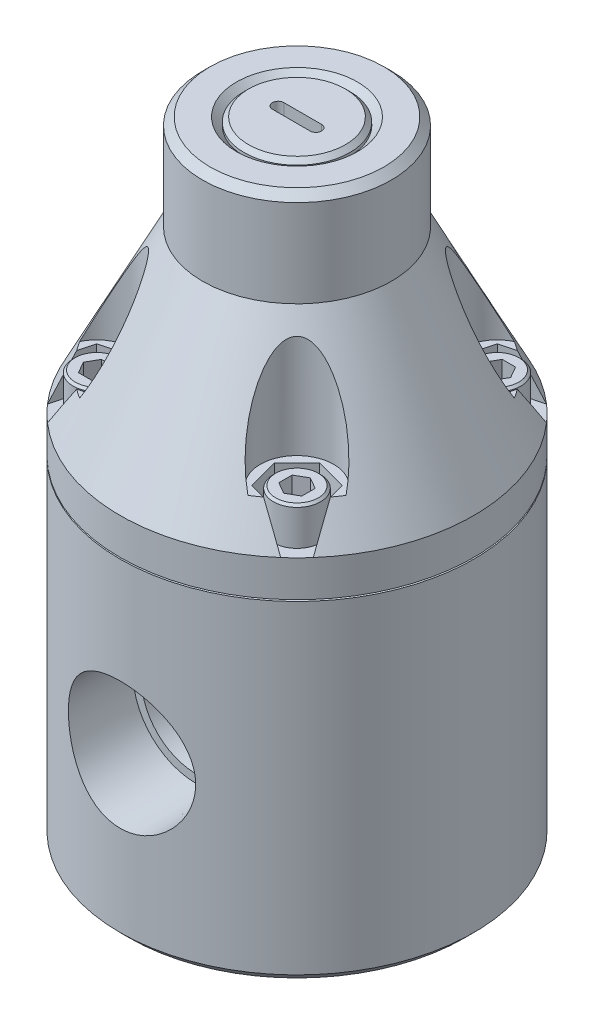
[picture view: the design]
ISO-10303-21;
HEADER;
FILE_DESCRIPTION(('STEP AP214'),'2;1');
FILE_NAME('part.step','',(''),(''),'','','');
FILE_SCHEMA(('AUTOMOTIVE_DESIGN { 1 0 10303 214 1 1 1 1 }'));
ENDSEC;
DATA;
#1=APPLICATION_CONTEXT('core data for automotive mechanical design processes');
#2=APPLICATION_PROTOCOL_DEFINITION('international standard','automotive_design',2000,#1);
#3=PRODUCT_CONTEXT('',#1,'mechanical');
#4=PRODUCT('Part','Part','',(#3));
#5=PRODUCT_RELATED_PRODUCT_CATEGORY('part','',(#4));
#6=PRODUCT_DEFINITION_FORMATION('','',#4);
#7=PRODUCT_DEFINITION_CONTEXT('part definition',#1,'design');
#8=PRODUCT_DEFINITION('design','',#6,#7);
#9=PRODUCT_DEFINITION_SHAPE('','',#8);
#10=(LENGTH_UNIT() NAMED_UNIT(*) SI_UNIT(.MILLI.,.METRE.));
#11=(NAMED_UNIT(*) PLANE_ANGLE_UNIT() SI_UNIT($,.RADIAN.));
#12=(NAMED_UNIT(*) SI_UNIT($,.STERADIAN.) SOLID_ANGLE_UNIT());
#13=UNCERTAINTY_MEASURE_WITH_UNIT(LENGTH_MEASURE(1.E-05),#10,'distance_accuracy_value','');
#14=(GEOMETRIC_REPRESENTATION_CONTEXT(3) GLOBAL_UNCERTAINTY_ASSIGNED_CONTEXT((#13)) GLOBAL_UNIT_ASSIGNED_CONTEXT((#10,
#11,#12)) REPRESENTATION_CONTEXT('',''));
#15=CARTESIAN_POINT('',(0.,0.,0.));
#16=DIRECTION('',(0.,0.,1.));
#17=DIRECTION('',(1.,0.,0.));
#18=AXIS2_PLACEMENT_3D('',#15,#16,#17);
#19=CARTESIAN_POINT('',(0.,62.23,0.));
#20=DIRECTION('',(0.,-1.,0.));
#21=DIRECTION('',(0.,0.,-1.));
#22=AXIS2_PLACEMENT_3D('',#19,#20,#21);
#23=CONICAL_SURFACE('',#22,29.718,0.471096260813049);
#24=CARTESIAN_POINT('',(-22.3373805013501,62.2298,-19.6011992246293));
#25=CARTESIAN_POINT('',(-22.2547645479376,62.7634166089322,-19.2832519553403));
#26=CARTESIAN_POINT('',(-22.1717744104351,63.29612059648,-18.9638646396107));
#27=CARTESIAN_POINT('',(-22.0049530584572,64.3594037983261,-18.3218531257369));
#28=CARTESIAN_POINT('',(-21.9211218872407,64.8899831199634,-17.9992290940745));
#29=CARTESIAN_POINT('',(-21.7525165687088,65.9487768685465,-17.3503519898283));
#30=CARTESIAN_POINT('',(-21.6677424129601,66.4769912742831,-17.0240988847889));
#31=CARTESIAN_POINT('',(-21.4971243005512,67.5307185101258,-16.367475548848));
#32=CARTESIAN_POINT('',(-21.4112802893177,68.0562312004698,-16.0371051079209));
#33=CARTESIAN_POINT('',(-21.3248419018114,68.5802,-15.7044472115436));
#34=B_SPLINE_CURVE_WITH_KNOTS('',3,(#24,#25,#26,#27,#28,#29,#30,#31,#32,#33),.UNSPECIFIED.,.F.,
.F.,(4,2,2,2,4),(0.,1.87988537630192,3.75967455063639,5.63948054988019,7.51938283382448),.UNSPECIFIED.);
#35=CARTESIAN_POINT('',(-22.3373495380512,62.23,-19.6010800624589));
#36=VERTEX_POINT('',#35);
#37=CARTESIAN_POINT('',(-21.324874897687,68.58,-15.7045741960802));
#38=VERTEX_POINT('',#37);
#39=EDGE_CURVE('E625',#36,#38,#34,.T.);
#40=ORIENTED_EDGE('',*,*,#39,.F.);
#41=CARTESIAN_POINT('',(0.,62.23,0.));
#42=DIRECTION('',(0.,-1.,0.));
#43=DIRECTION('',(0.,0.,-1.));
#44=AXIS2_PLACEMENT_3D('',#41,#42,#43);
#45=CIRCLE('',#44,29.718);
#46=CARTESIAN_POINT('',(-22.3373495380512,62.23,19.6010800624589));
#47=VERTEX_POINT('',#46);
#48=EDGE_CURVE('E950',#47,#36,#45,.T.);
#49=ORIENTED_EDGE('',*,*,#48,.F.);
#50=CARTESIAN_POINT('',(-21.3248419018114,68.5802,15.7044472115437));
#51=CARTESIAN_POINT('',(-21.4112802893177,68.0562312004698,16.0371051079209));
#52=CARTESIAN_POINT('',(-21.4971243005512,67.5307185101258,16.367475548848));
#53=CARTESIAN_POINT('',(-21.66774241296,66.4769912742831,17.024098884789));
#54=CARTESIAN_POINT('',(-21.7525165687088,65.9487768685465,17.3503519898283));
#55=CARTESIAN_POINT('',(-21.9211218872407,64.8899831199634,17.9992290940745));
#56=CARTESIAN_POINT('',(-22.0049530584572,64.3594037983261,18.3218531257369));
#57=CARTESIAN_POINT('',(-22.1717744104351,63.29612059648,18.9638646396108));
#58=CARTESIAN_POINT('',(-22.2547645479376,62.7634166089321,19.2832519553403));
#59=CARTESIAN_POINT('',(-22.3373805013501,62.2298,19.6011992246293));
#60=B_SPLINE_CURVE_WITH_KNOTS('',3,(#50,#51,#52,#53,#54,#55,#56,#57,#58,#59),.UNSPECIFIED.,.F.,
.F.,(4,2,2,2,4),(0.,1.87990228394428,3.75970828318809,5.63949745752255,7.51938283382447),.UNSPECIFIED.);
#61=CARTESIAN_POINT('',(-21.324874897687,68.58,15.7045741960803));
#62=VERTEX_POINT('',#61);
#63=EDGE_CURVE('E679',#62,#47,#60,.T.);
#64=ORIENTED_EDGE('',*,*,#63,.F.);
#65=CARTESIAN_POINT('',(0.,68.58,0.));
#66=DIRECTION('',(0.,1.,0.));
#67=DIRECTION('',(0.,0.,1.));
#68=AXIS2_PLACEMENT_3D('',#65,#66,#67);
#69=CIRCLE('',#68,26.4836542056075);
#70=CARTESIAN_POINT('',(-22.3908779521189,68.58,14.1432854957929));
#71=VERTEX_POINT('',#70);
#72=EDGE_CURVE('E1254',#62,#71,#69,.F.);
#73=ORIENTED_EDGE('',*,*,#72,.T.);
#74=CARTESIAN_POINT('',(-22.3909303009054,68.5798,14.143393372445));
#75=CARTESIAN_POINT('',(-22.350304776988,68.7350022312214,14.0596815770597));
#76=CARTESIAN_POINT('',(-22.3081630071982,68.89069928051,13.9776470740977));
#77=CARTESIAN_POINT('',(-22.2210302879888,69.2029732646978,13.8168553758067));
#78=CARTESIAN_POINT('',(-22.1760395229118,69.3595501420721,13.7380979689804));
#79=CARTESIAN_POINT('',(-22.0370947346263,69.8303500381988,13.5066666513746));
#80=CARTESIAN_POINT('',(-21.9391379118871,70.1457572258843,13.3587718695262));
#81=CARTESIAN_POINT('',(-21.7338262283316,70.7787217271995,13.0753567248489));
#82=CARTESIAN_POINT('',(-21.6264783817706,71.0962772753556,12.9398272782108));
#83=CARTESIAN_POINT('',(-21.4032338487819,71.7332404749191,12.6806046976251));
#84=CARTESIAN_POINT('',(-21.2873363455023,72.0526483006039,12.556912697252));
#85=CARTESIAN_POINT('',(-21.0470421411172,72.6946343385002,12.3204109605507));
#86=CARTESIAN_POINT('',(-20.9226003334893,73.0172202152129,12.2076680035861));
#87=CARTESIAN_POINT('',(-20.6663853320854,73.6632945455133,11.9936819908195));
#88=CARTESIAN_POINT('',(-20.5346119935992,73.9867830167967,11.8924391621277));
#89=CARTESIAN_POINT('',(-20.2641447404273,74.6342665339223,11.7013595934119));
#90=CARTESIAN_POINT('',(-20.1254503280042,74.9582616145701,11.6115236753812));
#91=CARTESIAN_POINT('',(-19.8414364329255,75.6062899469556,11.4433041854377));
#92=CARTESIAN_POINT('',(-19.6961171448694,75.9303231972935,11.3649202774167));
#93=CARTESIAN_POINT('',(-19.3211632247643,76.7476954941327,11.1817059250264));
#94=CARTESIAN_POINT('',(-19.0872302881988,77.2408247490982,11.0845248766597));
#95=CARTESIAN_POINT('',(-18.7249280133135,77.9784605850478,10.9599064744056));
#96=CARTESIAN_POINT('',(-18.6022415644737,78.2240315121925,10.9218885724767));
#97=CARTESIAN_POINT('',(-18.3529388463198,78.7141977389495,10.8531925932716));
#98=CARTESIAN_POINT('',(-18.2263228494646,78.9587931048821,10.8225140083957));
#99=CARTESIAN_POINT('',(-17.9690231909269,79.4465771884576,10.7688733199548));
#100=CARTESIAN_POINT('',(-17.8383410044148,79.6897663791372,10.7459084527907));
#101=CARTESIAN_POINT('',(-17.5726008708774,80.1743656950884,10.7081842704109));
#102=CARTESIAN_POINT('',(-17.4375433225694,80.4157759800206,10.693424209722));
#103=CARTESIAN_POINT('',(-17.1627429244,80.8961071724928,10.6727907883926));
#104=CARTESIAN_POINT('',(-17.0230031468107,81.1350295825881,10.6669117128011));
#105=CARTESIAN_POINT('',(-16.7382475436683,81.6097183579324,10.6649433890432));
#106=CARTESIAN_POINT('',(-16.5932325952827,81.8454852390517,10.6688525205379));
#107=CARTESIAN_POINT('',(-16.2968182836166,82.3133650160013,10.6877509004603));
#108=CARTESIAN_POINT('',(-16.1454043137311,82.5454676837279,10.7027669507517));
#109=CARTESIAN_POINT('',(-15.8354539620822,83.0038758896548,10.7457309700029));
#110=CARTESIAN_POINT('',(-15.6769137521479,83.2301782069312,10.7736859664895));
#111=CARTESIAN_POINT('',(-15.3515270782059,83.6741617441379,10.8451251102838));
#112=CARTESIAN_POINT('',(-15.1846866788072,83.8918490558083,10.8885980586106));
#113=CARTESIAN_POINT('',(-14.9269806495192,84.2084557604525,10.9683843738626));
#114=CARTESIAN_POINT('',(-14.839881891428,84.3122892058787,10.997391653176));
#115=CARTESIAN_POINT('',(-14.6629301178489,84.515808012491,11.0609509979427));
#116=CARTESIAN_POINT('',(-14.5730777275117,84.6154943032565,11.0955018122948));
#117=CARTESIAN_POINT('',(-14.3891167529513,84.8109037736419,11.1714874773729));
#118=CARTESIAN_POINT('',(-14.2949676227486,84.9065572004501,11.2130072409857));
#119=CARTESIAN_POINT('',(-14.1034347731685,85.0907355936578,11.3035808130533));
#120=CARTESIAN_POINT('',(-14.0060494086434,85.1792568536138,11.3526385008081));
#121=CARTESIAN_POINT('',(-13.7101223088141,85.429646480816,11.5123405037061));
#122=CARTESIAN_POINT('',(-13.5060546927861,85.5782916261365,11.6361944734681));
#123=CARTESIAN_POINT('',(-13.1996116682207,85.7493306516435,11.8507095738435));
#124=CARTESIAN_POINT('',(-13.0998509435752,85.7971000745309,11.9248690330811));
#125=CARTESIAN_POINT('',(-12.900706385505,85.873763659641,12.0829789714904));
#126=CARTESIAN_POINT('',(-12.8013223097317,85.9026733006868,12.1669213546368));
#127=CARTESIAN_POINT('',(-12.6053038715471,85.9385908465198,12.3437610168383));
#128=CARTESIAN_POINT('',(-12.5086917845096,85.9454540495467,12.4367133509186));
#129=CARTESIAN_POINT('',(-12.3223166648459,85.9359739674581,12.6281475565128));
#130=CARTESIAN_POINT('',(-12.2325552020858,85.9196253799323,12.7266306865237));
#131=CARTESIAN_POINT('',(-12.0684910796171,85.8677160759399,12.9184346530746));
#132=CARTESIAN_POINT('',(-11.9935403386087,85.8336265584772,13.0116153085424));
#133=CARTESIAN_POINT('',(-11.8522698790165,85.7502029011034,13.1975950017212));
#134=CARTESIAN_POINT('',(-11.7859543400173,85.7008614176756,13.290393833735));
#135=CARTESIAN_POINT('',(-11.6163662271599,85.5496530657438,13.5413620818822));
#136=CARTESIAN_POINT('',(-11.5214197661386,85.4357254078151,13.6978402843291));
#137=CARTESIAN_POINT('',(-11.3524385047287,85.1845941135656,14.0032728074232));
#138=CARTESIAN_POINT('',(-11.2784789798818,85.0473094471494,14.1521985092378));
#139=CARTESIAN_POINT('',(-11.1484302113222,84.7600134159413,14.44015441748));
#140=CARTESIAN_POINT('',(-11.0920802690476,84.6102339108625,14.5793027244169));
#141=CARTESIAN_POINT('',(-10.9925096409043,84.3006741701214,14.851149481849));
#142=CARTESIAN_POINT('',(-10.9493023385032,84.1408839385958,14.9838412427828));
#143=CARTESIAN_POINT('',(-10.8736636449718,83.8139640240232,15.2438249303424));
#144=CARTESIAN_POINT('',(-10.8412572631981,83.6468183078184,15.3711037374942));
#145=CARTESIAN_POINT('',(-10.7856662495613,83.307480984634,15.6206584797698));
#146=CARTESIAN_POINT('',(-10.7624784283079,83.1352911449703,15.7429361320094));
#147=CARTESIAN_POINT('',(-10.7205377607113,82.7552655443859,16.0051192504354));
#148=CARTESIAN_POINT('',(-10.7033691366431,82.5466647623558,16.1441638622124));
#149=CARTESIAN_POINT('',(-10.6786273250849,82.125493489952,16.4170496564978));
#150=CARTESIAN_POINT('',(-10.6710565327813,81.9129220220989,16.5508895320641));
#151=CARTESIAN_POINT('',(-10.664422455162,81.4846459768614,16.8140587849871));
#152=CARTESIAN_POINT('',(-10.6653663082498,81.2689389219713,16.9433842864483));
#153=CARTESIAN_POINT('',(-10.674967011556,80.8352423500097,17.1978874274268));
#154=CARTESIAN_POINT('',(-10.6836247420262,80.6172525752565,17.323064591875));
#155=CARTESIAN_POINT('',(-10.7080782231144,80.178919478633,17.5699535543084));
#156=CARTESIAN_POINT('',(-10.7238938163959,79.9585712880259,17.691654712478));
#157=CARTESIAN_POINT('',(-10.7622068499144,79.516512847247,17.9314908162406));
#158=CARTESIAN_POINT('',(-10.7847047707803,79.2948025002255,18.0496255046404));
#159=CARTESIAN_POINT('',(-10.8616544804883,78.628245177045,18.3989144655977));
#160=CARTESIAN_POINT('',(-10.9255713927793,78.1818168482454,18.6250403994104));
#161=CARTESIAN_POINT('',(-11.0664102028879,77.3479438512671,19.0346218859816));
#162=CARTESIAN_POINT('',(-11.1403619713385,76.9607742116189,19.2196861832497));
#163=CARTESIAN_POINT('',(-11.3050181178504,76.1856258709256,19.5805572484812));
#164=CARTESIAN_POINT('',(-11.3957241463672,75.7976470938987,19.7563631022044));
#165=CARTESIAN_POINT('',(-11.5935742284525,75.0216151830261,20.0985507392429));
#166=CARTESIAN_POINT('',(-11.7007221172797,74.6335620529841,20.264930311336));
#167=CARTESIAN_POINT('',(-11.9313879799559,73.8581881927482,20.5877481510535));
#168=CARTESIAN_POINT('',(-12.0549056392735,73.470867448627,20.7441866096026));
#169=CARTESIAN_POINT('',(-12.3163714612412,72.7038997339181,21.0439307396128));
#170=CARTESIAN_POINT('',(-12.4540552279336,72.3242296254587,21.1874073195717));
#171=CARTESIAN_POINT('',(-12.7458005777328,71.5671030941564,21.4629534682));
#172=CARTESIAN_POINT('',(-12.8998598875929,71.1896463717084,21.5950246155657));
#173=CARTESIAN_POINT('',(-13.2250025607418,70.4376533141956,21.8464430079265));
#174=CARTESIAN_POINT('',(-13.396090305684,70.0631177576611,21.9657869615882));
#175=CARTESIAN_POINT('',(-13.6660711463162,69.5043911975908,22.1338540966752));
#176=CARTESIAN_POINT('',(-13.7583155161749,69.3186135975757,22.1880644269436));
#177=CARTESIAN_POINT('',(-13.9473861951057,68.9482602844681,22.2925349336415));
#178=CARTESIAN_POINT('',(-14.044212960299,68.7636846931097,22.3427947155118));
#179=CARTESIAN_POINT('',(-14.1433933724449,68.5798000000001,22.3909303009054));
#180=B_SPLINE_CURVE_WITH_KNOTS('',3,(#74,#75,#76,#77,#78,#79,#80,#81,#82,#83,#84,#85,#86,#87,
#88,#89,#90,#91,#92,#93,#94,#95,#96,#97,#98,#99,#100,#101,#102,#103,#104,#105,#106,#107,#108,
#109,#110,#111,#112,#113,#114,#115,#116,#117,#118,#119,#120,#121,#122,#123,#124,#125,#126,#127,
#128,#129,#130,#131,#132,#133,#134,#135,#136,#137,#138,#139,#140,#141,#142,#143,#144,#145,#146,
#147,#148,#149,#150,#151,#152,#153,#154,#155,#156,#157,#158,#159,#160,#161,#162,#163,#164,#165,
#166,#167,#168,#169,#170,#171,#172,#173,#174,#175,#176,#177,#178,#179),.UNSPECIFIED.,.F.,.F.,(4,
2,2,2,2,2,2,2,2,2,2,2,2,2,2,2,2,2,2,2,2,2,2,2,2,2,2,2,2,2,2,2,2,2,2,2,2,2,2,2,2,2,2,2,2,2,2,2,2,
2,2,2,4),(0.,0.542840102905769,1.08564511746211,2.17085376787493,3.25525867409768,
4.33976732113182,5.43052218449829,6.5212985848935,7.61215354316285,8.70297647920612,
10.3650975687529,11.196398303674,12.027641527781,12.8585866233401,13.6894562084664,
14.5197908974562,15.3499881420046,16.1821952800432,17.014854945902,17.8469149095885,
18.2625409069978,18.6780732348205,19.0990950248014,19.5203342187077,20.354755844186,
20.7529146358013,21.1507462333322,21.5511837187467,21.9517126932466,22.32334462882,
22.6951557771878,23.3381727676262,23.9834677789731,24.6186994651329,25.2545758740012,
25.8919145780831,26.5290325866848,27.2825500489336,28.0362555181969,28.7905929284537,
29.5450164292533,30.3015442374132,31.0581264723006,32.5707579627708,33.8767149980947,
35.1828007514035,36.4891916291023,37.7955574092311,39.0808873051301,40.3660390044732,
41.6515222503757,42.2946005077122,42.9377429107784),.UNSPECIFIED.);
#181=CARTESIAN_POINT('',(-14.1432854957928,68.58,22.390877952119));
#182=VERTEX_POINT('',#181);
#183=EDGE_CURVE('E1226',#71,#182,#180,.T.);
#184=ORIENTED_EDGE('',*,*,#183,.T.);
#185=CARTESIAN_POINT('',(-15.7045741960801,68.58,21.3248748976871));
#186=VERTEX_POINT('',#185);
#187=EDGE_CURVE('E1228',#182,#186,#69,.F.);
#188=ORIENTED_EDGE('',*,*,#187,.T.);
#189=CARTESIAN_POINT('',(-19.6011992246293,62.2298,22.3373805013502));
#190=CARTESIAN_POINT('',(-19.2832519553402,62.7634166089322,22.2547645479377));
#191=CARTESIAN_POINT('',(-18.9638646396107,63.29612059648,22.1717744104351));
#192=CARTESIAN_POINT('',(-18.3218531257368,64.3594037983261,22.0049530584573));
#193=CARTESIAN_POINT('',(-17.9992290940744,64.8899831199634,21.9211218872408));
#194=CARTESIAN_POINT('',(-17.3503519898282,65.9487768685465,21.7525165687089));
#195=CARTESIAN_POINT('',(-17.0240988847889,66.4769912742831,21.6677424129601));
#196=CARTESIAN_POINT('',(-16.3674755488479,67.5307185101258,21.4971243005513));
#197=CARTESIAN_POINT('',(-16.0371051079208,68.0562312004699,21.4112802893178));
#198=CARTESIAN_POINT('',(-15.7044472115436,68.5802,21.3248419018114));
#199=B_SPLINE_CURVE_WITH_KNOTS('',3,(#189,#190,#191,#192,#193,#194,#195,#196,#197,#198),
.UNSPECIFIED.,.F.,.F.,(4,2,2,2,4),(0.,1.87988537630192,3.75967455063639,5.63948054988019,
7.51938283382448),.UNSPECIFIED.);
#200=CARTESIAN_POINT('',(-19.6010800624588,62.23,22.3373495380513));
#201=VERTEX_POINT('',#200);
#202=EDGE_CURVE('E672',#201,#186,#199,.T.);
#203=ORIENTED_EDGE('',*,*,#202,.F.);
#204=CARTESIAN_POINT('',(19.601080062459,62.23,22.3373495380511));
#205=VERTEX_POINT('',#204);
#206=EDGE_CURVE('E963',#205,#201,#45,.T.);
#207=ORIENTED_EDGE('',*,*,#206,.F.);
#208=CARTESIAN_POINT('',(15.7044472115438,68.5802,21.3248419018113));
#209=CARTESIAN_POINT('',(16.037105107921,68.0562312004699,21.4112802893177));
#210=CARTESIAN_POINT('',(16.3674755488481,67.5307185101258,21.4971243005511));
#211=CARTESIAN_POINT('',(17.024098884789,66.4769912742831,21.66774241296));
#212=CARTESIAN_POINT('',(17.3503519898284,65.9487768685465,21.7525165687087));
#213=CARTESIAN_POINT('',(17.9992290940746,64.8899831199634,21.9211218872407));
#214=CARTESIAN_POINT('',(18.321853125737,64.3594037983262,22.0049530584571));
#215=CARTESIAN_POINT('',(18.9638646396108,63.29612059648,22.171774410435));
#216=CARTESIAN_POINT('',(19.2832519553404,62.7634166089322,22.2547645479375));
#217=CARTESIAN_POINT('',(19.6011992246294,62.2298,22.33738050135));
#218=B_SPLINE_CURVE_WITH_KNOTS('',3,(#208,#209,#210,#211,#212,#213,#214,#215,#216,#217),
.UNSPECIFIED.,.F.,.F.,(4,2,2,2,4),(0.,1.87990228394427,3.75970828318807,5.63949745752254,
7.51938283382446),.UNSPECIFIED.);
#219=CARTESIAN_POINT('',(15.7045741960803,68.58,21.3248748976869));
#220=VERTEX_POINT('',#219);
#221=EDGE_CURVE('E710',#220,#205,#218,.T.);
#222=ORIENTED_EDGE('',*,*,#221,.F.);
#223=CARTESIAN_POINT('',(0.,68.58,0.));
#224=DIRECTION('',(0.,1.,0.));
#225=DIRECTION('',(0.,0.,1.));
#226=AXIS2_PLACEMENT_3D('',#223,#224,#225);
#227=CIRCLE('',#226,26.4836542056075);
#228=CARTESIAN_POINT('',(14.143285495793,68.58,22.3908779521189));
#229=VERTEX_POINT('',#228);
#230=EDGE_CURVE('E875',#220,#229,#227,.F.);
#231=ORIENTED_EDGE('',*,*,#230,.T.);
#232=CARTESIAN_POINT('',(14.1433933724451,68.5798,22.3909303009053));
#233=CARTESIAN_POINT('',(14.0596815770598,68.7350022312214,22.3503047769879));
#234=CARTESIAN_POINT('',(13.9776470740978,68.89069928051,22.3081630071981));
#235=CARTESIAN_POINT('',(13.8168553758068,69.2029732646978,22.2210302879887));
#236=CARTESIAN_POINT('',(13.7380979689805,69.3595501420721,22.1760395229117));
#237=CARTESIAN_POINT('',(13.5066666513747,69.8303500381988,22.0370947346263));
#238=CARTESIAN_POINT('',(13.3587718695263,70.1457572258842,21.939137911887));
#239=CARTESIAN_POINT('',(13.075356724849,70.7787217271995,21.7338262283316));
#240=CARTESIAN_POINT('',(12.9398272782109,71.0962772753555,21.6264783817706));
#241=CARTESIAN_POINT('',(12.6806046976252,71.7332404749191,21.4032338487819));
#242=CARTESIAN_POINT('',(12.5569126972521,72.0526483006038,21.2873363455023));
#243=CARTESIAN_POINT('',(12.3204109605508,72.6946343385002,21.0470421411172));
#244=CARTESIAN_POINT('',(12.2076680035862,73.0172202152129,20.9226003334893));
#245=CARTESIAN_POINT('',(11.9936819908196,73.6632945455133,20.6663853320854));
#246=CARTESIAN_POINT('',(11.8924391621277,73.9867830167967,20.5346119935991));
#247=CARTESIAN_POINT('',(11.7013595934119,74.6342665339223,20.2641447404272));
#248=CARTESIAN_POINT('',(11.6115236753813,74.9582616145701,20.1254503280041));
#249=CARTESIAN_POINT('',(11.4433041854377,75.6062899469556,19.8414364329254));
#250=CARTESIAN_POINT('',(11.3649202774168,75.9303231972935,19.6961171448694));
#251=CARTESIAN_POINT('',(11.1817059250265,76.7476954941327,19.3211632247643));
#252=CARTESIAN_POINT('',(11.0845248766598,77.2408247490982,19.0872302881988));
#253=CARTESIAN_POINT('',(10.9599064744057,77.9784605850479,18.7249280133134));
#254=CARTESIAN_POINT('',(10.9218885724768,78.2240315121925,18.6022415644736));
#255=CARTESIAN_POINT('',(10.8531925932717,78.7141977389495,18.3529388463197));
#256=CARTESIAN_POINT('',(10.8225140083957,78.9587931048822,18.2263228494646));
#257=CARTESIAN_POINT('',(10.7688733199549,79.4465771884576,17.9690231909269));
#258=CARTESIAN_POINT('',(10.7459084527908,79.6897663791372,17.8383410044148));
#259=CARTESIAN_POINT('',(10.7081842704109,80.1743656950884,17.5726008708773));
#260=CARTESIAN_POINT('',(10.6934242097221,80.4157759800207,17.4375433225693));
#261=CARTESIAN_POINT('',(10.6727907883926,80.8961071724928,17.1627429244));
#262=CARTESIAN_POINT('',(10.6669117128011,81.1350295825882,17.0230031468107));
#263=CARTESIAN_POINT('',(10.6649433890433,81.6097183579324,16.7382475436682));
#264=CARTESIAN_POINT('',(10.668852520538,81.8454852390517,16.5932325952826));
#265=CARTESIAN_POINT('',(10.6877509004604,82.3133650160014,16.2968182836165));
#266=CARTESIAN_POINT('',(10.7027669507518,82.545467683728,16.1454043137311));
#267=CARTESIAN_POINT('',(10.745730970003,83.0038758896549,15.8354539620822));
#268=CARTESIAN_POINT('',(10.7736859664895,83.2301782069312,15.6769137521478));
#269=CARTESIAN_POINT('',(10.8451251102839,83.6741617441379,15.3515270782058));
#270=CARTESIAN_POINT('',(10.8885980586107,83.8918490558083,15.1846866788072));
#271=CARTESIAN_POINT('',(10.9683843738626,84.2084557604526,14.9269806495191));
#272=CARTESIAN_POINT('',(10.997391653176,84.3122892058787,14.8398818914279));
#273=CARTESIAN_POINT('',(11.0609509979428,84.515808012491,14.6629301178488));
#274=CARTESIAN_POINT('',(11.0955018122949,84.6154943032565,14.5730777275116));
#275=CARTESIAN_POINT('',(11.171487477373,84.8109037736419,14.3891167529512));
#276=CARTESIAN_POINT('',(11.2130072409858,84.9065572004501,14.2949676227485));
#277=CARTESIAN_POINT('',(11.3035808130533,85.0907355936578,14.1034347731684));
#278=CARTESIAN_POINT('',(11.3526385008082,85.1792568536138,14.0060494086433));
#279=CARTESIAN_POINT('',(11.5123405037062,85.4296464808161,13.710122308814));
#280=CARTESIAN_POINT('',(11.6361944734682,85.5782916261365,13.506054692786));
#281=CARTESIAN_POINT('',(11.8507095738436,85.7493306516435,13.1996116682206));
#282=CARTESIAN_POINT('',(11.9248690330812,85.797100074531,13.0998509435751));
#283=CARTESIAN_POINT('',(12.0829789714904,85.873763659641,12.9007063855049));
#284=CARTESIAN_POINT('',(12.1669213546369,85.9026733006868,12.8013223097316));
#285=CARTESIAN_POINT('',(12.3437610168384,85.9385908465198,12.605303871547));
#286=CARTESIAN_POINT('',(12.4367133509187,85.9454540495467,12.5086917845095));
#287=CARTESIAN_POINT('',(12.6281475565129,85.9359739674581,12.3223166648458));
#288=CARTESIAN_POINT('',(12.7266306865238,85.9196253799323,12.2325552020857));
#289=CARTESIAN_POINT('',(12.9184346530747,85.8677160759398,12.068491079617));
#290=CARTESIAN_POINT('',(13.0116153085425,85.8336265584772,11.9935403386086));
#291=CARTESIAN_POINT('',(13.1975950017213,85.7502029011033,11.8522698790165));
#292=CARTESIAN_POINT('',(13.2903938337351,85.7008614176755,11.7859543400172));
#293=CARTESIAN_POINT('',(13.5413620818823,85.5496530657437,11.6163662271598));
#294=CARTESIAN_POINT('',(13.6978402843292,85.435725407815,11.5214197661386));
#295=CARTESIAN_POINT('',(14.0032728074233,85.1845941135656,11.3524385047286));
#296=CARTESIAN_POINT('',(14.1521985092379,85.0473094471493,11.2784789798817));
#297=CARTESIAN_POINT('',(14.4401544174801,84.7600134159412,11.1484302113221));
#298=CARTESIAN_POINT('',(14.579302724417,84.6102339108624,11.0920802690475));
#299=CARTESIAN_POINT('',(14.8511494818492,84.3006741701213,10.9925096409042));
#300=CARTESIAN_POINT('',(14.983841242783,84.1408839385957,10.9493023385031));
#301=CARTESIAN_POINT('',(15.2438249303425,83.813964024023,10.8736636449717));
#302=CARTESIAN_POINT('',(15.3711037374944,83.6468183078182,10.841257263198));
#303=CARTESIAN_POINT('',(15.62065847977,83.3074809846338,10.7856662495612));
#304=CARTESIAN_POINT('',(15.7429361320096,83.1352911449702,10.7624784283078));
#305=CARTESIAN_POINT('',(16.0051192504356,82.7552655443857,10.7205377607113));
#306=CARTESIAN_POINT('',(16.1441638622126,82.5466647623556,10.703369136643));
#307=CARTESIAN_POINT('',(16.417049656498,82.1254934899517,10.6786273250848));
#308=CARTESIAN_POINT('',(16.5508895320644,81.9129220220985,10.6710565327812));
#309=CARTESIAN_POINT('',(16.8140587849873,81.4846459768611,10.6644224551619));
#310=CARTESIAN_POINT('',(16.9433842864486,81.2689389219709,10.6653663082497));
#311=CARTESIAN_POINT('',(17.1978874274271,80.8352423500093,10.674967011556));
#312=CARTESIAN_POINT('',(17.3230645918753,80.6172525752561,10.6836247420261));
#313=CARTESIAN_POINT('',(17.5699535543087,80.1789194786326,10.7080782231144));
#314=CARTESIAN_POINT('',(17.6916547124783,79.9585712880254,10.7238938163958));
#315=CARTESIAN_POINT('',(17.9314908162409,79.5165128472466,10.7622068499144));
#316=CARTESIAN_POINT('',(18.0496255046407,79.294802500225,10.7847047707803));
#317=CARTESIAN_POINT('',(18.398914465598,78.6282451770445,10.8616544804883));
#318=CARTESIAN_POINT('',(18.6250403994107,78.1818168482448,10.9255713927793));
#319=CARTESIAN_POINT('',(19.0346218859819,77.3479438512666,11.0664102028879));
#320=CARTESIAN_POINT('',(19.21968618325,76.9607742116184,11.1403619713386));
#321=CARTESIAN_POINT('',(19.5805572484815,76.1856258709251,11.3050181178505));
#322=CARTESIAN_POINT('',(19.7563631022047,75.7976470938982,11.3957241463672));
#323=CARTESIAN_POINT('',(20.0985507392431,75.0216151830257,11.5935742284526));
#324=CARTESIAN_POINT('',(20.2649303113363,74.6335620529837,11.7007221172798));
#325=CARTESIAN_POINT('',(20.5877481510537,73.8581881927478,11.9313879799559));
#326=CARTESIAN_POINT('',(20.7441866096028,73.4708674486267,12.0549056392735));
#327=CARTESIAN_POINT('',(21.0439307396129,72.7038997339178,12.3163714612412));
#328=CARTESIAN_POINT('',(21.1874073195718,72.3242296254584,12.4540552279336));
#329=CARTESIAN_POINT('',(21.4629534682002,71.5671030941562,12.7458005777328));
#330=CARTESIAN_POINT('',(21.5950246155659,71.1896463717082,12.8998598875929));
#331=CARTESIAN_POINT('',(21.8464430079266,70.4376533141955,13.2250025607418));
#332=CARTESIAN_POINT('',(21.9657869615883,70.0631177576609,13.396090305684));
#333=CARTESIAN_POINT('',(22.1338540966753,69.5043911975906,13.6660711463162));
#334=CARTESIAN_POINT('',(22.1880644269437,69.3186135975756,13.7583155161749));
#335=CARTESIAN_POINT('',(22.2925349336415,68.948260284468,13.9473861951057));
#336=CARTESIAN_POINT('',(22.3427947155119,68.7636846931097,14.0442129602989));
#337=CARTESIAN_POINT('',(22.3909303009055,68.5798,14.1433933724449));
#338=B_SPLINE_CURVE_WITH_KNOTS('',3,(#232,#233,#234,#235,#236,#237,#238,#239,#240,#241,#242,
#243,#244,#245,#246,#247,#248,#249,#250,#251,#252,#253,#254,#255,#256,#257,#258,#259,#260,#261,
#262,#263,#264,#265,#266,#267,#268,#269,#270,#271,#272,#273,#274,#275,#276,#277,#278,#279,#280,
#281,#282,#283,#284,#285,#286,#287,#288,#289,#290,#291,#292,#293,#294,#295,#296,#297,#298,#299,
#300,#301,#302,#303,#304,#305,#306,#307,#308,#309,#310,#311,#312,#313,#314,#315,#316,#317,#318,
#319,#320,#321,#322,#323,#324,#325,#326,#327,#328,#329,#330,#331,#332,#333,#334,#335,#336,#337),
.UNSPECIFIED.,.F.,.F.,(4,2,2,2,2,2,2,2,2,2,2,2,2,2,2,2,2,2,2,2,2,2,2,2,2,2,2,2,2,2,2,2,2,2,2,2,
2,2,2,2,2,2,2,2,2,2,2,2,2,2,2,2,4),(0.,0.542840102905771,1.08564511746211,2.17085376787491,
3.25525867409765,4.3397673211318,5.43052218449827,6.52129858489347,7.61215354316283,
8.7029764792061,10.3650975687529,11.196398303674,12.0276415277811,12.8585866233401,
13.6894562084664,14.5197908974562,15.3499881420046,16.1821952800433,17.0148549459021,
17.8469149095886,18.2625409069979,18.6780732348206,19.0990950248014,19.5203342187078,
20.3547558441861,20.7529146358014,21.1507462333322,21.5511837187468,21.9517126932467,
22.3233446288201,22.6951557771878,23.3381727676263,23.9834677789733,24.618699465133,
25.2545758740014,25.8919145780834,26.529032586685,27.2825500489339,28.0362555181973,
28.7905929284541,29.5450164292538,30.3015442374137,31.0581264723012,32.5707579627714,
33.8767149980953,35.182800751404,36.4891916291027,37.7955574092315,39.0808873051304,
40.3660390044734,41.6515222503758,42.2946005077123,42.9377429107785),.UNSPECIFIED.);
#339=CARTESIAN_POINT('',(22.390877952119,68.58,14.1432854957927));
#340=VERTEX_POINT('',#339);
#341=EDGE_CURVE('E1249',#229,#340,#338,.T.);
#342=ORIENTED_EDGE('',*,*,#341,.T.);
#343=CARTESIAN_POINT('',(21.3248748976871,68.58,15.7045741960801));
#344=VERTEX_POINT('',#343);
#345=EDGE_CURVE('E876',#340,#344,#227,.F.);
#346=ORIENTED_EDGE('',*,*,#345,.T.);
#347=CARTESIAN_POINT('',(22.3373805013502,62.2298,19.6011992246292));
#348=CARTESIAN_POINT('',(22.2547645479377,62.7634166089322,19.2832519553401));
#349=CARTESIAN_POINT('',(22.1717744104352,63.29612059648,18.9638646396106));
#350=CARTESIAN_POINT('',(22.0049530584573,64.3594037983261,18.3218531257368));
#351=CARTESIAN_POINT('',(21.9211218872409,64.8899831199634,17.9992290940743));
#352=CARTESIAN_POINT('',(21.752516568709,65.9487768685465,17.3503519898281));
#353=CARTESIAN_POINT('',(21.6677424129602,66.4769912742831,17.0240988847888));
#354=CARTESIAN_POINT('',(21.4971243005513,67.5307185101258,16.3674755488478));
#355=CARTESIAN_POINT('',(21.4112802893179,68.0562312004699,16.0371051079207));
#356=CARTESIAN_POINT('',(21.3248419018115,68.5802,15.7044472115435));
#357=B_SPLINE_CURVE_WITH_KNOTS('',3,(#347,#348,#349,#350,#351,#352,#353,#354,#355,#356),
.UNSPECIFIED.,.F.,.F.,(4,2,2,2,4),(0.,1.87988537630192,3.75967455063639,5.63948054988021,
7.51938283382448),.UNSPECIFIED.);
#358=CARTESIAN_POINT('',(22.3373495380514,62.23,19.6010800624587));
#359=VERTEX_POINT('',#358);
#360=EDGE_CURVE('E723',#359,#344,#357,.T.);
#361=ORIENTED_EDGE('',*,*,#360,.F.);
#362=CARTESIAN_POINT('',(22.3373495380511,62.23,-19.6010800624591));
#363=VERTEX_POINT('',#362);
#364=EDGE_CURVE('E834',#363,#359,#45,.T.);
#365=ORIENTED_EDGE('',*,*,#364,.F.);
#366=CARTESIAN_POINT('',(21.3248419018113,68.5802,-15.7044472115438));
#367=CARTESIAN_POINT('',(21.4112802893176,68.0562312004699,-16.037105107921));
#368=CARTESIAN_POINT('',(21.4971243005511,67.5307185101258,-16.3674755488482));
#369=CARTESIAN_POINT('',(21.6677424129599,66.4769912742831,-17.0240988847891));
#370=CARTESIAN_POINT('',(21.7525165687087,65.9487768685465,-17.3503519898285));
#371=CARTESIAN_POINT('',(21.9211218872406,64.8899831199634,-17.9992290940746));
#372=CARTESIAN_POINT('',(22.004953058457,64.3594037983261,-18.3218531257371));
#373=CARTESIAN_POINT('',(22.1717744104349,63.29612059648,-18.9638646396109));
#374=CARTESIAN_POINT('',(22.2547645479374,62.7634166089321,-19.2832519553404));
#375=CARTESIAN_POINT('',(22.3373805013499,62.2298,-19.6011992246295));
#376=B_SPLINE_CURVE_WITH_KNOTS('',3,(#366,#367,#368,#369,#370,#371,#372,#373,#374,#375),
.UNSPECIFIED.,.F.,.F.,(4,2,2,2,4),(0.,1.87990228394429,3.75970828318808,5.63949745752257,
7.51938283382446),.UNSPECIFIED.);
#377=CARTESIAN_POINT('',(21.3248748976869,68.58,-15.7045741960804));
#378=VERTEX_POINT('',#377);
#379=EDGE_CURVE('E772',#378,#363,#376,.T.);
#380=ORIENTED_EDGE('',*,*,#379,.F.);
#381=CARTESIAN_POINT('',(0.,68.58,0.));
#382=DIRECTION('',(0.,1.,0.));
#383=DIRECTION('',(0.,0.,1.));
#384=AXIS2_PLACEMENT_3D('',#381,#382,#383);
#385=CIRCLE('',#384,26.4836542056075);
#386=CARTESIAN_POINT('',(22.3908779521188,68.58,-14.1432854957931));
#387=VERTEX_POINT('',#386);
#388=EDGE_CURVE('E864',#378,#387,#385,.F.);
#389=ORIENTED_EDGE('',*,*,#388,.T.);
#390=CARTESIAN_POINT('',(22.3909303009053,68.5798000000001,-14.1433933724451));
#391=CARTESIAN_POINT('',(22.3503047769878,68.7350022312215,-14.0596815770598));
#392=CARTESIAN_POINT('',(22.3081630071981,68.8906992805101,-13.9776470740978));
#393=CARTESIAN_POINT('',(22.2210302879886,69.2029732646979,-13.8168553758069));
#394=CARTESIAN_POINT('',(22.1760395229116,69.3595501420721,-13.7380979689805));
#395=CARTESIAN_POINT('',(22.0370947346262,69.8303500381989,-13.5066666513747));
#396=CARTESIAN_POINT('',(21.939137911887,70.1457572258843,-13.3587718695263));
#397=CARTESIAN_POINT('',(21.7338262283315,70.7787217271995,-13.075356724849));
#398=CARTESIAN_POINT('',(21.6264783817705,71.0962772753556,-12.9398272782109));
#399=CARTESIAN_POINT('',(21.4032338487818,71.7332404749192,-12.6806046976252));
#400=CARTESIAN_POINT('',(21.2873363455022,72.0526483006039,-12.5569126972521));
#401=CARTESIAN_POINT('',(21.0470421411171,72.6946343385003,-12.3204109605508));
#402=CARTESIAN_POINT('',(20.9226003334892,73.017220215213,-12.2076680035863));
#403=CARTESIAN_POINT('',(20.6663853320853,73.6632945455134,-11.9936819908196));
#404=CARTESIAN_POINT('',(20.5346119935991,73.9867830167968,-11.8924391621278));
#405=CARTESIAN_POINT('',(20.2641447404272,74.6342665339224,-11.701359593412));
#406=CARTESIAN_POINT('',(20.1254503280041,74.9582616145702,-11.6115236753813));
#407=CARTESIAN_POINT('',(19.8414364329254,75.6062899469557,-11.4433041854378));
#408=CARTESIAN_POINT('',(19.6961171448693,75.9303231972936,-11.3649202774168));
#409=CARTESIAN_POINT('',(19.3211632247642,76.7476954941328,-11.1817059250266));
#410=CARTESIAN_POINT('',(19.0872302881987,77.2408247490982,-11.0845248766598));
#411=CARTESIAN_POINT('',(18.7249280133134,77.9784605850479,-10.9599064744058));
#412=CARTESIAN_POINT('',(18.6022415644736,78.2240315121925,-10.9218885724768));
#413=CARTESIAN_POINT('',(18.3529388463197,78.7141977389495,-10.8531925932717));
#414=CARTESIAN_POINT('',(18.2263228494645,78.9587931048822,-10.8225140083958));
#415=CARTESIAN_POINT('',(17.9690231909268,79.4465771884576,-10.7688733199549));
#416=CARTESIAN_POINT('',(17.8383410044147,79.6897663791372,-10.7459084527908));
#417=CARTESIAN_POINT('',(17.5726008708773,80.1743656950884,-10.708184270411));
#418=CARTESIAN_POINT('',(17.4375433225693,80.4157759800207,-10.6934242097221));
#419=CARTESIAN_POINT('',(17.1627429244,80.8961071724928,-10.6727907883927));
#420=CARTESIAN_POINT('',(17.0230031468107,81.1350295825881,-10.6669117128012));
#421=CARTESIAN_POINT('',(16.7382475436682,81.6097183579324,-10.6649433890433));
#422=CARTESIAN_POINT('',(16.5932325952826,81.8454852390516,-10.668852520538));
#423=CARTESIAN_POINT('',(16.2968182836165,82.3133650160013,-10.6877509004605));
#424=CARTESIAN_POINT('',(16.1454043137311,82.5454676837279,-10.7027669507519));
#425=CARTESIAN_POINT('',(15.8354539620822,83.0038758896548,-10.745730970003));
#426=CARTESIAN_POINT('',(15.6769137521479,83.2301782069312,-10.7736859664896));
#427=CARTESIAN_POINT('',(15.3515270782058,83.6741617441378,-10.8451251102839));
#428=CARTESIAN_POINT('',(15.1846866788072,83.8918490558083,-10.8885980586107));
#429=CARTESIAN_POINT('',(14.9269806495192,84.2084557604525,-10.9683843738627));
#430=CARTESIAN_POINT('',(14.8398818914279,84.3122892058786,-10.9973916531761));
#431=CARTESIAN_POINT('',(14.6629301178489,84.5158080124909,-11.0609509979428));
#432=CARTESIAN_POINT('',(14.5730777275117,84.6154943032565,-11.0955018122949));
#433=CARTESIAN_POINT('',(14.3891167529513,84.8109037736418,-11.171487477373));
#434=CARTESIAN_POINT('',(14.2949676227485,84.90655720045,-11.2130072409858));
#435=CARTESIAN_POINT('',(14.1034347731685,85.0907355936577,-11.3035808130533));
#436=CARTESIAN_POINT('',(14.0060494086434,85.1792568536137,-11.3526385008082));
#437=CARTESIAN_POINT('',(13.7101223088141,85.429646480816,-11.5123405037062));
#438=CARTESIAN_POINT('',(13.5060546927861,85.5782916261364,-11.6361944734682));
#439=CARTESIAN_POINT('',(13.1996116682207,85.7493306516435,-11.8507095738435));
#440=CARTESIAN_POINT('',(13.0998509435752,85.7971000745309,-11.9248690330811));
#441=CARTESIAN_POINT('',(12.9007063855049,85.873763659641,-12.0829789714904));
#442=CARTESIAN_POINT('',(12.8013223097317,85.9026733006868,-12.1669213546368));
#443=CARTESIAN_POINT('',(12.6053038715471,85.9385908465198,-12.3437610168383));
#444=CARTESIAN_POINT('',(12.5086917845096,85.9454540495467,-12.4367133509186));
#445=CARTESIAN_POINT('',(12.3223166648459,85.9359739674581,-12.6281475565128));
#446=CARTESIAN_POINT('',(12.2325552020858,85.9196253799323,-12.7266306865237));
#447=CARTESIAN_POINT('',(12.0684910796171,85.8677160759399,-12.9184346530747));
#448=CARTESIAN_POINT('',(11.9935403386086,85.8336265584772,-13.0116153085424));
#449=CARTESIAN_POINT('',(11.8522698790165,85.7502029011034,-13.1975950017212));
#450=CARTESIAN_POINT('',(11.7859543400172,85.7008614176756,-13.290393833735));
#451=CARTESIAN_POINT('',(11.6163662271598,85.5496530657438,-13.5413620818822));
#452=CARTESIAN_POINT('',(11.5214197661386,85.4357254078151,-13.6978402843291));
#453=CARTESIAN_POINT('',(11.3524385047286,85.1845941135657,-14.0032728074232));
#454=CARTESIAN_POINT('',(11.2784789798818,85.0473094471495,-14.1521985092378));
#455=CARTESIAN_POINT('',(11.1484302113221,84.7600134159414,-14.4401544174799));
#456=CARTESIAN_POINT('',(11.0920802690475,84.6102339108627,-14.5793027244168));
#457=CARTESIAN_POINT('',(10.9925096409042,84.3006741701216,-14.851149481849));
#458=CARTESIAN_POINT('',(10.9493023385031,84.140883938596,-14.9838412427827));
#459=CARTESIAN_POINT('',(10.8736636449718,83.8139640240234,-15.2438249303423));
#460=CARTESIAN_POINT('',(10.841257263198,83.6468183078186,-15.3711037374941));
#461=CARTESIAN_POINT('',(10.7856662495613,83.3074809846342,-15.6206584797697));
#462=CARTESIAN_POINT('',(10.7624784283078,83.1352911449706,-15.7429361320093));
#463=CARTESIAN_POINT('',(10.7205377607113,82.7552655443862,-16.0051192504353));
#464=CARTESIAN_POINT('',(10.703369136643,82.5466647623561,-16.1441638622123));
#465=CARTESIAN_POINT('',(10.6786273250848,82.1254934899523,-16.4170496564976));
#466=CARTESIAN_POINT('',(10.6710565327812,81.9129220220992,-16.550889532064));
#467=CARTESIAN_POINT('',(10.6644224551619,81.4846459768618,-16.814058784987));
#468=CARTESIAN_POINT('',(10.6653663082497,81.2689389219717,-16.9433842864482));
#469=CARTESIAN_POINT('',(10.6749670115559,80.8352423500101,-17.1978874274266));
#470=CARTESIAN_POINT('',(10.683624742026,80.6172525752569,-17.3230645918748));
#471=CARTESIAN_POINT('',(10.7080782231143,80.1789194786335,-17.5699535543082));
#472=CARTESIAN_POINT('',(10.7238938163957,79.9585712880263,-17.6916547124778));
#473=CARTESIAN_POINT('',(10.7622068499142,79.5165128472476,-17.9314908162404));
#474=CARTESIAN_POINT('',(10.7847047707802,79.2948025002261,-18.0496255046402));
#475=CARTESIAN_POINT('',(10.8616544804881,78.6282451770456,-18.3989144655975));
#476=CARTESIAN_POINT('',(10.9255713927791,78.181816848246,-18.6250403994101));
#477=CARTESIAN_POINT('',(11.0664102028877,77.3479438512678,-19.0346218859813));
#478=CARTESIAN_POINT('',(11.1403619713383,76.9607742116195,-19.2196861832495));
#479=CARTESIAN_POINT('',(11.3050181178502,76.1856258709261,-19.580557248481));
#480=CARTESIAN_POINT('',(11.3957241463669,75.7976470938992,-19.7563631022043));
#481=CARTESIAN_POINT('',(11.5935742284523,75.0216151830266,-20.0985507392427));
#482=CARTESIAN_POINT('',(11.7007221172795,74.6335620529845,-20.264930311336));
#483=CARTESIAN_POINT('',(11.9313879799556,73.8581881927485,-20.5877481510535));
#484=CARTESIAN_POINT('',(12.0549056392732,73.4708674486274,-20.7441866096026));
#485=CARTESIAN_POINT('',(12.3163714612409,72.7038997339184,-21.0439307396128));
#486=CARTESIAN_POINT('',(12.4540552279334,72.3242296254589,-21.1874073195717));
#487=CARTESIAN_POINT('',(12.7458005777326,71.5671030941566,-21.4629534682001));
#488=CARTESIAN_POINT('',(12.8998598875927,71.1896463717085,-21.5950246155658));
#489=CARTESIAN_POINT('',(13.2250025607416,70.4376533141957,-21.8464430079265));
#490=CARTESIAN_POINT('',(13.3960903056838,70.0631177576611,-21.9657869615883));
#491=CARTESIAN_POINT('',(13.666071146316,69.5043911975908,-22.1338540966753));
#492=CARTESIAN_POINT('',(13.7583155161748,69.3186135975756,-22.1880644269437));
#493=CARTESIAN_POINT('',(13.9473861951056,68.948260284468,-22.2925349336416));
#494=CARTESIAN_POINT('',(14.0442129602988,68.7636846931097,-22.3427947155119));
#495=CARTESIAN_POINT('',(14.1433933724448,68.5798,-22.3909303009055));
#496=B_SPLINE_CURVE_WITH_KNOTS('',3,(#390,#391,#392,#393,#394,#395,#396,#397,#398,#399,#400,
#401,#402,#403,#404,#405,#406,#407,#408,#409,#410,#411,#412,#413,#414,#415,#416,#417,#418,#419,
#420,#421,#422,#423,#424,#425,#426,#427,#428,#429,#430,#431,#432,#433,#434,#435,#436,#437,#438,
#439,#440,#441,#442,#443,#444,#445,#446,#447,#448,#449,#450,#451,#452,#453,#454,#455,#456,#457,
#458,#459,#460,#461,#462,#463,#464,#465,#466,#467,#468,#469,#470,#471,#472,#473,#474,#475,#476,
#477,#478,#479,#480,#481,#482,#483,#484,#485,#486,#487,#488,#489,#490,#491,#492,#493,#494,#495),
.UNSPECIFIED.,.F.,.F.,(4,2,2,2,2,2,2,2,2,2,2,2,2,2,2,2,2,2,2,2,2,2,2,2,2,2,2,2,2,2,2,2,2,2,2,2,
2,2,2,2,2,2,2,2,2,2,2,2,2,2,2,2,4),(0.,0.542840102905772,1.08564511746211,2.17085376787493,
3.25525867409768,4.33976732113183,5.4305221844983,6.5212985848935,7.61215354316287,
8.70297647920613,10.3650975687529,11.196398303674,12.027641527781,12.85858662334,
13.6894562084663,14.5197908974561,15.3499881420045,16.1821952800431,17.0148549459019,
17.8469149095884,18.2625409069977,18.6780732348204,19.0990950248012,19.5203342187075,
20.3547558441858,20.7529146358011,21.150746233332,21.5511837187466,21.9517126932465,
22.3233446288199,22.6951557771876,23.338172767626,23.9834677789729,24.6186994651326,
25.2545758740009,25.8919145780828,26.5290325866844,27.2825500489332,28.0362555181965,
28.7905929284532,29.5450164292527,30.3015442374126,31.0581264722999,32.5707579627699,
33.876714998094,35.1828007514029,36.4891916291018,37.7955574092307,39.0808873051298,
40.366039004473,41.6515222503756,42.2946005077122,42.9377429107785),.UNSPECIFIED.);
#497=CARTESIAN_POINT('',(14.1432854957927,68.58,-22.3908779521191));
#498=VERTEX_POINT('',#497);
#499=EDGE_CURVE('E868',#387,#498,#496,.T.);
#500=ORIENTED_EDGE('',*,*,#499,.T.);
#501=CARTESIAN_POINT('',(15.70457419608,68.58,-21.3248748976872));
#502=VERTEX_POINT('',#501);
#503=EDGE_CURVE('E865',#498,#502,#385,.F.);
#504=ORIENTED_EDGE('',*,*,#503,.T.);
#505=CARTESIAN_POINT('',(19.6011992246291,62.2298,-22.3373805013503));
#506=CARTESIAN_POINT('',(19.28325195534,62.7634166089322,-22.2547645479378));
#507=CARTESIAN_POINT('',(18.9638646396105,63.29612059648,-22.1717744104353));
#508=CARTESIAN_POINT('',(18.3218531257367,64.3594037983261,-22.0049530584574));
#509=CARTESIAN_POINT('',(17.9992290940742,64.8899831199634,-21.9211218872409));
#510=CARTESIAN_POINT('',(17.350351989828,65.9487768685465,-21.752516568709));
#511=CARTESIAN_POINT('',(17.0240988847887,66.4769912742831,-21.6677424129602));
#512=CARTESIAN_POINT('',(16.3674755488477,67.5307185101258,-21.4971243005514));
#513=CARTESIAN_POINT('',(16.0371051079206,68.0562312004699,-21.4112802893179));
#514=CARTESIAN_POINT('',(15.7044472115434,68.5802,-21.3248419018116));
#515=B_SPLINE_CURVE_WITH_KNOTS('',3,(#505,#506,#507,#508,#509,#510,#511,#512,#513,#514),
.UNSPECIFIED.,.F.,.F.,(4,2,2,2,4),(0.,1.87988537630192,3.75967455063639,5.63948054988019,
7.51938283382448),.UNSPECIFIED.);
#516=CARTESIAN_POINT('',(19.6010800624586,62.23,-22.3373495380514));
#517=VERTEX_POINT('',#516);
#518=EDGE_CURVE('E765',#517,#502,#515,.T.);
#519=ORIENTED_EDGE('',*,*,#518,.F.);
#520=CARTESIAN_POINT('',(-19.6010800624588,62.23,-22.3373495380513));
#521=VERTEX_POINT('',#520);
#522=EDGE_CURVE('E829',#521,#517,#45,.T.);
#523=ORIENTED_EDGE('',*,*,#522,.F.);
#524=CARTESIAN_POINT('',(-15.7044472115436,68.5802,-21.3248419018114));
#525=CARTESIAN_POINT('',(-16.0371051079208,68.0562312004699,-21.4112802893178));
#526=CARTESIAN_POINT('',(-16.3674755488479,67.5307185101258,-21.4971243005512));
#527=CARTESIAN_POINT('',(-17.0240988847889,66.4769912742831,-21.6677424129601));
#528=CARTESIAN_POINT('',(-17.3503519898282,65.9487768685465,-21.7525165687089));
#529=CARTESIAN_POINT('',(-17.9992290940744,64.8899831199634,-21.9211218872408));
#530=CARTESIAN_POINT('',(-18.3218531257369,64.3594037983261,-22.0049530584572));
#531=CARTESIAN_POINT('',(-18.9638646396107,63.29612059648,-22.1717744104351));
#532=CARTESIAN_POINT('',(-19.2832519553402,62.7634166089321,-22.2547645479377));
#533=CARTESIAN_POINT('',(-19.6011992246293,62.2298,-22.3373805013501));
#534=B_SPLINE_CURVE_WITH_KNOTS('',3,(#524,#525,#526,#527,#528,#529,#530,#531,#532,#533),
.UNSPECIFIED.,.F.,.F.,(4,2,2,2,4),(0.,1.87990228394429,3.75970828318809,5.63949745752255,
7.51938283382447),.UNSPECIFIED.);
#535=CARTESIAN_POINT('',(-15.7045741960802,68.58,-21.3248748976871));
#536=VERTEX_POINT('',#535);
#537=EDGE_CURVE('E611',#536,#521,#534,.T.);
#538=ORIENTED_EDGE('',*,*,#537,.F.);
#539=CARTESIAN_POINT('',(0.,68.58,0.));
#540=DIRECTION('',(0.,1.,0.));
#541=DIRECTION('',(0.,0.,1.));
#542=AXIS2_PLACEMENT_3D('',#539,#540,#541);
#543=CIRCLE('',#542,26.4836542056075);
#544=CARTESIAN_POINT('',(-14.1432854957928,68.58,-22.390877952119));
#545=VERTEX_POINT('',#544);
#546=EDGE_CURVE('E1223',#536,#545,#543,.F.);
#547=ORIENTED_EDGE('',*,*,#546,.T.);
#548=CARTESIAN_POINT('',(-14.1433933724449,68.5798000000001,-22.3909303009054));
#549=CARTESIAN_POINT('',(-14.0596815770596,68.7350022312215,-22.350304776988));
#550=CARTESIAN_POINT('',(-13.9776470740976,68.8906992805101,-22.3081630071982));
#551=CARTESIAN_POINT('',(-13.8168553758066,69.2029732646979,-22.2210302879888));
#552=CARTESIAN_POINT('',(-13.7380979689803,69.3595501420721,-22.1760395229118));
#553=CARTESIAN_POINT('',(-13.5066666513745,69.8303500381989,-22.0370947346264));
#554=CARTESIAN_POINT('',(-13.3587718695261,70.1457572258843,-21.9391379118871));
#555=CARTESIAN_POINT('',(-13.0753567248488,70.7787217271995,-21.7338262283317));
#556=CARTESIAN_POINT('',(-12.9398272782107,71.0962772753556,-21.6264783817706));
#557=CARTESIAN_POINT('',(-12.680604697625,71.7332404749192,-21.4032338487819));
#558=CARTESIAN_POINT('',(-12.5569126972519,72.0526483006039,-21.2873363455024));
#559=CARTESIAN_POINT('',(-12.3204109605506,72.6946343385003,-21.0470421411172));
#560=CARTESIAN_POINT('',(-12.207668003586,73.017220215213,-20.9226003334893));
#561=CARTESIAN_POINT('',(-11.9936819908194,73.6632945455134,-20.6663853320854));
#562=CARTESIAN_POINT('',(-11.8924391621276,73.9867830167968,-20.5346119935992));
#563=CARTESIAN_POINT('',(-11.7013595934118,74.6342665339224,-20.2641447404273));
#564=CARTESIAN_POINT('',(-11.6115236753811,74.9582616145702,-20.1254503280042));
#565=CARTESIAN_POINT('',(-11.4433041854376,75.6062899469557,-19.8414364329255));
#566=CARTESIAN_POINT('',(-11.3649202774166,75.9303231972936,-19.6961171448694));
#567=CARTESIAN_POINT('',(-11.1817059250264,76.7476954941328,-19.3211632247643));
#568=CARTESIAN_POINT('',(-11.0845248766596,77.2408247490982,-19.0872302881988));
#569=CARTESIAN_POINT('',(-10.9599064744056,77.9784605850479,-18.7249280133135));
#570=CARTESIAN_POINT('',(-10.9218885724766,78.2240315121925,-18.6022415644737));
#571=CARTESIAN_POINT('',(-10.8531925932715,78.7141977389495,-18.3529388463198));
#572=CARTESIAN_POINT('',(-10.8225140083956,78.9587931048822,-18.2263228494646));
#573=CARTESIAN_POINT('',(-10.7688733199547,79.4465771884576,-17.9690231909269));
#574=CARTESIAN_POINT('',(-10.7459084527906,79.6897663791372,-17.8383410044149));
#575=CARTESIAN_POINT('',(-10.7081842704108,80.1743656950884,-17.5726008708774));
#576=CARTESIAN_POINT('',(-10.693424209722,80.4157759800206,-17.4375433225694));
#577=CARTESIAN_POINT('',(-10.6727907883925,80.8961071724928,-17.1627429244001));
#578=CARTESIAN_POINT('',(-10.666911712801,81.1350295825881,-17.0230031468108));
#579=CARTESIAN_POINT('',(-10.6649433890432,81.6097183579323,-16.7382475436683));
#580=CARTESIAN_POINT('',(-10.6688525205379,81.8454852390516,-16.5932325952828));
#581=CARTESIAN_POINT('',(-10.6877509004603,82.3133650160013,-16.2968182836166));
#582=CARTESIAN_POINT('',(-10.7027669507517,82.5454676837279,-16.1454043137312));
#583=CARTESIAN_POINT('',(-10.7457309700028,83.0038758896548,-15.8354539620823));
#584=CARTESIAN_POINT('',(-10.7736859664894,83.2301782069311,-15.676913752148));
#585=CARTESIAN_POINT('',(-10.8451251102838,83.6741617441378,-15.351527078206));
#586=CARTESIAN_POINT('',(-10.8885980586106,83.8918490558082,-15.1846866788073));
#587=CARTESIAN_POINT('',(-10.9683843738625,84.2084557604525,-14.9269806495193));
#588=CARTESIAN_POINT('',(-10.9973916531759,84.3122892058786,-14.8398818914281));
#589=CARTESIAN_POINT('',(-11.0609509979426,84.5158080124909,-14.662930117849));
#590=CARTESIAN_POINT('',(-11.0955018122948,84.6154943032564,-14.5730777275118));
#591=CARTESIAN_POINT('',(-11.1714874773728,84.8109037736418,-14.3891167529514));
#592=CARTESIAN_POINT('',(-11.2130072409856,84.90655720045,-14.2949676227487));
#593=CARTESIAN_POINT('',(-11.3035808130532,85.0907355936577,-14.1034347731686));
#594=CARTESIAN_POINT('',(-11.352638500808,85.1792568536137,-14.0060494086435));
#595=CARTESIAN_POINT('',(-11.512340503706,85.429646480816,-13.7101223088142));
#596=CARTESIAN_POINT('',(-11.636194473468,85.5782916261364,-13.5060546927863));
#597=CARTESIAN_POINT('',(-11.8507095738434,85.7493306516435,-13.1996116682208));
#598=CARTESIAN_POINT('',(-11.924869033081,85.7971000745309,-13.0998509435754));
#599=CARTESIAN_POINT('',(-12.0829789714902,85.873763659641,-12.9007063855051));
#600=CARTESIAN_POINT('',(-12.1669213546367,85.9026733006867,-12.8013223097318));
#601=CARTESIAN_POINT('',(-12.3437610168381,85.9385908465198,-12.6053038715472));
#602=CARTESIAN_POINT('',(-12.4367133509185,85.9454540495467,-12.5086917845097));
#603=CARTESIAN_POINT('',(-12.6281475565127,85.9359739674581,-12.322316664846));
#604=CARTESIAN_POINT('',(-12.7266306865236,85.9196253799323,-12.2325552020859));
#605=CARTESIAN_POINT('',(-12.9184346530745,85.8677160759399,-12.0684910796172));
#606=CARTESIAN_POINT('',(-13.0116153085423,85.8336265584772,-11.9935403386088));
#607=CARTESIAN_POINT('',(-13.1975950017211,85.7502029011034,-11.8522698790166));
#608=CARTESIAN_POINT('',(-13.2903938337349,85.7008614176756,-11.7859543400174));
#609=CARTESIAN_POINT('',(-13.5413620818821,85.5496530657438,-11.61636622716));
#610=CARTESIAN_POINT('',(-13.697840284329,85.4357254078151,-11.5214197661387));
#611=CARTESIAN_POINT('',(-14.0032728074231,85.1845941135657,-11.3524385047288));
#612=CARTESIAN_POINT('',(-14.1521985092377,85.0473094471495,-11.2784789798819));
#613=CARTESIAN_POINT('',(-14.4401544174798,84.7600134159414,-11.1484302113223));
#614=CARTESIAN_POINT('',(-14.5793027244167,84.6102339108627,-11.0920802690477));
#615=CARTESIAN_POINT('',(-14.8511494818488,84.3006741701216,-10.9925096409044));
#616=CARTESIAN_POINT('',(-14.9838412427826,84.140883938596,-10.9493023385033));
#617=CARTESIAN_POINT('',(-15.2438249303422,83.8139640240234,-10.8736636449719));
#618=CARTESIAN_POINT('',(-15.371103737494,83.6468183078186,-10.8412572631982));
#619=CARTESIAN_POINT('',(-15.6206584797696,83.3074809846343,-10.7856662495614));
#620=CARTESIAN_POINT('',(-15.7429361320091,83.1352911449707,-10.762478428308));
#621=CARTESIAN_POINT('',(-16.0051192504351,82.7552655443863,-10.7205377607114));
#622=CARTESIAN_POINT('',(-16.1441638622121,82.5466647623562,-10.7033691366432));
#623=CARTESIAN_POINT('',(-16.4170496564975,82.1254934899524,-10.678627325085));
#624=CARTESIAN_POINT('',(-16.5508895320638,81.9129220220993,-10.6710565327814));
#625=CARTESIAN_POINT('',(-16.8140587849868,81.4846459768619,-10.664422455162));
#626=CARTESIAN_POINT('',(-16.943384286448,81.2689389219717,-10.6653663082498));
#627=CARTESIAN_POINT('',(-17.1978874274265,80.8352423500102,-10.674967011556));
#628=CARTESIAN_POINT('',(-17.3230645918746,80.6172525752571,-10.6836247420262));
#629=CARTESIAN_POINT('',(-17.5699535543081,80.1789194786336,-10.7080782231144));
#630=CARTESIAN_POINT('',(-17.6916547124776,79.9585712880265,-10.7238938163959));
#631=CARTESIAN_POINT('',(-17.9314908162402,79.5165128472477,-10.7622068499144));
#632=CARTESIAN_POINT('',(-18.04962550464,79.2948025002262,-10.7847047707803));
#633=CARTESIAN_POINT('',(-18.3989144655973,78.6282451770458,-10.8616544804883));
#634=CARTESIAN_POINT('',(-18.62504039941,78.1818168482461,-10.9255713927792));
#635=CARTESIAN_POINT('',(-19.0346218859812,77.3479438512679,-11.0664102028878));
#636=CARTESIAN_POINT('',(-19.2196861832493,76.9607742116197,-11.1403619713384));
#637=CARTESIAN_POINT('',(-19.5805572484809,76.1856258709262,-11.3050181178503));
#638=CARTESIAN_POINT('',(-19.7563631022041,75.7976470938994,-11.3957241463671));
#639=CARTESIAN_POINT('',(-20.0985507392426,75.0216151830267,-11.5935742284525));
#640=CARTESIAN_POINT('',(-20.2649303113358,74.6335620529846,-11.7007221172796));
#641=CARTESIAN_POINT('',(-20.5877481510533,73.8581881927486,-11.9313879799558));
#642=CARTESIAN_POINT('',(-20.7441866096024,73.4708674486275,-12.0549056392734));
#643=CARTESIAN_POINT('',(-21.0439307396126,72.7038997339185,-12.3163714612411));
#644=CARTESIAN_POINT('',(-21.1874073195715,72.324229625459,-12.4540552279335));
#645=CARTESIAN_POINT('',(-21.4629534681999,71.5671030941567,-12.7458005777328));
#646=CARTESIAN_POINT('',(-21.5950246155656,71.1896463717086,-12.8998598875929));
#647=CARTESIAN_POINT('',(-21.8464430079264,70.4376533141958,-13.2250025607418));
#648=CARTESIAN_POINT('',(-21.9657869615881,70.0631177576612,-13.396090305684));
#649=CARTESIAN_POINT('',(-22.1338540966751,69.5043911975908,-13.6660711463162));
#650=CARTESIAN_POINT('',(-22.1880644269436,69.3186135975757,-13.7583155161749));
#651=CARTESIAN_POINT('',(-22.2925349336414,68.9482602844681,-13.9473861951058));
#652=CARTESIAN_POINT('',(-22.3427947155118,68.7636846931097,-14.044212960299));
#653=CARTESIAN_POINT('',(-22.3909303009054,68.5798000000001,-14.143393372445));
#654=B_SPLINE_CURVE_WITH_KNOTS('',3,(#548,#549,#550,#551,#552,#553,#554,#555,#556,#557,#558,
#559,#560,#561,#562,#563,#564,#565,#566,#567,#568,#569,#570,#571,#572,#573,#574,#575,#576,#577,
#578,#579,#580,#581,#582,#583,#584,#585,#586,#587,#588,#589,#590,#591,#592,#593,#594,#595,#596,
#597,#598,#599,#600,#601,#602,#603,#604,#605,#606,#607,#608,#609,#610,#611,#612,#613,#614,#615,
#616,#617,#618,#619,#620,#621,#622,#623,#624,#625,#626,#627,#628,#629,#630,#631,#632,#633,#634,
#635,#636,#637,#638,#639,#640,#641,#642,#643,#644,#645,#646,#647,#648,#649,#650,#651,#652,#653),
.UNSPECIFIED.,.F.,.F.,(4,2,2,2,2,2,2,2,2,2,2,2,2,2,2,2,2,2,2,2,2,2,2,2,2,2,2,2,2,2,2,2,2,2,2,2,
2,2,2,2,2,2,2,2,2,2,2,2,2,2,2,2,4),(0.,0.542840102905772,1.08564511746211,2.17085376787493,
3.25525867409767,4.33976732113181,5.43052218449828,6.52129858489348,7.61215354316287,
8.70297647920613,10.3650975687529,11.196398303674,12.027641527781,12.85858662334,
13.6894562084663,14.5197908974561,15.3499881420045,16.1821952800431,17.0148549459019,
17.8469149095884,18.2625409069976,18.6780732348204,19.0990950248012,19.5203342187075,
20.3547558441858,20.7529146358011,21.150746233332,21.5511837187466,21.9517126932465,
22.3233446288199,22.6951557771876,23.338172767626,23.9834677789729,24.6186994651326,
25.2545758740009,25.8919145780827,26.5290325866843,27.2825500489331,28.0362555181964,
28.7905929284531,29.5450164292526,30.3015442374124,31.0581264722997,32.5707579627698,
33.8767149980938,35.1828007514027,36.4891916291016,37.7955574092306,39.0808873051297,
40.3660390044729,41.6515222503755,42.294600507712,42.9377429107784),.UNSPECIFIED.);
#655=CARTESIAN_POINT('',(-22.3908779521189,68.58,-14.1432854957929));
#656=VERTEX_POINT('',#655);
#657=EDGE_CURVE('E995',#545,#656,#654,.T.);
#658=ORIENTED_EDGE('',*,*,#657,.T.);
#659=EDGE_CURVE('E953',#656,#38,#543,.F.);
#660=ORIENTED_EDGE('',*,*,#659,.T.);
#661=EDGE_LOOP('',(#40,#49,#64,#73,#184,#188,#203,#207,#222,#231,#342,#346,#361,#365,#380,#389,
#500,#504,#519,#523,#538,#547,#658,#660));
#662=FACE_BOUND('',#661,.T.);
#663=CARTESIAN_POINT('',(0.,89.408,0.));
#664=DIRECTION('',(0.,-1.,0.));
#665=DIRECTION('',(0.,0.,-1.));
#666=AXIS2_PLACEMENT_3D('',#663,#664,#665);
#667=CIRCLE('',#666,15.875);
#668=CARTESIAN_POINT('',(0.,89.408,-15.875));
#669=VERTEX_POINT('',#668);
#670=EDGE_CURVE('E826',#669,#669,#667,.T.);
#671=ORIENTED_EDGE('',*,*,#670,.T.);
#672=EDGE_LOOP('',(#671));
#673=FACE_BOUND('',#672,.T.);
#674=ADVANCED_FACE('F31',(#662,#673),#23,.T.);
#675=CARTESIAN_POINT('',(0.,105.41,0.));
#676=DIRECTION('',(0.,-1.,0.));
#677=DIRECTION('',(0.,0.,-1.));
#678=AXIS2_PLACEMENT_3D('',#675,#676,#677);
#679=CYLINDRICAL_SURFACE('',#678,29.718);
#680=CARTESIAN_POINT('',(-7.88572135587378,20.1806746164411,-28.6526599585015));
#681=CARTESIAN_POINT('',(-7.68382389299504,19.9596806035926,-28.7082256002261));
#682=CARTESIAN_POINT('',(-7.47269853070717,19.7471847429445,-28.7640339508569));
#683=CARTESIAN_POINT('',(-7.03324933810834,19.3404998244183,-28.8746299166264));
#684=CARTESIAN_POINT('',(-6.80492583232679,19.1463104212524,-28.9294175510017));
#685=CARTESIAN_POINT('',(-6.33242905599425,18.777517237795,-29.0365034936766));
#686=CARTESIAN_POINT('',(-6.08825616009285,18.6029129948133,-29.0888018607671));
#687=CARTESIAN_POINT('',(-5.58561094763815,18.2745876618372,-29.1894867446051));
#688=CARTESIAN_POINT('',(-5.32714395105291,18.1208588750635,-29.2378747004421));
#689=CARTESIAN_POINT('',(-4.79677760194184,17.8350471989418,-29.3295591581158));
#690=CARTESIAN_POINT('',(-4.52484631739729,17.7030193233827,-29.3728426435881));
#691=CARTESIAN_POINT('',(-3.96995216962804,17.4622070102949,-29.4529722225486));
#692=CARTESIAN_POINT('',(-3.68698927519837,17.3534226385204,-29.4898182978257));
#693=CARTESIAN_POINT('',(-3.11210523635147,17.160137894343,-29.5560148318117));
#694=CARTESIAN_POINT('',(-2.82018635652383,17.0756314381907,-29.5853671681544));
#695=CARTESIAN_POINT('',(-2.22952055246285,16.9317191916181,-29.6357317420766));
#696=CARTESIAN_POINT('',(-1.9307739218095,16.8723123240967,-29.656744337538));
#697=CARTESIAN_POINT('',(-1.3412017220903,16.7811437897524,-29.6891268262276));
#698=CARTESIAN_POINT('',(-1.05055601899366,16.7483451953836,-29.7008579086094));
#699=CARTESIAN_POINT('',(-0.467335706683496,16.7067349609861,-29.7157567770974));
#700=CARTESIAN_POINT('',(-0.174761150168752,16.6979226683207,-29.7189247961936));
#701=CARTESIAN_POINT('',(0.41004235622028,16.704375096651,-29.7166095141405));
#702=CARTESIAN_POINT('',(0.702271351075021,16.7196362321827,-29.7111275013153));
#703=CARTESIAN_POINT('',(1.28420371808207,16.7740711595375,-29.6916671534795));
#704=CARTESIAN_POINT('',(1.57390712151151,16.8132446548,-29.6776889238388));
#705=CARTESIAN_POINT('',(2.13919140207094,16.9134334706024,-29.6422156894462));
#706=CARTESIAN_POINT('',(2.41492376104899,16.9736899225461,-29.6209823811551));
#707=CARTESIAN_POINT('',(2.96015073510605,17.1156505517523,-29.5714721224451));
#708=CARTESIAN_POINT('',(3.22964552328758,17.1973541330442,-29.5431953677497));
#709=CARTESIAN_POINT('',(3.76065640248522,17.3815029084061,-29.480306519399));
#710=CARTESIAN_POINT('',(4.02217317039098,17.4839463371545,-29.4456949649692));
#711=CARTESIAN_POINT('',(4.53576856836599,17.7088039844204,-29.3709670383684));
#712=CARTESIAN_POINT('',(4.78784357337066,17.8312257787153,-29.3308485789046));
#713=CARTESIAN_POINT('',(5.28869907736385,18.0992250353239,-29.2447559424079));
#714=CARTESIAN_POINT('',(5.53713260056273,18.2454048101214,-29.1986383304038));
#715=CARTESIAN_POINT('',(6.02097921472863,18.557015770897,-29.1027179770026));
#716=CARTESIAN_POINT('',(6.2563877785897,18.7224535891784,-29.0529139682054));
#717=CARTESIAN_POINT('',(6.71282674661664,19.0714751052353,-28.9508580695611));
#718=CARTESIAN_POINT('',(6.93385521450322,19.2550612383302,-28.8986058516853));
#719=CARTESIAN_POINT('',(7.36030670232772,19.6392438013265,-28.7929449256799));
#720=CARTESIAN_POINT('',(7.5657291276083,19.8398408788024,-28.7395361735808));
#721=CARTESIAN_POINT('',(7.97067536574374,20.268358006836,-28.6299536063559));
#722=CARTESIAN_POINT('',(8.16925514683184,20.497173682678,-28.5737890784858));
#723=CARTESIAN_POINT('',(8.54647314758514,20.9709666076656,-28.4632385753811));
#724=CARTESIAN_POINT('',(8.72511781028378,21.215938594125,-28.4088520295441));
#725=CARTESIAN_POINT('',(9.06141502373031,21.7207387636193,-28.3033807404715));
#726=CARTESIAN_POINT('',(9.21905802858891,21.9805736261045,-28.2522975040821));
#727=CARTESIAN_POINT('',(9.51203054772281,22.5132692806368,-28.1550106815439));
#728=CARTESIAN_POINT('',(9.64736940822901,22.7861245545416,-28.1088050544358));
#729=CARTESIAN_POINT('',(9.89492922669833,23.3436771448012,-28.0226180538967));
#730=CARTESIAN_POINT('',(10.0071089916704,23.628394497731,-27.9826478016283));
#731=CARTESIAN_POINT('',(10.2070340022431,24.2072397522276,-27.9103438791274));
#732=CARTESIAN_POINT('',(10.2947790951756,24.5013677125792,-27.8780102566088));
#733=CARTESIAN_POINT('',(10.4449278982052,25.0967074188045,-27.8221032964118));
#734=CARTESIAN_POINT('',(10.5073428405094,25.3979159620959,-27.7985260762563));
#735=CARTESIAN_POINT('',(10.6062143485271,26.0051497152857,-27.7609537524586));
#736=CARTESIAN_POINT('',(10.6426724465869,26.3111746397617,-27.7469580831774));
#737=CARTESIAN_POINT('',(10.6878833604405,26.9077987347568,-27.7295728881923));
#738=CARTESIAN_POINT('',(10.6981116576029,27.1982705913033,-27.7256186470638));
#739=CARTESIAN_POINT('',(10.6950544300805,27.779065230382,-27.7267982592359));
#740=CARTESIAN_POINT('',(10.6817698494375,28.0693880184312,-27.7319317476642));
#741=CARTESIAN_POINT('',(10.6318258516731,28.6476949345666,-27.7511173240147));
#742=CARTESIAN_POINT('',(10.595167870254,28.9356792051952,-27.7651688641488));
#743=CARTESIAN_POINT('',(10.4988445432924,29.5072240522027,-27.8017343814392));
#744=CARTESIAN_POINT('',(10.4391791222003,29.7907846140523,-27.8242483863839));
#745=CARTESIAN_POINT('',(10.2990146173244,30.3451405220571,-27.8764286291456));
#746=CARTESIAN_POINT('',(10.2190176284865,30.6160795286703,-27.9059214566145));
#747=CARTESIAN_POINT('',(10.0382325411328,31.1502140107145,-27.9714613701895));
#748=CARTESIAN_POINT('',(9.93743710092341,31.4134067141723,-28.007510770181));
#749=CARTESIAN_POINT('',(9.71585659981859,31.9303771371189,-28.0851459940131));
#750=CARTESIAN_POINT('',(9.59507188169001,32.1841550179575,-28.1267317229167));
#751=CARTESIAN_POINT('',(9.33435871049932,32.6808938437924,-28.2143257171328));
#752=CARTESIAN_POINT('',(9.19442885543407,32.923853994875,-28.2603343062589));
#753=CARTESIAN_POINT('',(8.8889503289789,33.4093711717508,-28.3579450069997));
#754=CARTESIAN_POINT('',(8.7224766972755,33.6513135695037,-28.4097112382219));
#755=CARTESIAN_POINT('',(8.37051989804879,34.1204516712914,-28.5153936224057));
#756=CARTESIAN_POINT('',(8.18503622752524,34.3476469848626,-28.5693098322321));
#757=CARTESIAN_POINT('',(7.79612188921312,34.7860548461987,-28.6778794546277));
#758=CARTESIAN_POINT('',(7.59268593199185,34.9972626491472,-28.7325330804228));
#759=CARTESIAN_POINT('',(7.16909169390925,35.4023722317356,-28.8411416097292));
#760=CARTESIAN_POINT('',(6.94893363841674,35.5962742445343,-28.8950965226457));
#761=CARTESIAN_POINT('',(6.48318117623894,35.9736350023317,-29.003232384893));
#762=CARTESIAN_POINT('',(6.23689612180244,36.156269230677,-29.057320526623));
#763=CARTESIAN_POINT('',(5.72908976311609,36.4999802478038,-29.1616907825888));
#764=CARTESIAN_POINT('',(5.46757429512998,36.6610652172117,-29.2119743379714));
#765=CARTESIAN_POINT('',(4.93089207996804,36.9604844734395,-29.307338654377));
#766=CARTESIAN_POINT('',(4.65572459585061,37.0988175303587,-29.3524191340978));
#767=CARTESIAN_POINT('',(4.09363790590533,37.3515039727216,-29.4360725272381));
#768=CARTESIAN_POINT('',(3.80671919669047,37.4658583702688,-29.4746457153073));
#769=CARTESIAN_POINT('',(3.2313188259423,37.6666687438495,-29.5431836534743));
#770=CARTESIAN_POINT('',(2.94310173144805,37.7538111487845,-29.5733576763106));
#771=CARTESIAN_POINT('',(2.3596343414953,37.9035479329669,-29.6256210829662));
#772=CARTESIAN_POINT('',(2.06438414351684,37.9661426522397,-29.647710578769));
#773=CARTESIAN_POINT('',(1.46922431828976,38.0661168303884,-29.6831558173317));
#774=CARTESIAN_POINT('',(1.16931627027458,38.103504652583,-29.6965144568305));
#775=CARTESIAN_POINT('',(0.567147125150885,38.1526914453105,-29.7141141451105));
#776=CARTESIAN_POINT('',(0.264886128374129,38.1644915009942,-29.718355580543));
#777=CARTESIAN_POINT('',(-0.323072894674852,38.1624354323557,-29.7176181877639));
#778=CARTESIAN_POINT('',(-0.608777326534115,38.1499402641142,-29.7131284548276));
#779=CARTESIAN_POINT('',(-1.17800870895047,38.1020852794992,-29.696007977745));
#780=CARTESIAN_POINT('',(-1.46153574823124,38.0667263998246,-29.6833775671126));
#781=CARTESIAN_POINT('',(-2.02438626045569,37.9734880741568,-29.6503096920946));
#782=CARTESIAN_POINT('',(-2.3037098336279,37.9156091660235,-29.6298724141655));
#783=CARTESIAN_POINT('',(-2.85623975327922,37.7778690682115,-29.5817228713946));
#784=CARTESIAN_POINT('',(-3.12944600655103,37.6980075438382,-29.5540104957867));
#785=CARTESIAN_POINT('',(-3.6671425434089,37.5172743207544,-29.4921111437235));
#786=CARTESIAN_POINT('',(-3.93165623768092,37.4164655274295,-29.4579435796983));
#787=CARTESIAN_POINT('',(-4.45127239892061,37.1944787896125,-29.383917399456));
#788=CARTESIAN_POINT('',(-4.70637146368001,37.073293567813,-29.3440567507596));
#789=CARTESIAN_POINT('',(-5.20557115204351,36.811493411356,-29.2596247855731));
#790=CARTESIAN_POINT('',(-5.44967186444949,36.6708786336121,-29.2150535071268));
#791=CARTESIAN_POINT('',(-5.92554436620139,36.3711843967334,-29.1222634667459));
#792=CARTESIAN_POINT('',(-6.1573152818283,36.2121036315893,-29.0740444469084));
#793=CARTESIAN_POINT('',(-6.61889286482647,35.8678372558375,-28.9725466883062));
#794=CARTESIAN_POINT('',(-6.84798245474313,35.6817287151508,-28.9191352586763));
#795=CARTESIAN_POINT('',(-7.28984652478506,35.2914248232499,-28.8109252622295));
#796=CARTESIAN_POINT('',(-7.50262053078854,35.0872289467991,-28.7561266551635));
#797=CARTESIAN_POINT('',(-7.91069397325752,34.6619263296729,-28.6465547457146));
#798=CARTESIAN_POINT('',(-8.10598778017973,34.4408141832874,-28.5917814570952));
#799=CARTESIAN_POINT('',(-8.47785510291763,33.9830370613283,-28.4837321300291));
#800=CARTESIAN_POINT('',(-8.65442897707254,33.7463723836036,-28.4304560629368));
#801=CARTESIAN_POINT('',(-8.99410941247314,33.2495365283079,-28.3248717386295));
#802=CARTESIAN_POINT('',(-9.15644488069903,32.9888129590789,-28.2726780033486));
#803=CARTESIAN_POINT('',(-9.45846967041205,32.4538225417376,-28.173075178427));
#804=CARTESIAN_POINT('',(-9.59816783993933,32.1795610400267,-28.1256642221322));
#805=CARTESIAN_POINT('',(-9.85384323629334,31.6192220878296,-28.0371113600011));
#806=CARTESIAN_POINT('',(-9.96982139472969,31.3331451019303,-27.995969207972));
#807=CARTESIAN_POINT('',(-10.1770009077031,30.75118794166,-27.921323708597));
#808=CARTESIAN_POINT('',(-10.2682034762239,30.4553082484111,-27.8878199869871));
#809=CARTESIAN_POINT('',(-10.4222816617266,29.8660736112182,-27.8305964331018));
#810=CARTESIAN_POINT('',(-10.4860081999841,29.5729695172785,-27.8065849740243));
#811=CARTESIAN_POINT('',(-10.5888347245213,28.98187543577,-27.7675915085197));
#812=CARTESIAN_POINT('',(-10.6279352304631,28.6838855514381,-27.7526093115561));
#813=CARTESIAN_POINT('',(-10.6810824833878,28.0854636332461,-27.7321981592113));
#814=CARTESIAN_POINT('',(-10.6951384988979,27.7850325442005,-27.7267656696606));
#815=CARTESIAN_POINT('',(-10.6980695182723,27.1840337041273,-27.7256350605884));
#816=CARTESIAN_POINT('',(-10.6869453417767,26.8834659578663,-27.7299366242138));
#817=CARTESIAN_POINT('',(-10.6409144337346,26.3007006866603,-27.7476308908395));
#818=CARTESIAN_POINT('',(-10.6073167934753,26.0183833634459,-27.7605230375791));
#819=CARTESIAN_POINT('',(-10.5180141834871,25.4577837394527,-27.7944811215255));
#820=CARTESIAN_POINT('',(-10.4623103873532,25.1795012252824,-27.8155466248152));
#821=CARTESIAN_POINT('',(-10.3292852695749,24.6287586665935,-27.8652188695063));
#822=CARTESIAN_POINT('',(-10.251957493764,24.3563003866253,-27.8938278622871));
#823=CARTESIAN_POINT('',(-10.0763500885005,23.8190175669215,-27.9577433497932));
#824=CARTESIAN_POINT('',(-9.9780684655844,23.5541937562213,-27.9930504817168));
#825=CARTESIAN_POINT('',(-9.75026994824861,23.0072472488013,-28.0732575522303));
#826=CARTESIAN_POINT('',(-9.61859025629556,22.726113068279,-28.118768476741));
#827=CARTESIAN_POINT('',(-9.33186191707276,22.1769933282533,-28.215221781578));
#828=CARTESIAN_POINT('',(-9.17681115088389,21.9090089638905,-28.2661646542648));
#829=CARTESIAN_POINT('',(-8.84453564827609,21.3879093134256,-28.3718892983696));
#830=CARTESIAN_POINT('',(-8.6673074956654,21.1347963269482,-28.4266716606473));
#831=CARTESIAN_POINT('',(-8.29189555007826,20.645004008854,-28.5384363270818));
#832=CARTESIAN_POINT('',(-8.09370475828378,20.4083302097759,-28.5954193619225));
#833=CARTESIAN_POINT('',(-7.88572135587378,20.1806746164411,-28.6526599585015));
#834=B_SPLINE_CURVE_WITH_KNOTS('',3,(#680,#681,#682,#683,#684,#685,#686,#687,#688,#689,#690,
#691,#692,#693,#694,#695,#696,#697,#698,#699,#700,#701,#702,#703,#704,#705,#706,#707,#708,#709,
#710,#711,#712,#713,#714,#715,#716,#717,#718,#719,#720,#721,#722,#723,#724,#725,#726,#727,#728,
#729,#730,#731,#732,#733,#734,#735,#736,#737,#738,#739,#740,#741,#742,#743,#744,#745,#746,#747,
#748,#749,#750,#751,#752,#753,#754,#755,#756,#757,#758,#759,#760,#761,#762,#763,#764,#765,#766,
#767,#768,#769,#770,#771,#772,#773,#774,#775,#776,#777,#778,#779,#780,#781,#782,#783,#784,#785,
#786,#787,#788,#789,#790,#791,#792,#793,#794,#795,#796,#797,#798,#799,#800,#801,#802,#803,#804,
#805,#806,#807,#808,#809,#810,#811,#812,#813,#814,#815,#816,#817,#818,#819,#820,#821,#822,#823,
#824,#825,#826,#827,#828,#829,#830,#831,#832,#833),.UNSPECIFIED.,.T.,.F.,(4,2,2,2,2,2,2,2,2,2,2,
2,2,2,2,2,2,2,2,2,2,2,2,2,2,2,2,2,2,2,2,2,2,2,2,2,2,2,2,2,2,2,2,2,2,2,2,2,2,2,2,2,2,2,2,2,2,2,2,
2,2,2,2,2,2,2,2,2,2,2,2,2,2,2,2,2,4),(0.,0.913076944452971,1.82613666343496,2.73917480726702,
3.65187539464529,4.56685521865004,5.48183763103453,6.39659055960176,7.31130422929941,
8.18838054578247,9.06543299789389,9.94235483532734,10.8192657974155,11.6674028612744,
12.5155163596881,13.3635576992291,14.2119213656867,15.0867007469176,15.9617822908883,
16.8369814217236,17.7122138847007,18.6355289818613,19.5585447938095,20.4819787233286,
21.4050247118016,22.3296986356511,23.25437833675,24.1786475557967,25.102862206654,
25.9738178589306,26.8447385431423,27.7156057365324,28.5864757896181,29.4376353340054,
30.2890958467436,31.1405417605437,31.9920500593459,32.8856857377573,33.7793450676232,
34.6732685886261,35.5671800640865,36.5000853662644,37.4326355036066,38.3652360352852,
39.2977971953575,40.2044664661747,41.1111231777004,42.0174789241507,42.9237962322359,
43.780803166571,44.6377749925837,45.4947263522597,46.3516907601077,47.2061179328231,
48.0608509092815,48.9155769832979,49.7703635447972,50.6692114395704,51.5680854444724,
52.4672479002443,53.3663931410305,54.2998516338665,55.2329443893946,56.1660004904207,
57.0990108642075,58.0005838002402,58.9021377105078,59.8033579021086,60.7045487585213,
61.5573496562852,62.410105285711,63.2631157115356,64.1162073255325,65.0562625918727,
65.9964031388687,66.936688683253,67.8772891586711),.UNSPECIFIED.);
#835=CARTESIAN_POINT('',(-7.88572135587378,20.1806746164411,-28.6526599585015));
#836=VERTEX_POINT('',#835);
#837=EDGE_CURVE('E11',#836,#836,#834,.T.);
#838=ORIENTED_EDGE('',*,*,#837,.T.);
#839=EDGE_LOOP('',(#838));
#840=FACE_BOUND('',#839,.T.);
#841=CARTESIAN_POINT('',(-7.88572135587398,20.1806746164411,28.6526599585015));
#842=CARTESIAN_POINT('',(-8.08648572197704,20.4004276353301,28.5974062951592));
#843=CARTESIAN_POINT('',(-8.27811717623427,20.6285746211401,28.5423948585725));
#844=CARTESIAN_POINT('',(-8.64194023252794,21.1003117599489,28.434352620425));
#845=CARTESIAN_POINT('',(-8.81413256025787,21.3439013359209,28.3813217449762));
#846=CARTESIAN_POINT('',(-9.13792475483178,21.8450652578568,28.2787323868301));
#847=CARTESIAN_POINT('',(-9.28952680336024,22.1026381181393,28.2291735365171));
#848=CARTESIAN_POINT('',(-9.57101117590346,22.6301382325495,28.1349835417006));
#849=CARTESIAN_POINT('',(-9.70090148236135,22.9000608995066,28.0903505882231));
#850=CARTESIAN_POINT('',(-9.93832306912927,23.4514054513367,28.0072336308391));
#851=CARTESIAN_POINT('',(-10.0457908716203,23.7328573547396,27.968767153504));
#852=CARTESIAN_POINT('',(-10.2369543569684,24.304637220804,27.8993663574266));
#853=CARTESIAN_POINT('',(-10.3206500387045,24.594965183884,27.8684320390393));
#854=CARTESIAN_POINT('',(-10.4634341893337,25.1822975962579,27.8151376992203));
#855=CARTESIAN_POINT('',(-10.5225300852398,25.479300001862,27.7927750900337));
#856=CARTESIAN_POINT('',(-10.6155309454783,26.0777709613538,27.7573866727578));
#857=CARTESIAN_POINT('',(-10.6494370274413,26.3792393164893,27.7443604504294));
#858=CARTESIAN_POINT('',(-10.6907590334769,26.9708746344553,27.7284628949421));
#859=CARTESIAN_POINT('',(-10.6992771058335,27.260953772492,27.7251691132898));
#860=CARTESIAN_POINT('',(-10.6928747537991,27.8408093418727,27.7276390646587));
#861=CARTESIAN_POINT('',(-10.6779550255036,28.1305857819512,27.7334025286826));
#862=CARTESIAN_POINT('',(-10.6248315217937,28.7076643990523,27.7537976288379));
#863=CARTESIAN_POINT('',(-10.586628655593,28.9949666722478,27.768428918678));
#864=CARTESIAN_POINT('',(-10.487319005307,29.5650209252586,27.8060870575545));
#865=CARTESIAN_POINT('',(-10.4262121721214,29.8477728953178,27.829113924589));
#866=CARTESIAN_POINT('',(-10.2831751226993,30.4009416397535,27.8822796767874));
#867=CARTESIAN_POINT('',(-10.2017040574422,30.6714926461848,27.9122608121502));
#868=CARTESIAN_POINT('',(-10.0180063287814,31.2047330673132,27.9787170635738));
#869=CARTESIAN_POINT('',(-9.91577232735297,31.4674196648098,28.015194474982));
#870=CARTESIAN_POINT('',(-9.6913575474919,31.9832686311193,28.0936154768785));
#871=CARTESIAN_POINT('',(-9.56917710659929,32.2364311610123,28.1355589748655));
#872=CARTESIAN_POINT('',(-9.30572013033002,32.7318375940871,28.2237911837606));
#873=CARTESIAN_POINT('',(-9.16444219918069,32.9740806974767,28.2700802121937));
#874=CARTESIAN_POINT('',(-8.85614161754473,33.4582060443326,28.3682170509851));
#875=CARTESIAN_POINT('',(-8.6881824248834,33.6994593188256,28.4202272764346));
#876=CARTESIAN_POINT('',(-8.33328844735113,34.16709767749,28.5263057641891));
#877=CARTESIAN_POINT('',(-8.14635315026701,34.3934823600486,28.5803740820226));
#878=CARTESIAN_POINT('',(-7.75457587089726,34.8301474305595,28.6891514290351));
#879=CARTESIAN_POINT('',(-7.54972863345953,35.0404230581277,28.7438606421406));
#880=CARTESIAN_POINT('',(-7.12336059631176,35.4435462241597,28.8524808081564));
#881=CARTESIAN_POINT('',(-6.90184004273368,35.6363940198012,28.9063917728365));
#882=CARTESIAN_POINT('',(-6.43357621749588,36.0113035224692,29.014285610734));
#883=CARTESIAN_POINT('',(-6.18615988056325,36.1925532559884,29.0681732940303));
#884=CARTESIAN_POINT('',(-5.67619584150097,36.5333992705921,29.1720414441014));
#885=CARTESIAN_POINT('',(-5.4136539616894,36.6930038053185,29.2220233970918));
#886=CARTESIAN_POINT('',(-4.87503820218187,36.9893678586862,29.3166895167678));
#887=CARTESIAN_POINT('',(-4.59896371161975,37.1261263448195,29.3613734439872));
#888=CARTESIAN_POINT('',(-4.03519508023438,37.3755769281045,29.4441483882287));
#889=CARTESIAN_POINT('',(-3.74750144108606,37.4882700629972,29.4822396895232));
#890=CARTESIAN_POINT('',(-3.17104886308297,37.6856147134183,29.5497163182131));
#891=CARTESIAN_POINT('',(-2.8825608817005,37.7709823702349,29.5793213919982));
#892=CARTESIAN_POINT('',(-2.29871842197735,37.9171668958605,29.6304112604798));
#893=CARTESIAN_POINT('',(-2.0033640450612,37.977984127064,29.6518961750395));
#894=CARTESIAN_POINT('',(-1.40816449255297,38.074418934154,29.6861149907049));
#895=CARTESIAN_POINT('',(-1.10832082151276,38.1100447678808,29.6988517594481));
#896=CARTESIAN_POINT('',(-0.506449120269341,38.1557413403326,29.7152089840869));
#897=CARTESIAN_POINT('',(-0.204421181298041,38.1658131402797,29.718829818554));
#898=CARTESIAN_POINT('',(0.383028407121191,38.1604452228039,29.7169040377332));
#899=CARTESIAN_POINT('',(0.668465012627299,38.1463553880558,29.7118424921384));
#900=CARTESIAN_POINT('',(1.2370205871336,38.0953573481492,29.6936052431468));
#901=CARTESIAN_POINT('',(1.52013965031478,38.0584500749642,29.6804298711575));
#902=CARTESIAN_POINT('',(2.08204465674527,37.9621748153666,29.6463125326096));
#903=CARTESIAN_POINT('',(2.36083068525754,37.9028072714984,29.6253707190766));
#904=CARTESIAN_POINT('',(2.91216660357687,37.7621610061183,29.5762643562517));
#905=CARTESIAN_POINT('',(3.18471639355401,37.6808819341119,29.5480996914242));
#906=CARTESIAN_POINT('',(3.72131336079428,37.4972887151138,29.4853217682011));
#907=CARTESIAN_POINT('',(3.98537481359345,37.3950122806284,29.4507200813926));
#908=CARTESIAN_POINT('',(4.50396957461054,37.1701274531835,29.37588213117));
#909=CARTESIAN_POINT('',(4.75849943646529,37.0475117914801,29.3356438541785));
#910=CARTESIAN_POINT('',(5.25645268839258,36.7828943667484,29.2505220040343));
#911=CARTESIAN_POINT('',(5.49987611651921,36.6408926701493,29.2056384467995));
#912=CARTESIAN_POINT('',(5.97429141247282,36.3384734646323,29.1122968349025));
#913=CARTESIAN_POINT('',(6.20528240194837,36.1780546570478,29.0638385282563));
#914=CARTESIAN_POINT('',(6.6652625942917,35.8310201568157,28.9619084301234));
#915=CARTESIAN_POINT('',(6.89352305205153,35.643475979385,28.9083069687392));
#916=CARTESIAN_POINT('',(7.33361154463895,35.2503480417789,28.7998097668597));
#917=CARTESIAN_POINT('',(7.54543909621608,35.0447637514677,28.7449139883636));
#918=CARTESIAN_POINT('',(7.95150265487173,34.6167381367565,28.635247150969));
#919=CARTESIAN_POINT('',(8.14573304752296,34.3942914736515,28.5804761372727));
#920=CARTESIAN_POINT('',(8.5153573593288,33.9339073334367,28.4725357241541));
#921=CARTESIAN_POINT('',(8.69075166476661,33.6959701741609,28.4193662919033));
#922=CARTESIAN_POINT('',(9.0277545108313,33.1968432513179,28.3141571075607));
#923=CARTESIAN_POINT('',(9.18860674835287,32.9351176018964,28.2622331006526));
#924=CARTESIAN_POINT('',(9.48758153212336,32.3982392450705,28.1632760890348));
#925=CARTESIAN_POINT('',(9.62571299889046,32.1230918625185,28.1162411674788));
#926=CARTESIAN_POINT('',(9.87817376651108,31.5611144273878,28.0285403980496));
#927=CARTESIAN_POINT('',(9.99250440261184,31.2742850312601,27.9878741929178));
#928=CARTESIAN_POINT('',(10.196318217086,30.6909669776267,27.9142683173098));
#929=CARTESIAN_POINT('',(10.2858026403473,30.3944788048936,27.8813282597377));
#930=CARTESIAN_POINT('',(10.4363561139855,29.8045509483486,27.8253162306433));
#931=CARTESIAN_POINT('',(10.4983067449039,29.5113651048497,27.8019403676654));
#932=CARTESIAN_POINT('',(10.5976005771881,28.9202762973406,27.7642435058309));
#933=CARTESIAN_POINT('',(10.6349443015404,28.6223734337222,27.7499223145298));
#934=CARTESIAN_POINT('',(10.6846176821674,28.0242771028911,27.7308344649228));
#935=CARTESIAN_POINT('',(10.6969551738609,27.7240843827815,27.726064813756));
#936=CARTESIAN_POINT('',(10.6965030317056,27.1237260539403,27.7262393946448));
#937=CARTESIAN_POINT('',(10.683714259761,26.8235604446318,27.7311832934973));
#938=CARTESIAN_POINT('',(10.6344958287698,26.2415165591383,27.7500929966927));
#939=CARTESIAN_POINT('',(10.59935490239,25.9595121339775,27.7635668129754));
#940=CARTESIAN_POINT('',(10.5070098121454,25.3996664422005,27.7986457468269));
#941=CARTESIAN_POINT('',(10.44980653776,25.1218250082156,27.8202505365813));
#942=CARTESIAN_POINT('',(10.3138520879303,24.5721435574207,27.8709388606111));
#943=CARTESIAN_POINT('',(10.2350988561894,24.3003041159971,27.9000231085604));
#944=CARTESIAN_POINT('',(10.0567158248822,23.7643777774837,27.9648169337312));
#945=CARTESIAN_POINT('',(9.9570854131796,23.5002911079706,28.000526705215));
#946=CARTESIAN_POINT('',(9.7359057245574,22.9771479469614,28.0782054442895));
#947=CARTESIAN_POINT('',(9.61401995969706,22.7182477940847,28.1202684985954));
#948=CARTESIAN_POINT('',(9.35032929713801,22.2115184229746,28.2090449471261));
#949=CARTESIAN_POINT('',(9.20851707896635,21.9636933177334,28.2557600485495));
#950=CARTESIAN_POINT('',(8.90594390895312,21.4805688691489,28.3525820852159));
#951=CARTESIAN_POINT('',(8.74518141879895,21.245270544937,28.402689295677));
#952=CARTESIAN_POINT('',(8.40570040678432,20.7884851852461,28.5050021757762));
#953=CARTESIAN_POINT('',(8.22698118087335,20.5669986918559,28.5572079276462));
#954=CARTESIAN_POINT('',(7.84147374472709,20.1263073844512,28.6655409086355));
#955=CARTESIAN_POINT('',(7.63364861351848,19.9080204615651,28.7217168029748));
#956=CARTESIAN_POINT('',(7.20034963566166,19.4897377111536,28.8333923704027));
#957=CARTESIAN_POINT('',(6.97488312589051,19.2897343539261,28.8888923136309));
#958=CARTESIAN_POINT('',(6.50743622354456,18.9091139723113,28.9977655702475));
#959=CARTESIAN_POINT('',(6.26544671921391,18.7285077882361,29.0511376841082));
#960=CARTESIAN_POINT('',(5.76662828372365,18.3881562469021,29.1542509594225));
#961=CARTESIAN_POINT('',(5.50980547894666,18.2284023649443,29.2039936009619));
#962=CARTESIAN_POINT('',(4.98001650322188,17.9293096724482,29.2990126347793));
#963=CARTESIAN_POINT('',(4.70690727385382,17.7902069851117,29.3442356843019));
#964=CARTESIAN_POINT('',(4.1489099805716,17.5356790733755,29.428314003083));
#965=CARTESIAN_POINT('',(3.86402174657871,17.4202541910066,29.4671691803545));
#966=CARTESIAN_POINT('',(3.28461329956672,17.2142090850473,29.537365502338));
#967=CARTESIAN_POINT('',(2.99009637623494,17.1235804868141,29.5687091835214));
#968=CARTESIAN_POINT('',(2.39359781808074,16.9680062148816,29.6229619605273));
#969=CARTESIAN_POINT('',(2.09161660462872,16.9030590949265,29.6458715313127));
#970=CARTESIAN_POINT('',(1.49840874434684,16.8022302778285,29.6816099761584));
#971=CARTESIAN_POINT('',(1.2074356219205,16.765016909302,29.6948996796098));
#972=CARTESIAN_POINT('',(0.623151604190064,16.7146852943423,29.7129032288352));
#973=CARTESIAN_POINT('',(0.329840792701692,16.7015661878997,29.7176173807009));
#974=CARTESIAN_POINT('',(-0.256802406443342,16.6995588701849,29.7183377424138));
#975=CARTESIAN_POINT('',(-0.550134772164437,16.7106648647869,29.7143460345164));
#976=CARTESIAN_POINT('',(-1.13464284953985,16.7569803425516,29.6977707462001));
#977=CARTESIAN_POINT('',(-1.42581858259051,16.7921895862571,29.6851872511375));
#978=CARTESIAN_POINT('',(-1.99346646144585,16.8846629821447,29.6523783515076));
#979=CARTESIAN_POINT('',(-2.27009189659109,16.9410927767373,29.6324425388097));
#980=CARTESIAN_POINT('',(-2.81741717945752,17.0755047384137,29.5854208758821));
#981=CARTESIAN_POINT('',(-3.08811728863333,17.1534859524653,29.5583353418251));
#982=CARTESIAN_POINT('',(-3.62194488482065,17.3303578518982,29.4976818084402));
#983=CARTESIAN_POINT('',(-3.88506982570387,17.4292554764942,29.4641116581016));
#984=CARTESIAN_POINT('',(-4.40206426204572,17.6471506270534,29.3913171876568));
#985=CARTESIAN_POINT('',(-4.65593281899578,17.7661501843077,29.3520922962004));
#986=CARTESIAN_POINT('',(-5.18499974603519,18.0399576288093,29.2635642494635));
#987=CARTESIAN_POINT('',(-5.4587278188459,18.1974041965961,29.2136137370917));
#988=CARTESIAN_POINT('',(-5.99061449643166,18.5354286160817,29.1092004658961));
#989=CARTESIAN_POINT('',(-6.24877128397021,18.7160091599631,29.0547371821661));
#990=CARTESIAN_POINT('',(-6.747822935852,19.0988908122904,28.9429061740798));
#991=CARTESIAN_POINT('',(-6.98871518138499,19.3011952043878,28.8855380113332));
#992=CARTESIAN_POINT('',(-7.45170815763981,19.726102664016,28.7695768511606));
#993=CARTESIAN_POINT('',(-7.67380272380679,19.9487123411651,28.7109834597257));
#994=CARTESIAN_POINT('',(-7.88572135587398,20.1806746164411,28.6526599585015));
#995=B_SPLINE_CURVE_WITH_KNOTS('',3,(#841,#842,#843,#844,#845,#846,#847,#848,#849,#850,#851,
#852,#853,#854,#855,#856,#857,#858,#859,#860,#861,#862,#863,#864,#865,#866,#867,#868,#869,#870,
#871,#872,#873,#874,#875,#876,#877,#878,#879,#880,#881,#882,#883,#884,#885,#886,#887,#888,#889,
#890,#891,#892,#893,#894,#895,#896,#897,#898,#899,#900,#901,#902,#903,#904,#905,#906,#907,#908,
#909,#910,#911,#912,#913,#914,#915,#916,#917,#918,#919,#920,#921,#922,#923,#924,#925,#926,#927,
#928,#929,#930,#931,#932,#933,#934,#935,#936,#937,#938,#939,#940,#941,#942,#943,#944,#945,#946,
#947,#948,#949,#950,#951,#952,#953,#954,#955,#956,#957,#958,#959,#960,#961,#962,#963,#964,#965,
#966,#967,#968,#969,#970,#971,#972,#973,#974,#975,#976,#977,#978,#979,#980,#981,#982,#983,#984,
#985,#986,#987,#988,#989,#990,#991,#992,#993,#994),.UNSPECIFIED.,.T.,.F.,(4,2,2,2,2,2,2,2,2,2,2,
2,2,2,2,2,2,2,2,2,2,2,2,2,2,2,2,2,2,2,2,2,2,2,2,2,2,2,2,2,2,2,2,2,2,2,2,2,2,2,2,2,2,2,2,2,2,2,2,
2,2,2,2,2,2,2,2,2,2,2,2,2,2,2,2,2,4),(0.,0.907947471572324,1.81586103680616,2.72367832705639,
3.6311611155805,4.54117912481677,5.45119717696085,6.36094028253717,7.27064302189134,
8.14023277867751,9.00979670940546,9.87932668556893,10.7488585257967,11.6003194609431,
12.4520818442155,13.3038298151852,14.1556400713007,15.0502247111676,15.9448335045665,
16.8397056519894,17.7345645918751,18.6676271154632,19.6003328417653,20.5330807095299,
21.465788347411,22.3715467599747,23.2772918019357,24.1827397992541,25.0881501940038,
25.9446079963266,26.8010308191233,27.6574367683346,28.5138564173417,29.3687511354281,
30.2239520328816,31.0791499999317,31.9344083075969,32.834141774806,33.7339016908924,
34.6339476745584,35.5339751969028,36.4675090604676,37.4006755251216,38.3337896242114,
39.2668569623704,40.1674075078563,41.0679389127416,41.9681881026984,42.8684064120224,
43.7209188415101,44.5733969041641,45.4259563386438,46.2785407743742,47.1452821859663,
48.0123428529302,48.8794739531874,49.7466390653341,50.6653403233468,51.5836615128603,
52.5024932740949,53.4209482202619,54.3492071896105,55.2774795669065,56.2054380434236,
57.1333442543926,58.0131703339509,58.8929650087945,59.7725492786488,60.6521248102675,
61.5002234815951,62.3482846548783,63.1966276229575,64.0450563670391,65.0028789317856,
65.9608130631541,66.9188921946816,67.8772843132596),.UNSPECIFIED.);
#996=CARTESIAN_POINT('',(-7.88572135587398,20.1806746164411,28.6526599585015));
#997=VERTEX_POINT('',#996);
#998=EDGE_CURVE('E40',#997,#997,#995,.T.);
#999=ORIENTED_EDGE('',*,*,#998,.T.);
#1000=EDGE_LOOP('',(#999));
#1001=FACE_BOUND('',#1000,.T.);
#1002=CARTESIAN_POINT('',(0.,1.52399999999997,0.));
#1003=DIRECTION('',(0.,1.,0.));
#1004=DIRECTION('',(0.,0.,1.));
#1005=AXIS2_PLACEMENT_3D('',#1002,#1003,#1004);
#1006=CIRCLE('',#1005,29.718);
#1007=CARTESIAN_POINT('',(0.,1.52399999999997,29.718));
#1008=VERTEX_POINT('',#1007);
#1009=EDGE_CURVE('E852',#1008,#1008,#1006,.T.);
#1010=ORIENTED_EDGE('',*,*,#1009,.T.);
#1011=EDGE_LOOP('',(#1010));
#1012=FACE_BOUND('',#1011,.T.);
#1013=CARTESIAN_POINT('',(0.,55.88,0.));
#1014=DIRECTION('',(0.,-1.,0.));
#1015=DIRECTION('',(0.,0.,-1.));
#1016=AXIS2_PLACEMENT_3D('',#1013,#1014,#1015);
#1017=CIRCLE('',#1016,29.718);
#1018=CARTESIAN_POINT('',(0.,55.88,-29.718));
#1019=VERTEX_POINT('',#1018);
#1020=EDGE_CURVE('E843',#1019,#1019,#1017,.T.);
#1021=ORIENTED_EDGE('',*,*,#1020,.T.);
#1022=EDGE_LOOP('',(#1021));
#1023=FACE_BOUND('',#1022,.T.);
#1024=ADVANCED_FACE('F934',(#840,#1001,#1012,#1023),#679,.T.);
#1025=CARTESIAN_POINT('',(0.,0.,0.));
#1026=DIRECTION('',(0.,1.,0.));
#1027=DIRECTION('',(0.,0.,1.));
#1028=AXIS2_PLACEMENT_3D('',#1025,#1026,#1027);
#1029=PLANE('',#1028);
#1030=CARTESIAN_POINT('',(0.,0.,0.));
#1031=DIRECTION('',(0.,1.,0.));
#1032=DIRECTION('',(0.,0.,1.));
#1033=AXIS2_PLACEMENT_3D('',#1030,#1031,#1032);
#1034=CIRCLE('',#1033,28.194);
#1035=CARTESIAN_POINT('',(0.,0.,28.194));
#1036=VERTEX_POINT('',#1035);
#1037=EDGE_CURVE('E855',#1036,#1036,#1034,.F.);
#1038=ORIENTED_EDGE('',*,*,#1037,.T.);
#1039=EDGE_LOOP('',(#1038));
#1040=FACE_BOUND('',#1039,.T.);
#1041=ADVANCED_FACE('F941',(#1040),#1029,.F.);
#1042=CARTESIAN_POINT('',(-29.718,55.88,0.));
#1043=DIRECTION('',(0.,1.,0.));
#1044=DIRECTION('',(0.,0.,1.));
#1045=AXIS2_PLACEMENT_3D('',#1042,#1043,#1044);
#1046=PLANE('',#1045);
#1047=CARTESIAN_POINT('',(0.,55.88,0.));
#1048=DIRECTION('',(0.,-1.,0.));
#1049=DIRECTION('',(0.,0.,-1.));
#1050=AXIS2_PLACEMENT_3D('',#1047,#1048,#1049);
#1051=CIRCLE('',#1050,20.6254667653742);
#1052=CARTESIAN_POINT('',(0.,55.88,-20.6254667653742));
#1053=VERTEX_POINT('',#1052);
#1054=EDGE_CURVE('E840',#1053,#1053,#1051,.T.);
#1055=ORIENTED_EDGE('',*,*,#1054,.T.);
#1056=EDGE_LOOP('',(#1055));
#1057=FACE_BOUND('',#1056,.T.);
#1058=ORIENTED_EDGE('',*,*,#1020,.F.);
#1059=EDGE_LOOP('',(#1058));
#1060=FACE_BOUND('',#1059,.T.);
#1061=ADVANCED_FACE('F1646',(#1057,#1060),#1046,.T.);
#1062=CARTESIAN_POINT('',(0.,0.,0.));
#1063=DIRECTION('',(0.,-1.,0.));
#1064=DIRECTION('',(0.,0.,-1.));
#1065=AXIS2_PLACEMENT_3D('',#1062,#1063,#1064);
#1066=CYLINDRICAL_SURFACE('',#1065,20.6254667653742);
#1067=CARTESIAN_POINT('',(0.,56.134,0.));
#1068=DIRECTION('',(0.,-1.,0.));
#1069=DIRECTION('',(0.,0.,-1.));
#1070=AXIS2_PLACEMENT_3D('',#1067,#1068,#1069);
#1071=CIRCLE('',#1070,20.6254667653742);
#1072=CARTESIAN_POINT('',(0.,56.134,-20.6254667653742));
#1073=VERTEX_POINT('',#1072);
#1074=EDGE_CURVE('E837',#1073,#1073,#1071,.T.);
#1075=ORIENTED_EDGE('',*,*,#1074,.T.);
#1076=EDGE_LOOP('',(#1075));
#1077=FACE_BOUND('',#1076,.T.);
#1078=ORIENTED_EDGE('',*,*,#1054,.F.);
#1079=EDGE_LOOP('',(#1078));
#1080=FACE_BOUND('',#1079,.T.);
#1081=ADVANCED_FACE('F1676',(#1077,#1080),#1066,.T.);
#1082=CARTESIAN_POINT('',(-20.6254667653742,56.134,0.));
#1083=DIRECTION('',(0.,-1.,0.));
#1084=DIRECTION('',(0.,0.,-1.));
#1085=AXIS2_PLACEMENT_3D('',#1082,#1083,#1084);
#1086=PLANE('',#1085);
#1087=CARTESIAN_POINT('',(0.,56.134,0.));
#1088=DIRECTION('',(0.,-1.,0.));
#1089=DIRECTION('',(0.,0.,-1.));
#1090=AXIS2_PLACEMENT_3D('',#1087,#1088,#1089);
#1091=CIRCLE('',#1090,29.718);
#1092=CARTESIAN_POINT('',(0.,56.134,-29.718));
#1093=VERTEX_POINT('',#1092);
#1094=EDGE_CURVE('E833',#1093,#1093,#1091,.T.);
#1095=ORIENTED_EDGE('',*,*,#1094,.T.);
#1096=EDGE_LOOP('',(#1095));
#1097=FACE_BOUND('',#1096,.T.);
#1098=ORIENTED_EDGE('',*,*,#1074,.F.);
#1099=EDGE_LOOP('',(#1098));
#1100=FACE_BOUND('',#1099,.T.);
#1101=ADVANCED_FACE('F931',(#1097,#1100),#1086,.T.);
#1102=EDGE_CURVE('E830',#517,#363,#45,.T.);
#1103=ORIENTED_EDGE('',*,*,#1102,.T.);
#1104=ORIENTED_EDGE('',*,*,#364,.T.);
#1105=EDGE_CURVE('E1279',#359,#205,#45,.T.);
#1106=ORIENTED_EDGE('',*,*,#1105,.T.);
#1107=ORIENTED_EDGE('',*,*,#206,.T.);
#1108=EDGE_CURVE('E962',#201,#47,#45,.T.);
#1109=ORIENTED_EDGE('',*,*,#1108,.T.);
#1110=ORIENTED_EDGE('',*,*,#48,.T.);
#1111=EDGE_CURVE('E960',#36,#521,#45,.T.);
#1112=ORIENTED_EDGE('',*,*,#1111,.T.);
#1113=ORIENTED_EDGE('',*,*,#522,.T.);
#1114=EDGE_LOOP('',(#1103,#1104,#1106,#1107,#1109,#1110,#1112,#1113));
#1115=FACE_BOUND('',#1114,.T.);
#1116=ORIENTED_EDGE('',*,*,#1094,.F.);
#1117=EDGE_LOOP('',(#1116));
#1118=FACE_BOUND('',#1117,.T.);
#1119=ADVANCED_FACE('F923',(#1115,#1118),#679,.T.);
#1120=CARTESIAN_POINT('',(0.,0.,0.));
#1121=DIRECTION('',(0.,-1.,0.));
#1122=DIRECTION('',(0.,0.,-1.));
#1123=AXIS2_PLACEMENT_3D('',#1120,#1121,#1122);
#1124=CYLINDRICAL_SURFACE('',#1123,15.875);
#1125=CARTESIAN_POINT('',(0.,104.14,0.));
#1126=DIRECTION('',(0.,1.,0.));
#1127=DIRECTION('',(0.,0.,1.));
#1128=AXIS2_PLACEMENT_3D('',#1125,#1126,#1127);
#1129=CIRCLE('',#1128,15.875);
#1130=CARTESIAN_POINT('',(0.,104.14,15.875));
#1131=VERTEX_POINT('',#1130);
#1132=EDGE_CURVE('E846',#1131,#1131,#1129,.F.);
#1133=ORIENTED_EDGE('',*,*,#1132,.T.);
#1134=EDGE_LOOP('',(#1133));
#1135=FACE_BOUND('',#1134,.T.);
#1136=ORIENTED_EDGE('',*,*,#670,.F.);
#1137=EDGE_LOOP('',(#1136));
#1138=FACE_BOUND('',#1137,.T.);
#1139=ADVANCED_FACE('F921',(#1135,#1138),#1124,.T.);
#1140=CARTESIAN_POINT('',(0.,105.41,0.));
#1141=DIRECTION('',(0.,1.,0.));
#1142=DIRECTION('',(0.,0.,1.));
#1143=AXIS2_PLACEMENT_3D('',#1140,#1141,#1142);
#1144=PLANE('',#1143);
#1145=CARTESIAN_POINT('',(0.,105.41,0.));
#1146=DIRECTION('',(0.,1.,0.));
#1147=DIRECTION('',(0.,0.,1.));
#1148=AXIS2_PLACEMENT_3D('',#1145,#1146,#1147);
#1149=CIRCLE('',#1148,14.605);
#1150=CARTESIAN_POINT('',(0.,105.41,14.605));
#1151=VERTEX_POINT('',#1150);
#1152=EDGE_CURVE('E849',#1151,#1151,#1149,.T.);
#1153=ORIENTED_EDGE('',*,*,#1152,.T.);
#1154=EDGE_LOOP('',(#1153));
#1155=FACE_BOUND('',#1154,.T.);
#1156=CARTESIAN_POINT('',(0.,105.41,0.));
#1157=DIRECTION('',(0.,1.,0.));
#1158=DIRECTION('',(0.,0.,1.));
#1159=AXIS2_PLACEMENT_3D('',#1156,#1157,#1158);
#1160=CIRCLE('',#1159,10.16);
#1161=CARTESIAN_POINT('',(0.,105.41,10.16));
#1162=VERTEX_POINT('',#1161);
#1163=EDGE_CURVE('E814',#1162,#1162,#1160,.T.);
#1164=ORIENTED_EDGE('',*,*,#1163,.F.);
#1165=EDGE_LOOP('',(#1164));
#1166=FACE_BOUND('',#1165,.T.);
#1167=ADVANCED_FACE('F919',(#1155,#1166),#1144,.T.);
#1168=CARTESIAN_POINT('',(0.,105.41,0.));
#1169=DIRECTION('',(0.,1.,0.));
#1170=DIRECTION('',(0.,0.,1.));
#1171=AXIS2_PLACEMENT_3D('',#1168,#1169,#1170);
#1172=CONICAL_SURFACE('',#1171,10.16,0.78539816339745);
#1173=CARTESIAN_POINT('',(0.,104.14,0.));
#1174=DIRECTION('',(0.,1.,0.));
#1175=DIRECTION('',(0.,0.,1.));
#1176=AXIS2_PLACEMENT_3D('',#1173,#1174,#1175);
#1177=CIRCLE('',#1176,8.89);
#1178=CARTESIAN_POINT('',(0.,104.14,8.89));
#1179=VERTEX_POINT('',#1178);
#1180=EDGE_CURVE('E823',#1179,#1179,#1177,.T.);
#1181=ORIENTED_EDGE('',*,*,#1180,.F.);
#1182=EDGE_LOOP('',(#1181));
#1183=FACE_BOUND('',#1182,.T.);
#1184=ORIENTED_EDGE('',*,*,#1163,.T.);
#1185=EDGE_LOOP('',(#1184));
#1186=FACE_BOUND('',#1185,.T.);
#1187=ADVANCED_FACE('F916',(#1183,#1186),#1172,.F.);
#1188=CARTESIAN_POINT('',(0.,104.14,0.));
#1189=DIRECTION('',(0.,-1.,0.));
#1190=DIRECTION('',(0.,0.,-1.));
#1191=AXIS2_PLACEMENT_3D('',#1188,#1189,#1190);
#1192=CONICAL_SURFACE('',#1191,15.875,0.785398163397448);
#1193=ORIENTED_EDGE('',*,*,#1152,.F.);
#1194=EDGE_LOOP('',(#1193));
#1195=FACE_BOUND('',#1194,.T.);
#1196=ORIENTED_EDGE('',*,*,#1132,.F.);
#1197=EDGE_LOOP('',(#1196));
#1198=FACE_BOUND('',#1197,.T.);
#1199=ADVANCED_FACE('F918',(#1195,#1198),#1192,.T.);
#1200=CARTESIAN_POINT('',(0.,1.52399999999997,0.));
#1201=DIRECTION('',(0.,1.,0.));
#1202=DIRECTION('',(0.,0.,1.));
#1203=AXIS2_PLACEMENT_3D('',#1200,#1201,#1202);
#1204=CONICAL_SURFACE('',#1203,29.718,0.785398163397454);
#1205=ORIENTED_EDGE('',*,*,#1037,.F.);
#1206=EDGE_LOOP('',(#1205));
#1207=FACE_BOUND('',#1206,.T.);
#1208=ORIENTED_EDGE('',*,*,#1009,.F.);
#1209=EDGE_LOOP('',(#1208));
#1210=FACE_BOUND('',#1209,.T.);
#1211=ADVANCED_FACE('F914',(#1207,#1210),#1204,.T.);
#1212=CARTESIAN_POINT('',(0.,78.9952828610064,0.));
#1213=DIRECTION('',(0.,1.,0.));
#1214=DIRECTION('',(0.,0.,1.));
#1215=AXIS2_PLACEMENT_3D('',#1212,#1213,#1214);
#1216=CYLINDRICAL_SURFACE('',#1215,8.89);
#1217=CARTESIAN_POINT('',(0.,104.648,0.));
#1218=DIRECTION('',(0.,1.,0.));
#1219=DIRECTION('',(0.,0.,1.));
#1220=AXIS2_PLACEMENT_3D('',#1217,#1218,#1219);
#1221=CIRCLE('',#1220,8.89);
#1222=CARTESIAN_POINT('',(0.,104.648,-8.89000000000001));
#1223=VERTEX_POINT('',#1222);
#1224=EDGE_CURVE('E861',#1223,#1223,#1221,.F.);
#1225=ORIENTED_EDGE('',*,*,#1224,.T.);
#1226=EDGE_LOOP('',(#1225));
#1227=FACE_BOUND('',#1226,.T.);
#1228=ORIENTED_EDGE('',*,*,#1180,.T.);
#1229=EDGE_LOOP('',(#1228));
#1230=FACE_BOUND('',#1229,.T.);
#1231=ADVANCED_FACE('F910',(#1227,#1230),#1216,.T.);
#1232=CARTESIAN_POINT('',(0.,105.41,0.));
#1233=DIRECTION('',(0.,1.,0.));
#1234=DIRECTION('',(0.,0.,1.));
#1235=AXIS2_PLACEMENT_3D('',#1232,#1233,#1234);
#1236=PLANE('',#1235);
#1237=CARTESIAN_POINT('',(3.175,105.41,0.));
#1238=DIRECTION('',(0.,1.,0.));
#1239=DIRECTION('',(0.,0.,1.));
#1240=AXIS2_PLACEMENT_3D('',#1237,#1238,#1239);
#1241=CIRCLE('',#1240,0.9652);
#1242=CARTESIAN_POINT('',(3.175,105.41,0.9652));
#1243=VERTEX_POINT('',#1242);
#1244=CARTESIAN_POINT('',(3.175,105.41,-0.9652));
#1245=VERTEX_POINT('',#1244);
#1246=EDGE_CURVE('E788',#1243,#1245,#1241,.T.);
#1247=ORIENTED_EDGE('',*,*,#1246,.F.);
#1248=DIRECTION('',(1.,0.,0.));
#1249=VECTOR('',#1248,1.);
#1250=CARTESIAN_POINT('',(3.175,105.41,0.9652));
#1251=LINE('',#1250,#1249);
#1252=CARTESIAN_POINT('',(-3.175,105.41,0.9652));
#1253=VERTEX_POINT('',#1252);
#1254=EDGE_CURVE('E793',#1253,#1243,#1251,.T.);
#1255=ORIENTED_EDGE('',*,*,#1254,.F.);
#1256=CARTESIAN_POINT('',(-3.175,105.41,0.));
#1257=DIRECTION('',(0.,1.,0.));
#1258=DIRECTION('',(0.,0.,1.));
#1259=AXIS2_PLACEMENT_3D('',#1256,#1257,#1258);
#1260=CIRCLE('',#1259,0.9652);
#1261=CARTESIAN_POINT('',(-3.175,105.41,-0.9652));
#1262=VERTEX_POINT('',#1261);
#1263=EDGE_CURVE('E807',#1262,#1253,#1260,.T.);
#1264=ORIENTED_EDGE('',*,*,#1263,.F.);
#1265=DIRECTION('',(-1.,0.,0.));
#1266=VECTOR('',#1265,1.);
#1267=CARTESIAN_POINT('',(-3.175,105.41,-0.9652));
#1268=LINE('',#1267,#1266);
#1269=EDGE_CURVE('E804',#1245,#1262,#1268,.T.);
#1270=ORIENTED_EDGE('',*,*,#1269,.F.);
#1271=EDGE_LOOP('',(#1247,#1255,#1264,#1270));
#1272=FACE_BOUND('',#1271,.T.);
#1273=CARTESIAN_POINT('',(0.,105.41,0.));
#1274=DIRECTION('',(0.,1.,0.));
#1275=DIRECTION('',(0.,0.,1.));
#1276=AXIS2_PLACEMENT_3D('',#1273,#1274,#1275);
#1277=CIRCLE('',#1276,8.128);
#1278=CARTESIAN_POINT('',(0.,105.41,-8.128));
#1279=VERTEX_POINT('',#1278);
#1280=EDGE_CURVE('E858',#1279,#1279,#1277,.T.);
#1281=ORIENTED_EDGE('',*,*,#1280,.T.);
#1282=EDGE_LOOP('',(#1281));
#1283=FACE_BOUND('',#1282,.T.);
#1284=ADVANCED_FACE('F907',(#1272,#1283),#1236,.T.);
#1285=CARTESIAN_POINT('',(0.,105.41,0.));
#1286=DIRECTION('',(0.,-1.,0.));
#1287=DIRECTION('',(0.,0.,-1.));
#1288=AXIS2_PLACEMENT_3D('',#1285,#1286,#1287);
#1289=CONICAL_SURFACE('',#1288,8.128,0.785398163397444);
#1290=CARTESIAN_POINT('',(0.,104.648,-8.89000000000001));
#1291=CARTESIAN_POINT('',(0.,104.6559375,-8.88206250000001));
#1292=CARTESIAN_POINT('',(0.,104.663875,-8.87412500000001));
#1293=CARTESIAN_POINT('',(0.,104.67975,-8.85825000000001));
#1294=CARTESIAN_POINT('',(0.,104.6876875,-8.85031250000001));
#1295=CARTESIAN_POINT('',(0.,104.7035625,-8.83443750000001));
#1296=CARTESIAN_POINT('',(0.,104.7115,-8.82650000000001));
#1297=CARTESIAN_POINT('',(0.,104.727375,-8.81062500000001));
#1298=CARTESIAN_POINT('',(0.,104.7353125,-8.80268750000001));
#1299=CARTESIAN_POINT('',(0.,104.7511875,-8.78681250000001));
#1300=CARTESIAN_POINT('',(0.,104.759125,-8.77887500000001));
#1301=CARTESIAN_POINT('',(0.,104.775,-8.76300000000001));
#1302=CARTESIAN_POINT('',(0.,104.7829375,-8.75506250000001));
#1303=CARTESIAN_POINT('',(0.,104.7988125,-8.73918750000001));
#1304=CARTESIAN_POINT('',(0.,104.80675,-8.73125000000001));
#1305=CARTESIAN_POINT('',(0.,104.822625,-8.71537500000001));
#1306=CARTESIAN_POINT('',(0.,104.8305625,-8.70743750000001));
#1307=CARTESIAN_POINT('',(0.,104.8464375,-8.69156250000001));
#1308=CARTESIAN_POINT('',(0.,104.854375,-8.68362500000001));
#1309=CARTESIAN_POINT('',(0.,104.87025,-8.66775000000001));
#1310=CARTESIAN_POINT('',(0.,104.8781875,-8.65981250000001));
#1311=CARTESIAN_POINT('',(0.,104.8940625,-8.64393750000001));
#1312=CARTESIAN_POINT('',(0.,104.902,-8.63600000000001));
#1313=CARTESIAN_POINT('',(0.,104.917875,-8.62012500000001));
#1314=CARTESIAN_POINT('',(0.,104.9258125,-8.61218750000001));
#1315=CARTESIAN_POINT('',(0.,104.9416875,-8.59631250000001));
#1316=CARTESIAN_POINT('',(0.,104.949625,-8.58837500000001));
#1317=CARTESIAN_POINT('',(0.,104.9655,-8.57250000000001));
#1318=CARTESIAN_POINT('',(0.,104.9734375,-8.56456250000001));
#1319=CARTESIAN_POINT('',(0.,104.9893125,-8.54868750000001));
#1320=CARTESIAN_POINT('',(0.,104.99725,-8.54075000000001));
#1321=CARTESIAN_POINT('',(0.,105.013125,-8.52487500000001));
#1322=CARTESIAN_POINT('',(0.,105.0210625,-8.5169375));
#1323=CARTESIAN_POINT('',(0.,105.0369375,-8.50106250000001));
#1324=CARTESIAN_POINT('',(0.,105.044875,-8.49312500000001));
#1325=CARTESIAN_POINT('',(0.,105.06075,-8.47725000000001));
#1326=CARTESIAN_POINT('',(0.,105.0686875,-8.46931250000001));
#1327=CARTESIAN_POINT('',(0.,105.0845625,-8.45343750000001));
#1328=CARTESIAN_POINT('',(0.,105.0925,-8.4455));
#1329=CARTESIAN_POINT('',(0.,105.108375,-8.42962500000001));
#1330=CARTESIAN_POINT('',(0.,105.1163125,-8.42168750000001));
#1331=CARTESIAN_POINT('',(0.,105.1321875,-8.40581250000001));
#1332=CARTESIAN_POINT('',(0.,105.140125,-8.397875));
#1333=CARTESIAN_POINT('',(0.,105.156,-8.382));
#1334=CARTESIAN_POINT('',(0.,105.1639375,-8.37406250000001));
#1335=CARTESIAN_POINT('',(0.,105.1798125,-8.35818750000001));
#1336=CARTESIAN_POINT('',(0.,105.18775,-8.35025));
#1337=CARTESIAN_POINT('',(0.,105.203625,-8.334375));
#1338=CARTESIAN_POINT('',(0.,105.2115625,-8.3264375));
#1339=CARTESIAN_POINT('',(0.,105.2274375,-8.3105625));
#1340=CARTESIAN_POINT('',(0.,105.235375,-8.30262500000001));
#1341=CARTESIAN_POINT('',(0.,105.25125,-8.28675));
#1342=CARTESIAN_POINT('',(0.,105.2591875,-8.2788125));
#1343=CARTESIAN_POINT('',(0.,105.2750625,-8.2629375));
#1344=CARTESIAN_POINT('',(0.,105.283,-8.25500000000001));
#1345=CARTESIAN_POINT('',(0.,105.298875,-8.23912500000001));
#1346=CARTESIAN_POINT('',(0.,105.3068125,-8.23118750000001));
#1347=CARTESIAN_POINT('',(0.,105.3226875,-8.2153125));
#1348=CARTESIAN_POINT('',(0.,105.330625,-8.207375));
#1349=CARTESIAN_POINT('',(0.,105.3465,-8.1915));
#1350=CARTESIAN_POINT('',(0.,105.3544375,-8.1835625));
#1351=CARTESIAN_POINT('',(0.,105.3703125,-8.1676875));
#1352=CARTESIAN_POINT('',(0.,105.37825,-8.15975));
#1353=CARTESIAN_POINT('',(0.,105.394125,-8.143875));
#1354=CARTESIAN_POINT('',(0.,105.4020625,-8.1359375));
#1355=CARTESIAN_POINT('',(0.,105.41,-8.128));
#1356=B_SPLINE_CURVE_WITH_KNOTS('',3,(#1290,#1291,#1292,#1293,#1294,#1295,#1296,#1297,#1298,
#1299,#1300,#1301,#1302,#1303,#1304,#1305,#1306,#1307,#1308,#1309,#1310,#1311,#1312,#1313,#1314,
#1315,#1316,#1317,#1318,#1319,#1320,#1321,#1322,#1323,#1324,#1325,#1326,#1327,#1328,#1329,#1330,
#1331,#1332,#1333,#1334,#1335,#1336,#1337,#1338,#1339,#1340,#1341,#1342,#1343,#1344,#1345,#1346,
#1347,#1348,#1349,#1350,#1351,#1352,#1353,#1354,#1355),.UNSPECIFIED.,.F.,.F.,(4,2,2,2,2,2,2,2,2,
2,2,2,2,2,2,2,2,2,2,2,2,2,2,2,2,2,2,2,2,2,2,2,4),(0.,0.0336759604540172,0.0673519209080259,
0.101027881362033,0.134703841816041,0.168379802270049,0.202055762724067,0.235731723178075,
0.269407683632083,0.30308364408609,0.336759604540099,0.370435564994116,0.404111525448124,
0.437787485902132,0.47146344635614,0.505139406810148,0.538815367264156,0.572491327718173,
0.606167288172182,0.639843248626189,0.673519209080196,0.707195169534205,0.740871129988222,
0.774547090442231,0.808223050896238,0.841899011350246,0.875574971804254,0.909250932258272,
0.942926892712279,0.976602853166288,1.0102788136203,1.0439547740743,1.07763073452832),.UNSPECIFIED.);
#1357=EDGE_CURVE('BSEAM905',#1223,#1279,#1356,.T.);
#1358=ORIENTED_EDGE('',*,*,#1224,.F.);
#1359=ORIENTED_EDGE('',*,*,#1280,.F.);
#1360=ORIENTED_EDGE('',*,*,#1357,.T.);
#1361=ORIENTED_EDGE('',*,*,#1357,.F.);
#1362=EDGE_LOOP('',(#1358,#1360,#1359,#1361));
#1363=FACE_BOUND('',#1362,.T.);
#1364=ADVANCED_FACE('F905',(#1363),#1289,.T.);
#1365=CARTESIAN_POINT('',(3.175,100.6602,0.));
#1366=DIRECTION('',(0.,1.,0.));
#1367=DIRECTION('',(0.,0.,1.));
#1368=AXIS2_PLACEMENT_3D('',#1365,#1366,#1367);
#1369=CYLINDRICAL_SURFACE('',#1368,0.9652);
#1370=ORIENTED_EDGE('',*,*,#1246,.T.);
#1371=DIRECTION('',(0.,1.,0.));
#1372=VECTOR('',#1371,1.);
#1373=CARTESIAN_POINT('',(3.175,100.6602,-0.9652));
#1374=LINE('',#1373,#1372);
#1375=CARTESIAN_POINT('',(3.175,100.6602,-0.9652));
#1376=VERTEX_POINT('',#1375);
#1377=EDGE_CURVE('E802',#1376,#1245,#1374,.T.);
#1378=ORIENTED_EDGE('',*,*,#1377,.F.);
#1379=CARTESIAN_POINT('',(3.175,100.6602,0.));
#1380=DIRECTION('',(0.,1.,0.));
#1381=DIRECTION('',(0.,0.,1.));
#1382=AXIS2_PLACEMENT_3D('',#1379,#1380,#1381);
#1383=CIRCLE('',#1382,0.9652);
#1384=CARTESIAN_POINT('',(3.175,100.6602,0.9652));
#1385=VERTEX_POINT('',#1384);
#1386=EDGE_CURVE('E789',#1385,#1376,#1383,.T.);
#1387=ORIENTED_EDGE('',*,*,#1386,.F.);
#1388=DIRECTION('',(0.,1.,0.));
#1389=VECTOR('',#1388,1.);
#1390=CARTESIAN_POINT('',(3.175,100.6602,0.9652));
#1391=LINE('',#1390,#1389);
#1392=EDGE_CURVE('E812',#1385,#1243,#1391,.T.);
#1393=ORIENTED_EDGE('',*,*,#1392,.T.);
#1394=EDGE_LOOP('',(#1370,#1378,#1387,#1393));
#1395=FACE_BOUND('',#1394,.T.);
#1396=ADVANCED_FACE('F895',(#1395),#1369,.F.);
#1397=CARTESIAN_POINT('',(3.175,100.6602,0.9652));
#1398=DIRECTION('',(0.,0.,1.));
#1399=DIRECTION('',(1.,0.,0.));
#1400=AXIS2_PLACEMENT_3D('',#1397,#1398,#1399);
#1401=PLANE('',#1400);
#1402=ORIENTED_EDGE('',*,*,#1254,.T.);
#1403=ORIENTED_EDGE('',*,*,#1392,.F.);
#1404=DIRECTION('',(1.,0.,0.));
#1405=VECTOR('',#1404,1.);
#1406=CARTESIAN_POINT('',(3.175,100.6602,0.9652));
#1407=LINE('',#1406,#1405);
#1408=CARTESIAN_POINT('',(-3.175,100.6602,0.9652));
#1409=VERTEX_POINT('',#1408);
#1410=EDGE_CURVE('E799',#1409,#1385,#1407,.T.);
#1411=ORIENTED_EDGE('',*,*,#1410,.F.);
#1412=DIRECTION('',(0.,1.,0.));
#1413=VECTOR('',#1412,1.);
#1414=CARTESIAN_POINT('',(-3.175,100.6602,0.9652));
#1415=LINE('',#1414,#1413);
#1416=EDGE_CURVE('E815',#1409,#1253,#1415,.T.);
#1417=ORIENTED_EDGE('',*,*,#1416,.T.);
#1418=EDGE_LOOP('',(#1402,#1403,#1411,#1417));
#1419=FACE_BOUND('',#1418,.T.);
#1420=ADVANCED_FACE('F891',(#1419),#1401,.F.);
#1421=CARTESIAN_POINT('',(-3.175,100.6602,0.));
#1422=DIRECTION('',(0.,1.,0.));
#1423=DIRECTION('',(0.,0.,1.));
#1424=AXIS2_PLACEMENT_3D('',#1421,#1422,#1423);
#1425=CYLINDRICAL_SURFACE('',#1424,0.9652);
#1426=ORIENTED_EDGE('',*,*,#1263,.T.);
#1427=ORIENTED_EDGE('',*,*,#1416,.F.);
#1428=CARTESIAN_POINT('',(-3.175,100.6602,0.));
#1429=DIRECTION('',(0.,1.,0.));
#1430=DIRECTION('',(0.,0.,1.));
#1431=AXIS2_PLACEMENT_3D('',#1428,#1429,#1430);
#1432=CIRCLE('',#1431,0.9652);
#1433=CARTESIAN_POINT('',(-3.175,100.6602,-0.9652));
#1434=VERTEX_POINT('',#1433);
#1435=EDGE_CURVE('E796',#1434,#1409,#1432,.T.);
#1436=ORIENTED_EDGE('',*,*,#1435,.F.);
#1437=DIRECTION('',(0.,1.,0.));
#1438=VECTOR('',#1437,1.);
#1439=CARTESIAN_POINT('',(-3.175,100.6602,-0.9652));
#1440=LINE('',#1439,#1438);
#1441=EDGE_CURVE('E817',#1434,#1262,#1440,.T.);
#1442=ORIENTED_EDGE('',*,*,#1441,.T.);
#1443=EDGE_LOOP('',(#1426,#1427,#1436,#1442));
#1444=FACE_BOUND('',#1443,.T.);
#1445=ADVANCED_FACE('F894',(#1444),#1425,.F.);
#1446=CARTESIAN_POINT('',(-3.175,100.6602,-0.9652));
#1447=DIRECTION('',(0.,0.,-1.));
#1448=DIRECTION('',(-1.,0.,0.));
#1449=AXIS2_PLACEMENT_3D('',#1446,#1447,#1448);
#1450=PLANE('',#1449);
#1451=ORIENTED_EDGE('',*,*,#1269,.T.);
#1452=ORIENTED_EDGE('',*,*,#1441,.F.);
#1453=DIRECTION('',(-1.,0.,0.));
#1454=VECTOR('',#1453,1.);
#1455=CARTESIAN_POINT('',(-3.175,100.6602,-0.9652));
#1456=LINE('',#1455,#1454);
#1457=EDGE_CURVE('E792',#1376,#1434,#1456,.T.);
#1458=ORIENTED_EDGE('',*,*,#1457,.F.);
#1459=ORIENTED_EDGE('',*,*,#1377,.T.);
#1460=EDGE_LOOP('',(#1451,#1452,#1458,#1459));
#1461=FACE_BOUND('',#1460,.T.);
#1462=ADVANCED_FACE('F889',(#1461),#1450,.F.);
#1463=CARTESIAN_POINT('',(3.175,100.6602,0.));
#1464=DIRECTION('',(0.,1.,0.));
#1465=DIRECTION('',(0.,0.,1.));
#1466=AXIS2_PLACEMENT_3D('',#1463,#1464,#1465);
#1467=PLANE('',#1466);
#1468=ORIENTED_EDGE('',*,*,#1386,.T.);
#1469=ORIENTED_EDGE('',*,*,#1457,.T.);
#1470=ORIENTED_EDGE('',*,*,#1435,.T.);
#1471=ORIENTED_EDGE('',*,*,#1410,.T.);
#1472=EDGE_LOOP('',(#1468,#1469,#1470,#1471));
#1473=FACE_BOUND('',#1472,.T.);
#1474=ADVANCED_FACE('F884',(#1473),#1467,.T.);
#1475=CARTESIAN_POINT('',(16.8379802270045,89.5858,-16.8379802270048));
#1476=DIRECTION('',(0.,-1.,0.));
#1477=DIRECTION('',(0.,0.,-1.));
#1478=AXIS2_PLACEMENT_3D('',#1475,#1476,#1477);
#1479=CYLINDRICAL_SURFACE('',#1478,6.1722);
#1480=CARTESIAN_POINT('',(16.8379802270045,68.58,-16.8379802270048));
#1481=DIRECTION('',(0.,1.,0.));
#1482=DIRECTION('',(0.,0.,1.));
#1483=AXIS2_PLACEMENT_3D('',#1480,#1481,#1482);
#1484=CIRCLE('',#1483,6.1722);
#1485=EDGE_CURVE('E785',#498,#387,#1484,.T.);
#1486=ORIENTED_EDGE('',*,*,#1485,.F.);
#1487=ORIENTED_EDGE('',*,*,#499,.F.);
#1488=EDGE_LOOP('',(#1486,#1487));
#1489=FACE_BOUND('',#1488,.T.);
#1490=ADVANCED_FACE('F878',(#1489),#1479,.F.);
#1491=CARTESIAN_POINT('',(16.8379802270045,68.58,-16.8379802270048));
#1492=DIRECTION('',(0.,1.,0.));
#1493=DIRECTION('',(0.,0.,1.));
#1494=AXIS2_PLACEMENT_3D('',#1491,#1492,#1493);
#1495=PLANE('',#1494);
#1496=DIRECTION('',(-0.967859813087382,0.,0.251490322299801));
#1497=VECTOR('',#1496,1.);
#1498=CARTESIAN_POINT('',(15.6741520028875,68.58,-21.3169699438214));
#1499=LINE('',#1498,#1497);
#1500=CARTESIAN_POINT('',(13.0427408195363,68.58,-20.6332196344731));
#1501=VERTEX_POINT('',#1500);
#1502=EDGE_CURVE('E990',#502,#1501,#1499,.T.);
#1503=ORIENTED_EDGE('',*,*,#1502,.F.);
#1504=ORIENTED_EDGE('',*,*,#503,.F.);
#1505=ORIENTED_EDGE('',*,*,#1485,.T.);
#1506=ORIENTED_EDGE('',*,*,#388,.F.);
#1507=DIRECTION('',(0.251490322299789,0.,-0.967859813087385));
#1508=VECTOR('',#1507,1.);
#1509=CARTESIAN_POINT('',(20.6332196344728,68.58,-13.0427408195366));
#1510=LINE('',#1509,#1508);
#1511=CARTESIAN_POINT('',(20.6332196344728,68.58,-13.0427408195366));
#1512=VERTEX_POINT('',#1511);
#1513=EDGE_CURVE('E1284',#1512,#378,#1510,.T.);
#1514=ORIENTED_EDGE('',*,*,#1513,.F.);
#1515=DIRECTION('',(0.965925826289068,0.,-0.258819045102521));
#1516=VECTOR('',#1515,1.);
#1517=CARTESIAN_POINT('',(15.4488261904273,68.58,-11.6535867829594));
#1518=LINE('',#1517,#1516);
#1519=CARTESIAN_POINT('',(15.4488261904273,68.58,-11.6535867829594));
#1520=VERTEX_POINT('',#1519);
#1521=EDGE_CURVE('E1283',#1520,#1512,#1518,.T.);
#1522=ORIENTED_EDGE('',*,*,#1521,.F.);
#1523=DIRECTION('',(0.707106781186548,0.,0.707106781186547));
#1524=VECTOR('',#1523,1.);
#1525=CARTESIAN_POINT('',(11.6535867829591,68.58,-15.4488261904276));
#1526=LINE('',#1525,#1524);
#1527=CARTESIAN_POINT('',(11.6535867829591,68.58,-15.4488261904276));
#1528=VERTEX_POINT('',#1527);
#1529=EDGE_CURVE('E1295',#1528,#1520,#1526,.T.);
#1530=ORIENTED_EDGE('',*,*,#1529,.F.);
#1531=DIRECTION('',(-0.258819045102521,0.,0.965925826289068));
#1532=VECTOR('',#1531,1.);
#1533=CARTESIAN_POINT('',(13.0427408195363,68.58,-20.6332196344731));
#1534=LINE('',#1533,#1532);
#1535=EDGE_CURVE('E993',#1501,#1528,#1534,.T.);
#1536=ORIENTED_EDGE('',*,*,#1535,.F.);
#1537=EDGE_LOOP('',(#1503,#1504,#1505,#1506,#1514,#1522,#1530,#1536));
#1538=FACE_BOUND('',#1537,.T.);
#1539=ADVANCED_FACE('F883',(#1538),#1495,.T.);
#1540=CARTESIAN_POINT('',(16.8379802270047,89.5858,16.8379802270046));
#1541=DIRECTION('',(0.,-1.,0.));
#1542=DIRECTION('',(0.,0.,-1.));
#1543=AXIS2_PLACEMENT_3D('',#1540,#1541,#1542);
#1544=CYLINDRICAL_SURFACE('',#1543,6.1722);
#1545=CARTESIAN_POINT('',(16.8379802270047,68.58,16.8379802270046));
#1546=DIRECTION('',(0.,1.,0.));
#1547=DIRECTION('',(-1.,0.,0.));
#1548=AXIS2_PLACEMENT_3D('',#1545,#1546,#1547);
#1549=CIRCLE('',#1548,6.1722);
#1550=EDGE_CURVE('E782',#340,#229,#1549,.T.);
#1551=ORIENTED_EDGE('',*,*,#1550,.F.);
#1552=ORIENTED_EDGE('',*,*,#341,.F.);
#1553=EDGE_LOOP('',(#1551,#1552));
#1554=FACE_BOUND('',#1553,.T.);
#1555=ADVANCED_FACE('F1244',(#1554),#1544,.F.);
#1556=CARTESIAN_POINT('',(16.8379802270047,68.58,16.8379802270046));
#1557=DIRECTION('',(0.,1.,0.));
#1558=DIRECTION('',(-1.,0.,0.));
#1559=AXIS2_PLACEMENT_3D('',#1556,#1557,#1558);
#1560=PLANE('',#1559);
#1561=DIRECTION('',(-0.251490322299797,0.,-0.967859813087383));
#1562=VECTOR('',#1561,1.);
#1563=CARTESIAN_POINT('',(21.3169699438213,68.58,15.6741520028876));
#1564=LINE('',#1563,#1562);
#1565=CARTESIAN_POINT('',(20.633219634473,68.58,13.0427408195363));
#1566=VERTEX_POINT('',#1565);
#1567=EDGE_CURVE('E994',#344,#1566,#1564,.T.);
#1568=ORIENTED_EDGE('',*,*,#1567,.F.);
#1569=ORIENTED_EDGE('',*,*,#345,.F.);
#1570=ORIENTED_EDGE('',*,*,#1550,.T.);
#1571=ORIENTED_EDGE('',*,*,#230,.F.);
#1572=DIRECTION('',(0.967859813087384,0.,0.251490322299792));
#1573=VECTOR('',#1572,1.);
#1574=CARTESIAN_POINT('',(13.0427408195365,68.58,20.6332196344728));
#1575=LINE('',#1574,#1573);
#1576=CARTESIAN_POINT('',(13.0427408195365,68.58,20.6332196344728));
#1577=VERTEX_POINT('',#1576);
#1578=EDGE_CURVE('E701',#1577,#220,#1575,.T.);
#1579=ORIENTED_EDGE('',*,*,#1578,.F.);
#1580=DIRECTION('',(0.258819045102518,0.,0.965925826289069));
#1581=VECTOR('',#1580,1.);
#1582=CARTESIAN_POINT('',(11.6535867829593,68.58,15.4488261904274));
#1583=LINE('',#1582,#1581);
#1584=CARTESIAN_POINT('',(11.6535867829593,68.58,15.4488261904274));
#1585=VERTEX_POINT('',#1584);
#1586=EDGE_CURVE('E678',#1585,#1577,#1583,.T.);
#1587=ORIENTED_EDGE('',*,*,#1586,.F.);
#1588=DIRECTION('',(-0.70710678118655,0.,0.707106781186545));
#1589=VECTOR('',#1588,1.);
#1590=CARTESIAN_POINT('',(15.4488261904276,68.58,11.6535867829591));
#1591=LINE('',#1590,#1589);
#1592=CARTESIAN_POINT('',(15.4488261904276,68.58,11.6535867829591));
#1593=VERTEX_POINT('',#1592);
#1594=EDGE_CURVE('E688',#1593,#1585,#1591,.T.);
#1595=ORIENTED_EDGE('',*,*,#1594,.F.);
#1596=DIRECTION('',(-0.965925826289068,0.,-0.258819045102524));
#1597=VECTOR('',#1596,1.);
#1598=CARTESIAN_POINT('',(20.633219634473,68.58,13.0427408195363));
#1599=LINE('',#1598,#1597);
#1600=EDGE_CURVE('E703',#1566,#1593,#1599,.T.);
#1601=ORIENTED_EDGE('',*,*,#1600,.F.);
#1602=EDGE_LOOP('',(#1568,#1569,#1570,#1571,#1579,#1587,#1595,#1601));
#1603=FACE_BOUND('',#1602,.T.);
#1604=ADVANCED_FACE('F1241',(#1603),#1560,.T.);
#1605=CARTESIAN_POINT('',(-16.8379802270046,89.5858,16.8379802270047));
#1606=DIRECTION('',(0.,-1.,0.));
#1607=DIRECTION('',(0.,0.,-1.));
#1608=AXIS2_PLACEMENT_3D('',#1605,#1606,#1607);
#1609=CYLINDRICAL_SURFACE('',#1608,6.1722);
#1610=CARTESIAN_POINT('',(-16.8379802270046,68.58,16.8379802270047));
#1611=DIRECTION('',(0.,1.,0.));
#1612=DIRECTION('',(0.,0.,-1.));
#1613=AXIS2_PLACEMENT_3D('',#1610,#1611,#1612);
#1614=CIRCLE('',#1613,6.1722);
#1615=EDGE_CURVE('E779',#182,#71,#1614,.T.);
#1616=ORIENTED_EDGE('',*,*,#1615,.F.);
#1617=ORIENTED_EDGE('',*,*,#183,.F.);
#1618=EDGE_LOOP('',(#1616,#1617));
#1619=FACE_BOUND('',#1618,.T.);
#1620=ADVANCED_FACE('F1235',(#1619),#1609,.F.);
#1621=CARTESIAN_POINT('',(-16.8379802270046,68.58,16.8379802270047));
#1622=DIRECTION('',(0.,1.,0.));
#1623=DIRECTION('',(0.,0.,-1.));
#1624=AXIS2_PLACEMENT_3D('',#1621,#1622,#1623);
#1625=PLANE('',#1624);
#1626=DIRECTION('',(0.967859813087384,0.,-0.251490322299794));
#1627=VECTOR('',#1626,1.);
#1628=CARTESIAN_POINT('',(-15.6741520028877,68.58,21.3169699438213));
#1629=LINE('',#1628,#1627);
#1630=CARTESIAN_POINT('',(-13.0427408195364,68.58,20.633219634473));
#1631=VERTEX_POINT('',#1630);
#1632=EDGE_CURVE('E997',#186,#1631,#1629,.T.);
#1633=ORIENTED_EDGE('',*,*,#1632,.F.);
#1634=ORIENTED_EDGE('',*,*,#187,.F.);
#1635=ORIENTED_EDGE('',*,*,#1615,.T.);
#1636=ORIENTED_EDGE('',*,*,#72,.F.);
#1637=DIRECTION('',(-0.251490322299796,0.,0.967859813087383));
#1638=VECTOR('',#1637,1.);
#1639=CARTESIAN_POINT('',(-20.6332196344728,68.58,13.0427408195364));
#1640=LINE('',#1639,#1638);
#1641=CARTESIAN_POINT('',(-20.6332196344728,68.58,13.0427408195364));
#1642=VERTEX_POINT('',#1641);
#1643=EDGE_CURVE('E2091',#1642,#62,#1640,.T.);
#1644=ORIENTED_EDGE('',*,*,#1643,.F.);
#1645=DIRECTION('',(-0.96592582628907,0.,0.258819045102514));
#1646=VECTOR('',#1645,1.);
#1647=CARTESIAN_POINT('',(-15.4488261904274,68.58,11.6535867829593));
#1648=LINE('',#1647,#1646);
#1649=CARTESIAN_POINT('',(-15.4488261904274,68.58,11.6535867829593));
#1650=VERTEX_POINT('',#1649);
#1651=EDGE_CURVE('E957',#1650,#1642,#1648,.T.);
#1652=ORIENTED_EDGE('',*,*,#1651,.F.);
#1653=DIRECTION('',(-0.707106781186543,0.,-0.707106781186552));
#1654=VECTOR('',#1653,1.);
#1655=CARTESIAN_POINT('',(-11.6535867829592,68.58,15.4488261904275));
#1656=LINE('',#1655,#1654);
#1657=CARTESIAN_POINT('',(-11.6535867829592,68.58,15.4488261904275));
#1658=VERTEX_POINT('',#1657);
#1659=EDGE_CURVE('E2096',#1658,#1650,#1656,.T.);
#1660=ORIENTED_EDGE('',*,*,#1659,.F.);
#1661=DIRECTION('',(0.258819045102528,0.,-0.965925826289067));
#1662=VECTOR('',#1661,1.);
#1663=CARTESIAN_POINT('',(-13.0427408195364,68.58,20.633219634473));
#1664=LINE('',#1663,#1662);
#1665=EDGE_CURVE('E2093',#1631,#1658,#1664,.T.);
#1666=ORIENTED_EDGE('',*,*,#1665,.F.);
#1667=EDGE_LOOP('',(#1633,#1634,#1635,#1636,#1644,#1652,#1660,#1666));
#1668=FACE_BOUND('',#1667,.T.);
#1669=ADVANCED_FACE('F1240',(#1668),#1625,.T.);
#1670=CARTESIAN_POINT('',(-16.8379802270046,89.5858,-16.8379802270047));
#1671=DIRECTION('',(0.,-1.,0.));
#1672=DIRECTION('',(0.,0.,-1.));
#1673=AXIS2_PLACEMENT_3D('',#1670,#1671,#1672);
#1674=CYLINDRICAL_SURFACE('',#1673,6.1722);
#1675=CARTESIAN_POINT('',(-16.8379802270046,68.58,-16.8379802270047));
#1676=DIRECTION('',(0.,1.,0.));
#1677=DIRECTION('',(1.,0.,0.));
#1678=AXIS2_PLACEMENT_3D('',#1675,#1676,#1677);
#1679=CIRCLE('',#1678,6.1722);
#1680=EDGE_CURVE('E771',#656,#545,#1679,.T.);
#1681=ORIENTED_EDGE('',*,*,#1680,.F.);
#1682=ORIENTED_EDGE('',*,*,#657,.F.);
#1683=EDGE_LOOP('',(#1681,#1682));
#1684=FACE_BOUND('',#1683,.T.);
#1685=ADVANCED_FACE('F1225',(#1684),#1674,.F.);
#1686=CARTESIAN_POINT('',(-16.8379802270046,68.58,-16.8379802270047));
#1687=DIRECTION('',(0.,1.,0.));
#1688=DIRECTION('',(1.,0.,0.));
#1689=AXIS2_PLACEMENT_3D('',#1686,#1687,#1688);
#1690=PLANE('',#1689);
#1691=DIRECTION('',(0.25149032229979,0.,0.967859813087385));
#1692=VECTOR('',#1691,1.);
#1693=CARTESIAN_POINT('',(-21.3169699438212,68.58,-15.6741520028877));
#1694=LINE('',#1693,#1692);
#1695=CARTESIAN_POINT('',(-20.6332196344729,68.58,-13.0427408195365));
#1696=VERTEX_POINT('',#1695);
#1697=EDGE_CURVE('E1007',#38,#1696,#1694,.T.);
#1698=ORIENTED_EDGE('',*,*,#1697,.F.);
#1699=ORIENTED_EDGE('',*,*,#659,.F.);
#1700=ORIENTED_EDGE('',*,*,#1680,.T.);
#1701=ORIENTED_EDGE('',*,*,#546,.F.);
#1702=DIRECTION('',(-0.967859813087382,0.,-0.251490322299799));
#1703=VECTOR('',#1702,1.);
#1704=CARTESIAN_POINT('',(-13.0427408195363,68.58,-20.6332196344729));
#1705=LINE('',#1704,#1703);
#1706=CARTESIAN_POINT('',(-13.0427408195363,68.58,-20.6332196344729));
#1707=VERTEX_POINT('',#1706);
#1708=EDGE_CURVE('E602',#1707,#536,#1705,.T.);
#1709=ORIENTED_EDGE('',*,*,#1708,.F.);
#1710=DIRECTION('',(-0.258819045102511,0.,-0.965925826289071));
#1711=VECTOR('',#1710,1.);
#1712=CARTESIAN_POINT('',(-11.6535867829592,68.58,-15.4488261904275));
#1713=LINE('',#1712,#1711);
#1714=CARTESIAN_POINT('',(-11.6535867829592,68.58,-15.4488261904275));
#1715=VERTEX_POINT('',#1714);
#1716=EDGE_CURVE('E574',#1715,#1707,#1713,.T.);
#1717=ORIENTED_EDGE('',*,*,#1716,.F.);
#1718=DIRECTION('',(0.707106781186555,0.,-0.70710678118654));
#1719=VECTOR('',#1718,1.);
#1720=CARTESIAN_POINT('',(-15.4488261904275,68.58,-11.6535867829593));
#1721=LINE('',#1720,#1719);
#1722=CARTESIAN_POINT('',(-15.4488261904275,68.58,-11.6535867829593));
#1723=VERTEX_POINT('',#1722);
#1724=EDGE_CURVE('E589',#1723,#1715,#1721,.T.);
#1725=ORIENTED_EDGE('',*,*,#1724,.F.);
#1726=DIRECTION('',(0.965925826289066,0.,0.258819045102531));
#1727=VECTOR('',#1726,1.);
#1728=CARTESIAN_POINT('',(-20.6332196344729,68.58,-13.0427408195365));
#1729=LINE('',#1728,#1727);
#1730=EDGE_CURVE('E604',#1696,#1723,#1729,.T.);
#1731=ORIENTED_EDGE('',*,*,#1730,.F.);
#1732=EDGE_LOOP('',(#1698,#1699,#1700,#1701,#1709,#1717,#1725,#1731));
#1733=FACE_BOUND('',#1732,.T.);
#1734=ADVANCED_FACE('F746',(#1733),#1690,.T.);
#1735=CARTESIAN_POINT('',(20.6332196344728,62.23,-13.0427408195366));
#1736=DIRECTION('',(0.,1.,0.));
#1737=DIRECTION('',(0.,0.,1.));
#1738=AXIS2_PLACEMENT_3D('',#1735,#1736,#1737);
#1739=PLANE('',#1738);
#1740=CARTESIAN_POINT('',(16.8379802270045,62.23,-16.8379802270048));
#1741=DIRECTION('',(0.,1.,0.));
#1742=DIRECTION('',(0.,0.,1.));
#1743=AXIS2_PLACEMENT_3D('',#1740,#1741,#1742);
#1744=CIRCLE('',#1743,3.9624);
#1745=CARTESIAN_POINT('',(16.8379802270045,62.23,-12.8755802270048));
#1746=VERTEX_POINT('',#1745);
#1747=EDGE_CURVE('E1009',#1746,#1746,#1744,.T.);
#1748=ORIENTED_EDGE('',*,*,#1747,.F.);
#1749=EDGE_LOOP('',(#1748));
#1750=FACE_BOUND('',#1749,.T.);
#1751=ORIENTED_EDGE('',*,*,#1102,.F.);
#1752=DIRECTION('',(-0.967859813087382,0.,0.251490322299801));
#1753=VECTOR('',#1752,1.);
#1754=CARTESIAN_POINT('',(23.2979505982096,62.23,-23.29795059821));
#1755=LINE('',#1754,#1753);
#1756=CARTESIAN_POINT('',(13.0427408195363,62.23,-20.6332196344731));
#1757=VERTEX_POINT('',#1756);
#1758=EDGE_CURVE('E973',#517,#1757,#1755,.T.);
#1759=ORIENTED_EDGE('',*,*,#1758,.T.);
#1760=DIRECTION('',(-0.258819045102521,0.,0.965925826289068));
#1761=VECTOR('',#1760,1.);
#1762=CARTESIAN_POINT('',(13.0427408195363,62.23,-20.6332196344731));
#1763=LINE('',#1762,#1761);
#1764=CARTESIAN_POINT('',(11.6535867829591,62.23,-15.4488261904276));
#1765=VERTEX_POINT('',#1764);
#1766=EDGE_CURVE('E983',#1757,#1765,#1763,.T.);
#1767=ORIENTED_EDGE('',*,*,#1766,.T.);
#1768=DIRECTION('',(0.707106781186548,0.,0.707106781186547));
#1769=VECTOR('',#1768,1.);
#1770=CARTESIAN_POINT('',(11.6535867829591,62.23,-15.4488261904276));
#1771=LINE('',#1770,#1769);
#1772=CARTESIAN_POINT('',(15.4488261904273,62.23,-11.6535867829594));
#1773=VERTEX_POINT('',#1772);
#1774=EDGE_CURVE('E1291',#1765,#1773,#1771,.T.);
#1775=ORIENTED_EDGE('',*,*,#1774,.T.);
#1776=DIRECTION('',(0.965925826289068,0.,-0.258819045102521));
#1777=VECTOR('',#1776,1.);
#1778=CARTESIAN_POINT('',(15.4488261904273,62.23,-11.6535867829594));
#1779=LINE('',#1778,#1777);
#1780=CARTESIAN_POINT('',(20.6332196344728,62.23,-13.0427408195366));
#1781=VERTEX_POINT('',#1780);
#1782=EDGE_CURVE('E1298',#1773,#1781,#1779,.T.);
#1783=ORIENTED_EDGE('',*,*,#1782,.T.);
#1784=DIRECTION('',(0.251490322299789,0.,-0.967859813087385));
#1785=VECTOR('',#1784,1.);
#1786=CARTESIAN_POINT('',(20.6332196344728,62.23,-13.0427408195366));
#1787=LINE('',#1786,#1785);
#1788=EDGE_CURVE('E977',#1781,#363,#1787,.T.);
#1789=ORIENTED_EDGE('',*,*,#1788,.T.);
#1790=EDGE_LOOP('',(#1751,#1759,#1767,#1775,#1783,#1789));
#1791=FACE_BOUND('',#1790,.T.);
#1792=ADVANCED_FACE('F742',(#1750,#1791),#1739,.T.);
#1793=CARTESIAN_POINT('',(15.4488261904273,62.23,-11.6535867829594));
#1794=DIRECTION('',(0.258819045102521,0.,0.965925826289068));
#1795=DIRECTION('',(0.965925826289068,0.,-0.258819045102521));
#1796=AXIS2_PLACEMENT_3D('',#1793,#1794,#1795);
#1797=PLANE('',#1796);
#1798=ORIENTED_EDGE('',*,*,#1521,.T.);
#1799=DIRECTION('',(0.,1.,0.));
#1800=VECTOR('',#1799,1.);
#1801=CARTESIAN_POINT('',(20.6332196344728,62.23,-13.0427408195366));
#1802=LINE('',#1801,#1800);
#1803=EDGE_CURVE('E1303',#1781,#1512,#1802,.T.);
#1804=ORIENTED_EDGE('',*,*,#1803,.F.);
#1805=ORIENTED_EDGE('',*,*,#1782,.F.);
#1806=DIRECTION('',(0.,1.,0.));
#1807=VECTOR('',#1806,1.);
#1808=CARTESIAN_POINT('',(15.4488261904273,62.23,-11.6535867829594));
#1809=LINE('',#1808,#1807);
#1810=EDGE_CURVE('E1299',#1773,#1520,#1809,.T.);
#1811=ORIENTED_EDGE('',*,*,#1810,.T.);
#1812=EDGE_LOOP('',(#1798,#1804,#1805,#1811));
#1813=FACE_BOUND('',#1812,.T.);
#1814=ADVANCED_FACE('F745',(#1813),#1797,.F.);
#1815=CARTESIAN_POINT('',(11.6535867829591,62.23,-15.4488261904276));
#1816=DIRECTION('',(-0.707106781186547,0.,0.707106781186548));
#1817=DIRECTION('',(0.707106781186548,0.,0.707106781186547));
#1818=AXIS2_PLACEMENT_3D('',#1815,#1816,#1817);
#1819=PLANE('',#1818);
#1820=ORIENTED_EDGE('',*,*,#1529,.T.);
#1821=ORIENTED_EDGE('',*,*,#1810,.F.);
#1822=ORIENTED_EDGE('',*,*,#1774,.F.);
#1823=DIRECTION('',(0.,1.,0.));
#1824=VECTOR('',#1823,1.);
#1825=CARTESIAN_POINT('',(11.6535867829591,62.23,-15.4488261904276));
#1826=LINE('',#1825,#1824);
#1827=EDGE_CURVE('E1301',#1765,#1528,#1826,.T.);
#1828=ORIENTED_EDGE('',*,*,#1827,.T.);
#1829=EDGE_LOOP('',(#1820,#1821,#1822,#1828));
#1830=FACE_BOUND('',#1829,.T.);
#1831=ADVANCED_FACE('F748',(#1830),#1819,.F.);
#1832=CARTESIAN_POINT('',(13.0427408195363,62.23,-20.6332196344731));
#1833=DIRECTION('',(-0.965925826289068,0.,-0.258819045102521));
#1834=DIRECTION('',(-0.258819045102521,0.,0.965925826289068));
#1835=AXIS2_PLACEMENT_3D('',#1832,#1833,#1834);
#1836=PLANE('',#1835);
#1837=ORIENTED_EDGE('',*,*,#1535,.T.);
#1838=ORIENTED_EDGE('',*,*,#1827,.F.);
#1839=ORIENTED_EDGE('',*,*,#1766,.F.);
#1840=DIRECTION('',(0.,1.,0.));
#1841=VECTOR('',#1840,1.);
#1842=CARTESIAN_POINT('',(13.0427408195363,62.23,-20.6332196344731));
#1843=LINE('',#1842,#1841);
#1844=EDGE_CURVE('E981',#1757,#1501,#1843,.T.);
#1845=ORIENTED_EDGE('',*,*,#1844,.T.);
#1846=EDGE_LOOP('',(#1837,#1838,#1839,#1845));
#1847=FACE_BOUND('',#1846,.T.);
#1848=ADVANCED_FACE('F751',(#1847),#1836,.F.);
#1849=CARTESIAN_POINT('',(23.2979505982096,62.23,-23.29795059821));
#1850=DIRECTION('',(-0.251490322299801,0.,-0.967859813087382));
#1851=DIRECTION('',(-0.967859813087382,0.,0.251490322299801));
#1852=AXIS2_PLACEMENT_3D('',#1849,#1850,#1851);
#1853=PLANE('',#1852);
#1854=ORIENTED_EDGE('',*,*,#518,.T.);
#1855=ORIENTED_EDGE('',*,*,#1502,.T.);
#1856=ORIENTED_EDGE('',*,*,#1844,.F.);
#1857=ORIENTED_EDGE('',*,*,#1758,.F.);
#1858=EDGE_LOOP('',(#1854,#1855,#1856,#1857));
#1859=FACE_BOUND('',#1858,.T.);
#1860=ADVANCED_FACE('F755',(#1859),#1853,.F.);
#1861=CARTESIAN_POINT('',(20.6332196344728,62.23,-13.0427408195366));
#1862=DIRECTION('',(0.967859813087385,0.,0.251490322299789));
#1863=DIRECTION('',(0.251490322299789,0.,-0.967859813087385));
#1864=AXIS2_PLACEMENT_3D('',#1861,#1862,#1863);
#1865=PLANE('',#1864);
#1866=ORIENTED_EDGE('',*,*,#379,.T.);
#1867=ORIENTED_EDGE('',*,*,#1788,.F.);
#1868=ORIENTED_EDGE('',*,*,#1803,.T.);
#1869=ORIENTED_EDGE('',*,*,#1513,.T.);
#1870=EDGE_LOOP('',(#1866,#1867,#1868,#1869));
#1871=FACE_BOUND('',#1870,.T.);
#1872=ADVANCED_FACE('F760',(#1871),#1865,.F.);
#1873=CARTESIAN_POINT('',(13.0427408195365,62.23,20.6332196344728));
#1874=DIRECTION('',(0.,1.,0.));
#1875=DIRECTION('',(-1.,0.,0.));
#1876=AXIS2_PLACEMENT_3D('',#1873,#1874,#1875);
#1877=PLANE('',#1876);
#1878=CARTESIAN_POINT('',(16.8379802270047,62.23,16.8379802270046));
#1879=DIRECTION('',(0.,1.,0.));
#1880=DIRECTION('',(0.,0.,1.));
#1881=AXIS2_PLACEMENT_3D('',#1878,#1879,#1880);
#1882=CIRCLE('',#1881,3.9624);
#1883=CARTESIAN_POINT('',(16.8379802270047,62.23,20.8003802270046));
#1884=VERTEX_POINT('',#1883);
#1885=EDGE_CURVE('E1012',#1884,#1884,#1882,.T.);
#1886=ORIENTED_EDGE('',*,*,#1885,.F.);
#1887=EDGE_LOOP('',(#1886));
#1888=FACE_BOUND('',#1887,.T.);
#1889=ORIENTED_EDGE('',*,*,#1105,.F.);
#1890=DIRECTION('',(-0.251490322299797,0.,-0.967859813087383));
#1891=VECTOR('',#1890,1.);
#1892=CARTESIAN_POINT('',(23.2979505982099,62.23,23.2979505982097));
#1893=LINE('',#1892,#1891);
#1894=CARTESIAN_POINT('',(20.633219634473,62.23,13.0427408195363));
#1895=VERTEX_POINT('',#1894);
#1896=EDGE_CURVE('E691',#359,#1895,#1893,.T.);
#1897=ORIENTED_EDGE('',*,*,#1896,.T.);
#1898=DIRECTION('',(-0.965925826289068,0.,-0.258819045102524));
#1899=VECTOR('',#1898,1.);
#1900=CARTESIAN_POINT('',(20.633219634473,62.23,13.0427408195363));
#1901=LINE('',#1900,#1899);
#1902=CARTESIAN_POINT('',(15.4488261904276,62.23,11.6535867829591));
#1903=VERTEX_POINT('',#1902);
#1904=EDGE_CURVE('E693',#1895,#1903,#1901,.T.);
#1905=ORIENTED_EDGE('',*,*,#1904,.T.);
#1906=DIRECTION('',(-0.70710678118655,0.,0.707106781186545));
#1907=VECTOR('',#1906,1.);
#1908=CARTESIAN_POINT('',(15.4488261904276,62.23,11.6535867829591));
#1909=LINE('',#1908,#1907);
#1910=CARTESIAN_POINT('',(11.6535867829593,62.23,15.4488261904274));
#1911=VERTEX_POINT('',#1910);
#1912=EDGE_CURVE('E696',#1903,#1911,#1909,.T.);
#1913=ORIENTED_EDGE('',*,*,#1912,.T.);
#1914=DIRECTION('',(0.258819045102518,0.,0.965925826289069));
#1915=VECTOR('',#1914,1.);
#1916=CARTESIAN_POINT('',(11.6535867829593,62.23,15.4488261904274));
#1917=LINE('',#1916,#1915);
#1918=CARTESIAN_POINT('',(13.0427408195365,62.23,20.6332196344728));
#1919=VERTEX_POINT('',#1918);
#1920=EDGE_CURVE('E684',#1911,#1919,#1917,.T.);
#1921=ORIENTED_EDGE('',*,*,#1920,.T.);
#1922=DIRECTION('',(0.967859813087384,0.,0.251490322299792));
#1923=VECTOR('',#1922,1.);
#1924=CARTESIAN_POINT('',(13.0427408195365,62.23,20.6332196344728));
#1925=LINE('',#1924,#1923);
#1926=EDGE_CURVE('E687',#1919,#205,#1925,.T.);
#1927=ORIENTED_EDGE('',*,*,#1926,.T.);
#1928=EDGE_LOOP('',(#1889,#1897,#1905,#1913,#1921,#1927));
#1929=FACE_BOUND('',#1928,.T.);
#1930=ADVANCED_FACE('F740',(#1888,#1929),#1877,.T.);
#1931=CARTESIAN_POINT('',(11.6535867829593,62.23,15.4488261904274));
#1932=DIRECTION('',(-0.965925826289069,0.,0.258819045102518));
#1933=DIRECTION('',(0.258819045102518,0.,0.965925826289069));
#1934=AXIS2_PLACEMENT_3D('',#1931,#1932,#1933);
#1935=PLANE('',#1934);
#1936=ORIENTED_EDGE('',*,*,#1586,.T.);
#1937=DIRECTION('',(0.,1.,0.));
#1938=VECTOR('',#1937,1.);
#1939=CARTESIAN_POINT('',(13.0427408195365,62.23,20.6332196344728));
#1940=LINE('',#1939,#1938);
#1941=EDGE_CURVE('E699',#1919,#1577,#1940,.T.);
#1942=ORIENTED_EDGE('',*,*,#1941,.F.);
#1943=ORIENTED_EDGE('',*,*,#1920,.F.);
#1944=DIRECTION('',(0.,1.,0.));
#1945=VECTOR('',#1944,1.);
#1946=CARTESIAN_POINT('',(11.6535867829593,62.23,15.4488261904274));
#1947=LINE('',#1946,#1945);
#1948=EDGE_CURVE('E708',#1911,#1585,#1947,.T.);
#1949=ORIENTED_EDGE('',*,*,#1948,.T.);
#1950=EDGE_LOOP('',(#1936,#1942,#1943,#1949));
#1951=FACE_BOUND('',#1950,.T.);
#1952=ADVANCED_FACE('F736',(#1951),#1935,.F.);
#1953=CARTESIAN_POINT('',(15.4488261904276,62.23,11.6535867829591));
#1954=DIRECTION('',(-0.707106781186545,0.,-0.70710678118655));
#1955=DIRECTION('',(-0.70710678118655,0.,0.707106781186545));
#1956=AXIS2_PLACEMENT_3D('',#1953,#1954,#1955);
#1957=PLANE('',#1956);
#1958=ORIENTED_EDGE('',*,*,#1594,.T.);
#1959=ORIENTED_EDGE('',*,*,#1948,.F.);
#1960=ORIENTED_EDGE('',*,*,#1912,.F.);
#1961=DIRECTION('',(0.,1.,0.));
#1962=VECTOR('',#1961,1.);
#1963=CARTESIAN_POINT('',(15.4488261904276,62.23,11.6535867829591));
#1964=LINE('',#1963,#1962);
#1965=EDGE_CURVE('E711',#1903,#1593,#1964,.T.);
#1966=ORIENTED_EDGE('',*,*,#1965,.T.);
#1967=EDGE_LOOP('',(#1958,#1959,#1960,#1966));
#1968=FACE_BOUND('',#1967,.T.);
#1969=ADVANCED_FACE('F739',(#1968),#1957,.F.);
#1970=CARTESIAN_POINT('',(20.633219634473,62.23,13.0427408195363));
#1971=DIRECTION('',(0.258819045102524,0.,-0.965925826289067));
#1972=DIRECTION('',(-0.965925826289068,0.,-0.258819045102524));
#1973=AXIS2_PLACEMENT_3D('',#1970,#1971,#1972);
#1974=PLANE('',#1973);
#1975=ORIENTED_EDGE('',*,*,#1600,.T.);
#1976=ORIENTED_EDGE('',*,*,#1965,.F.);
#1977=ORIENTED_EDGE('',*,*,#1904,.F.);
#1978=DIRECTION('',(0.,1.,0.));
#1979=VECTOR('',#1978,1.);
#1980=CARTESIAN_POINT('',(20.633219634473,62.23,13.0427408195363));
#1981=LINE('',#1980,#1979);
#1982=EDGE_CURVE('E713',#1895,#1566,#1981,.T.);
#1983=ORIENTED_EDGE('',*,*,#1982,.T.);
#1984=EDGE_LOOP('',(#1975,#1976,#1977,#1983));
#1985=FACE_BOUND('',#1984,.T.);
#1986=ADVANCED_FACE('F1271',(#1985),#1974,.F.);
#1987=CARTESIAN_POINT('',(23.2979505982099,62.23,23.2979505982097));
#1988=DIRECTION('',(0.967859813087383,0.,-0.251490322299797));
#1989=DIRECTION('',(-0.251490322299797,0.,-0.967859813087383));
#1990=AXIS2_PLACEMENT_3D('',#1987,#1988,#1989);
#1991=PLANE('',#1990);
#1992=ORIENTED_EDGE('',*,*,#360,.T.);
#1993=ORIENTED_EDGE('',*,*,#1567,.T.);
#1994=ORIENTED_EDGE('',*,*,#1982,.F.);
#1995=ORIENTED_EDGE('',*,*,#1896,.F.);
#1996=EDGE_LOOP('',(#1992,#1993,#1994,#1995));
#1997=FACE_BOUND('',#1996,.T.);
#1998=ADVANCED_FACE('F732',(#1997),#1991,.F.);
#1999=CARTESIAN_POINT('',(13.0427408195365,62.23,20.6332196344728));
#2000=DIRECTION('',(-0.251490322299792,0.,0.967859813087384));
#2001=DIRECTION('',(0.967859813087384,0.,0.251490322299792));
#2002=AXIS2_PLACEMENT_3D('',#1999,#2000,#2001);
#2003=PLANE('',#2002);
#2004=ORIENTED_EDGE('',*,*,#221,.T.);
#2005=ORIENTED_EDGE('',*,*,#1926,.F.);
#2006=ORIENTED_EDGE('',*,*,#1941,.T.);
#2007=ORIENTED_EDGE('',*,*,#1578,.T.);
#2008=EDGE_LOOP('',(#2004,#2005,#2006,#2007));
#2009=FACE_BOUND('',#2008,.T.);
#2010=ADVANCED_FACE('F653',(#2009),#2003,.F.);
#2011=CARTESIAN_POINT('',(-20.6332196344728,62.23,13.0427408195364));
#2012=DIRECTION('',(0.,1.,0.));
#2013=DIRECTION('',(0.,0.,-1.));
#2014=AXIS2_PLACEMENT_3D('',#2011,#2012,#2013);
#2015=PLANE('',#2014);
#2016=CARTESIAN_POINT('',(-16.8379802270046,62.23,16.8379802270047));
#2017=DIRECTION('',(0.,1.,0.));
#2018=DIRECTION('',(0.,0.,1.));
#2019=AXIS2_PLACEMENT_3D('',#2016,#2017,#2018);
#2020=CIRCLE('',#2019,3.9624);
#2021=CARTESIAN_POINT('',(-16.8379802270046,62.23,20.8003802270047));
#2022=VERTEX_POINT('',#2021);
#2023=EDGE_CURVE('E1015',#2022,#2022,#2020,.T.);
#2024=ORIENTED_EDGE('',*,*,#2023,.F.);
#2025=EDGE_LOOP('',(#2024));
#2026=FACE_BOUND('',#2025,.T.);
#2027=ORIENTED_EDGE('',*,*,#1108,.F.);
#2028=DIRECTION('',(0.967859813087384,0.,-0.251490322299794));
#2029=VECTOR('',#2028,1.);
#2030=CARTESIAN_POINT('',(-23.2979505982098,62.23,23.2979505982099));
#2031=LINE('',#2030,#2029);
#2032=CARTESIAN_POINT('',(-13.0427408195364,62.23,20.633219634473));
#2033=VERTEX_POINT('',#2032);
#2034=EDGE_CURVE('E2071',#201,#2033,#2031,.T.);
#2035=ORIENTED_EDGE('',*,*,#2034,.T.);
#2036=DIRECTION('',(0.258819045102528,0.,-0.965925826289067));
#2037=VECTOR('',#2036,1.);
#2038=CARTESIAN_POINT('',(-13.0427408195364,62.23,20.633219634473));
#2039=LINE('',#2038,#2037);
#2040=CARTESIAN_POINT('',(-11.6535867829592,62.23,15.4488261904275));
#2041=VERTEX_POINT('',#2040);
#2042=EDGE_CURVE('E2080',#2033,#2041,#2039,.T.);
#2043=ORIENTED_EDGE('',*,*,#2042,.T.);
#2044=DIRECTION('',(-0.707106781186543,0.,-0.707106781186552));
#2045=VECTOR('',#2044,1.);
#2046=CARTESIAN_POINT('',(-11.6535867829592,62.23,15.4488261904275));
#2047=LINE('',#2046,#2045);
#2048=CARTESIAN_POINT('',(-15.4488261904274,62.23,11.6535867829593));
#2049=VERTEX_POINT('',#2048);
#2050=EDGE_CURVE('E2082',#2041,#2049,#2047,.T.);
#2051=ORIENTED_EDGE('',*,*,#2050,.T.);
#2052=DIRECTION('',(-0.96592582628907,0.,0.258819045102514));
#2053=VECTOR('',#2052,1.);
#2054=CARTESIAN_POINT('',(-15.4488261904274,62.23,11.6535867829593));
#2055=LINE('',#2054,#2053);
#2056=CARTESIAN_POINT('',(-20.6332196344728,62.23,13.0427408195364));
#2057=VERTEX_POINT('',#2056);
#2058=EDGE_CURVE('E2084',#2049,#2057,#2055,.T.);
#2059=ORIENTED_EDGE('',*,*,#2058,.T.);
#2060=DIRECTION('',(-0.251490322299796,0.,0.967859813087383));
#2061=VECTOR('',#2060,1.);
#2062=CARTESIAN_POINT('',(-20.6332196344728,62.23,13.0427408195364));
#2063=LINE('',#2062,#2061);
#2064=EDGE_CURVE('E2075',#2057,#47,#2063,.T.);
#2065=ORIENTED_EDGE('',*,*,#2064,.T.);
#2066=EDGE_LOOP('',(#2027,#2035,#2043,#2051,#2059,#2065));
#2067=FACE_BOUND('',#2066,.T.);
#2068=ADVANCED_FACE('F649',(#2026,#2067),#2015,.T.);
#2069=CARTESIAN_POINT('',(-15.4488261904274,62.23,11.6535867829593));
#2070=DIRECTION('',(-0.258819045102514,0.,-0.96592582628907));
#2071=DIRECTION('',(-0.96592582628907,0.,0.258819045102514));
#2072=AXIS2_PLACEMENT_3D('',#2069,#2070,#2071);
#2073=PLANE('',#2072);
#2074=ORIENTED_EDGE('',*,*,#1651,.T.);
#2075=DIRECTION('',(0.,1.,0.));
#2076=VECTOR('',#2075,1.);
#2077=CARTESIAN_POINT('',(-20.6332196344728,62.23,13.0427408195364));
#2078=LINE('',#2077,#2076);
#2079=EDGE_CURVE('E2089',#2057,#1642,#2078,.T.);
#2080=ORIENTED_EDGE('',*,*,#2079,.F.);
#2081=ORIENTED_EDGE('',*,*,#2058,.F.);
#2082=DIRECTION('',(0.,1.,0.));
#2083=VECTOR('',#2082,1.);
#2084=CARTESIAN_POINT('',(-15.4488261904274,62.23,11.6535867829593));
#2085=LINE('',#2084,#2083);
#2086=EDGE_CURVE('E2099',#2049,#1650,#2085,.T.);
#2087=ORIENTED_EDGE('',*,*,#2086,.T.);
#2088=EDGE_LOOP('',(#2074,#2080,#2081,#2087));
#2089=FACE_BOUND('',#2088,.T.);
#2090=ADVANCED_FACE('F652',(#2089),#2073,.F.);
#2091=CARTESIAN_POINT('',(-11.6535867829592,62.23,15.4488261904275));
#2092=DIRECTION('',(0.707106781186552,0.,-0.707106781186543));
#2093=DIRECTION('',(-0.707106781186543,0.,-0.707106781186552));
#2094=AXIS2_PLACEMENT_3D('',#2091,#2092,#2093);
#2095=PLANE('',#2094);
#2096=ORIENTED_EDGE('',*,*,#1659,.T.);
#2097=ORIENTED_EDGE('',*,*,#2086,.F.);
#2098=ORIENTED_EDGE('',*,*,#2050,.F.);
#2099=DIRECTION('',(0.,1.,0.));
#2100=VECTOR('',#2099,1.);
#2101=CARTESIAN_POINT('',(-11.6535867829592,62.23,15.4488261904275));
#2102=LINE('',#2101,#2100);
#2103=EDGE_CURVE('E2101',#2041,#1658,#2102,.T.);
#2104=ORIENTED_EDGE('',*,*,#2103,.T.);
#2105=EDGE_LOOP('',(#2096,#2097,#2098,#2104));
#2106=FACE_BOUND('',#2105,.T.);
#2107=ADVANCED_FACE('F655',(#2106),#2095,.F.);
#2108=CARTESIAN_POINT('',(-13.0427408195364,62.23,20.633219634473));
#2109=DIRECTION('',(0.965925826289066,0.,0.258819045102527));
#2110=DIRECTION('',(0.258819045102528,0.,-0.965925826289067));
#2111=AXIS2_PLACEMENT_3D('',#2108,#2109,#2110);
#2112=PLANE('',#2111);
#2113=ORIENTED_EDGE('',*,*,#1665,.T.);
#2114=ORIENTED_EDGE('',*,*,#2103,.F.);
#2115=ORIENTED_EDGE('',*,*,#2042,.F.);
#2116=DIRECTION('',(0.,1.,0.));
#2117=VECTOR('',#2116,1.);
#2118=CARTESIAN_POINT('',(-13.0427408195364,62.23,20.633219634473));
#2119=LINE('',#2118,#2117);
#2120=EDGE_CURVE('E2078',#2033,#1631,#2119,.T.);
#2121=ORIENTED_EDGE('',*,*,#2120,.T.);
#2122=EDGE_LOOP('',(#2113,#2114,#2115,#2121));
#2123=FACE_BOUND('',#2122,.T.);
#2124=ADVANCED_FACE('F658',(#2123),#2112,.F.);
#2125=CARTESIAN_POINT('',(-23.2979505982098,62.23,23.2979505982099));
#2126=DIRECTION('',(0.251490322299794,0.,0.967859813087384));
#2127=DIRECTION('',(0.967859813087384,0.,-0.251490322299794));
#2128=AXIS2_PLACEMENT_3D('',#2125,#2126,#2127);
#2129=PLANE('',#2128);
#2130=ORIENTED_EDGE('',*,*,#202,.T.);
#2131=ORIENTED_EDGE('',*,*,#1632,.T.);
#2132=ORIENTED_EDGE('',*,*,#2120,.F.);
#2133=ORIENTED_EDGE('',*,*,#2034,.F.);
#2134=EDGE_LOOP('',(#2130,#2131,#2132,#2133));
#2135=FACE_BOUND('',#2134,.T.);
#2136=ADVANCED_FACE('F662',(#2135),#2129,.F.);
#2137=CARTESIAN_POINT('',(-20.6332196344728,62.23,13.0427408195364));
#2138=DIRECTION('',(-0.967859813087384,0.,-0.251490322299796));
#2139=DIRECTION('',(-0.251490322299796,0.,0.967859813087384));
#2140=AXIS2_PLACEMENT_3D('',#2137,#2138,#2139);
#2141=PLANE('',#2140);
#2142=ORIENTED_EDGE('',*,*,#63,.T.);
#2143=ORIENTED_EDGE('',*,*,#2064,.F.);
#2144=ORIENTED_EDGE('',*,*,#2079,.T.);
#2145=ORIENTED_EDGE('',*,*,#1643,.T.);
#2146=EDGE_LOOP('',(#2142,#2143,#2144,#2145));
#2147=FACE_BOUND('',#2146,.T.);
#2148=ADVANCED_FACE('F667',(#2147),#2141,.F.);
#2149=CARTESIAN_POINT('',(-13.0427408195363,62.23,-20.6332196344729));
#2150=DIRECTION('',(0.,1.,0.));
#2151=DIRECTION('',(1.,0.,0.));
#2152=AXIS2_PLACEMENT_3D('',#2149,#2150,#2151);
#2153=PLANE('',#2152);
#2154=CARTESIAN_POINT('',(-16.8379802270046,62.23,-16.8379802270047));
#2155=DIRECTION('',(0.,1.,0.));
#2156=DIRECTION('',(0.,0.,1.));
#2157=AXIS2_PLACEMENT_3D('',#2154,#2155,#2156);
#2158=CIRCLE('',#2157,3.9624);
#2159=CARTESIAN_POINT('',(-16.8379802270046,62.23,-12.8755802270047));
#2160=VERTEX_POINT('',#2159);
#2161=EDGE_CURVE('E1018',#2160,#2160,#2158,.T.);
#2162=ORIENTED_EDGE('',*,*,#2161,.F.);
#2163=EDGE_LOOP('',(#2162));
#2164=FACE_BOUND('',#2163,.T.);
#2165=ORIENTED_EDGE('',*,*,#1111,.F.);
#2166=DIRECTION('',(0.25149032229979,0.,0.967859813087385));
#2167=VECTOR('',#2166,1.);
#2168=CARTESIAN_POINT('',(-23.2979505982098,62.23,-23.2979505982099));
#2169=LINE('',#2168,#2167);
#2170=CARTESIAN_POINT('',(-20.6332196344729,62.23,-13.0427408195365));
#2171=VERTEX_POINT('',#2170);
#2172=EDGE_CURVE('E592',#36,#2171,#2169,.T.);
#2173=ORIENTED_EDGE('',*,*,#2172,.T.);
#2174=DIRECTION('',(0.965925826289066,0.,0.258819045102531));
#2175=VECTOR('',#2174,1.);
#2176=CARTESIAN_POINT('',(-20.6332196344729,62.23,-13.0427408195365));
#2177=LINE('',#2176,#2175);
#2178=CARTESIAN_POINT('',(-15.4488261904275,62.23,-11.6535867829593));
#2179=VERTEX_POINT('',#2178);
#2180=EDGE_CURVE('E594',#2171,#2179,#2177,.T.);
#2181=ORIENTED_EDGE('',*,*,#2180,.T.);
#2182=DIRECTION('',(0.707106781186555,0.,-0.70710678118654));
#2183=VECTOR('',#2182,1.);
#2184=CARTESIAN_POINT('',(-15.4488261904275,62.23,-11.6535867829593));
#2185=LINE('',#2184,#2183);
#2186=CARTESIAN_POINT('',(-11.6535867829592,62.23,-15.4488261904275));
#2187=VERTEX_POINT('',#2186);
#2188=EDGE_CURVE('E597',#2179,#2187,#2185,.T.);
#2189=ORIENTED_EDGE('',*,*,#2188,.T.);
#2190=DIRECTION('',(-0.258819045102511,0.,-0.965925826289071));
#2191=VECTOR('',#2190,1.);
#2192=CARTESIAN_POINT('',(-11.6535867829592,62.23,-15.4488261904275));
#2193=LINE('',#2192,#2191);
#2194=CARTESIAN_POINT('',(-13.0427408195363,62.23,-20.6332196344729));
#2195=VERTEX_POINT('',#2194);
#2196=EDGE_CURVE('E585',#2187,#2195,#2193,.T.);
#2197=ORIENTED_EDGE('',*,*,#2196,.T.);
#2198=DIRECTION('',(-0.967859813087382,0.,-0.251490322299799));
#2199=VECTOR('',#2198,1.);
#2200=CARTESIAN_POINT('',(-13.0427408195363,62.23,-20.6332196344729));
#2201=LINE('',#2200,#2199);
#2202=EDGE_CURVE('E588',#2195,#521,#2201,.T.);
#2203=ORIENTED_EDGE('',*,*,#2202,.T.);
#2204=EDGE_LOOP('',(#2165,#2173,#2181,#2189,#2197,#2203));
#2205=FACE_BOUND('',#2204,.T.);
#2206=ADVANCED_FACE('F647',(#2164,#2205),#2153,.T.);
#2207=CARTESIAN_POINT('',(-11.6535867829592,62.23,-15.4488261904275));
#2208=DIRECTION('',(0.965925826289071,0.,-0.258819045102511));
#2209=DIRECTION('',(-0.258819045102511,0.,-0.965925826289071));
#2210=AXIS2_PLACEMENT_3D('',#2207,#2208,#2209);
#2211=PLANE('',#2210);
#2212=ORIENTED_EDGE('',*,*,#1716,.T.);
#2213=DIRECTION('',(0.,1.,0.));
#2214=VECTOR('',#2213,1.);
#2215=CARTESIAN_POINT('',(-13.0427408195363,62.23,-20.6332196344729));
#2216=LINE('',#2215,#2214);
#2217=EDGE_CURVE('E600',#2195,#1707,#2216,.T.);
#2218=ORIENTED_EDGE('',*,*,#2217,.F.);
#2219=ORIENTED_EDGE('',*,*,#2196,.F.);
#2220=DIRECTION('',(0.,1.,0.));
#2221=VECTOR('',#2220,1.);
#2222=CARTESIAN_POINT('',(-11.6535867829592,62.23,-15.4488261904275));
#2223=LINE('',#2222,#2221);
#2224=EDGE_CURVE('E609',#2187,#1715,#2223,.T.);
#2225=ORIENTED_EDGE('',*,*,#2224,.T.);
#2226=EDGE_LOOP('',(#2212,#2218,#2219,#2225));
#2227=FACE_BOUND('',#2226,.T.);
#2228=ADVANCED_FACE('F643',(#2227),#2211,.F.);
#2229=CARTESIAN_POINT('',(-15.4488261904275,62.23,-11.6535867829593));
#2230=DIRECTION('',(0.70710678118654,0.,0.707106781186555));
#2231=DIRECTION('',(0.707106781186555,0.,-0.70710678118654));
#2232=AXIS2_PLACEMENT_3D('',#2229,#2230,#2231);
#2233=PLANE('',#2232);
#2234=ORIENTED_EDGE('',*,*,#1724,.T.);
#2235=ORIENTED_EDGE('',*,*,#2224,.F.);
#2236=ORIENTED_EDGE('',*,*,#2188,.F.);
#2237=DIRECTION('',(0.,1.,0.));
#2238=VECTOR('',#2237,1.);
#2239=CARTESIAN_POINT('',(-15.4488261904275,62.23,-11.6535867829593));
#2240=LINE('',#2239,#2238);
#2241=EDGE_CURVE('E612',#2179,#1723,#2240,.T.);
#2242=ORIENTED_EDGE('',*,*,#2241,.T.);
#2243=EDGE_LOOP('',(#2234,#2235,#2236,#2242));
#2244=FACE_BOUND('',#2243,.T.);
#2245=ADVANCED_FACE('F646',(#2244),#2233,.F.);
#2246=CARTESIAN_POINT('',(-20.6332196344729,62.23,-13.0427408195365));
#2247=DIRECTION('',(-0.258819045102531,0.,0.965925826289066));
#2248=DIRECTION('',(0.965925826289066,0.,0.258819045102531));
#2249=AXIS2_PLACEMENT_3D('',#2246,#2247,#2248);
#2250=PLANE('',#2249);
#2251=ORIENTED_EDGE('',*,*,#1730,.T.);
#2252=ORIENTED_EDGE('',*,*,#2241,.F.);
#2253=ORIENTED_EDGE('',*,*,#2180,.F.);
#2254=DIRECTION('',(0.,1.,0.));
#2255=VECTOR('',#2254,1.);
#2256=CARTESIAN_POINT('',(-20.6332196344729,62.23,-13.0427408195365));
#2257=LINE('',#2256,#2255);
#2258=EDGE_CURVE('E614',#2171,#1696,#2257,.T.);
#2259=ORIENTED_EDGE('',*,*,#2258,.T.);
#2260=EDGE_LOOP('',(#2251,#2252,#2253,#2259));
#2261=FACE_BOUND('',#2260,.T.);
#2262=ADVANCED_FACE('F1203',(#2261),#2250,.F.);
#2263=CARTESIAN_POINT('',(-23.2979505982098,62.23,-23.2979505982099));
#2264=DIRECTION('',(-0.967859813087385,0.,0.25149032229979));
#2265=DIRECTION('',(0.25149032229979,0.,0.967859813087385));
#2266=AXIS2_PLACEMENT_3D('',#2263,#2264,#2265);
#2267=PLANE('',#2266);
#2268=ORIENTED_EDGE('',*,*,#39,.T.);
#2269=ORIENTED_EDGE('',*,*,#1697,.T.);
#2270=ORIENTED_EDGE('',*,*,#2258,.F.);
#2271=ORIENTED_EDGE('',*,*,#2172,.F.);
#2272=EDGE_LOOP('',(#2268,#2269,#2270,#2271));
#2273=FACE_BOUND('',#2272,.T.);
#2274=ADVANCED_FACE('F639',(#2273),#2267,.F.);
#2275=CARTESIAN_POINT('',(-13.0427408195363,62.23,-20.6332196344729));
#2276=DIRECTION('',(0.251490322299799,0.,-0.967859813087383));
#2277=DIRECTION('',(-0.967859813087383,0.,-0.251490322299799));
#2278=AXIS2_PLACEMENT_3D('',#2275,#2276,#2277);
#2279=PLANE('',#2278);
#2280=ORIENTED_EDGE('',*,*,#537,.T.);
#2281=ORIENTED_EDGE('',*,*,#2202,.F.);
#2282=ORIENTED_EDGE('',*,*,#2217,.T.);
#2283=ORIENTED_EDGE('',*,*,#1708,.T.);
#2284=EDGE_LOOP('',(#2280,#2281,#2282,#2283));
#2285=FACE_BOUND('',#2284,.T.);
#2286=ADVANCED_FACE('F634',(#2285),#2279,.F.);
#2287=CARTESIAN_POINT('',(16.8379802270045,51.0226403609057,-16.8379802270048));
#2288=DIRECTION('',(0.,1.,0.));
#2289=DIRECTION('',(0.,0.,1.));
#2290=AXIS2_PLACEMENT_3D('',#2287,#2288,#2289);
#2291=CYLINDRICAL_SURFACE('',#2290,3.9624);
#2292=CARTESIAN_POINT('',(16.8379802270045,68.199,-16.8379802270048));
#2293=DIRECTION('',(0.,1.,0.));
#2294=DIRECTION('',(0.,0.,1.));
#2295=AXIS2_PLACEMENT_3D('',#2292,#2293,#2294);
#2296=CIRCLE('',#2295,3.9624);
#2297=CARTESIAN_POINT('',(16.8379802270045,68.199,-12.8755802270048));
#2298=VERTEX_POINT('',#2297);
#2299=EDGE_CURVE('E1024',#2298,#2298,#2296,.F.);
#2300=ORIENTED_EDGE('',*,*,#2299,.T.);
#2301=EDGE_LOOP('',(#2300));
#2302=FACE_BOUND('',#2301,.T.);
#2303=ORIENTED_EDGE('',*,*,#1747,.T.);
#2304=EDGE_LOOP('',(#2303));
#2305=FACE_BOUND('',#2304,.T.);
#2306=ADVANCED_FACE('F638',(#2302,#2305),#2291,.T.);
#2307=CARTESIAN_POINT('',(16.8379802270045,68.58,-16.8379802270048));
#2308=DIRECTION('',(0.,1.,0.));
#2309=DIRECTION('',(0.,0.,1.));
#2310=AXIS2_PLACEMENT_3D('',#2307,#2308,#2309);
#2311=PLANE('',#2310);
#2312=CARTESIAN_POINT('',(16.8379802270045,68.58,-16.8379802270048));
#2313=DIRECTION('',(0.,1.,0.));
#2314=DIRECTION('',(0.,0.,1.));
#2315=AXIS2_PLACEMENT_3D('',#2312,#2313,#2314);
#2316=CIRCLE('',#2315,3.58139999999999);
#2317=CARTESIAN_POINT('',(16.8379802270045,68.58,-13.2565802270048));
#2318=VERTEX_POINT('',#2317);
#2319=EDGE_CURVE('E1021',#2318,#2318,#2316,.T.);
#2320=ORIENTED_EDGE('',*,*,#2319,.T.);
#2321=EDGE_LOOP('',(#2320));
#2322=FACE_BOUND('',#2321,.T.);
#2323=DIRECTION('',(0.499999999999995,0.,-0.866025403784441));
#2324=VECTOR('',#2323,1.);
#2325=CARTESIAN_POINT('',(17.9567610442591,68.58,-14.9001950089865));
#2326=LINE('',#2325,#2324);
#2327=CARTESIAN_POINT('',(17.9567610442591,68.58,-14.9001950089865));
#2328=VERTEX_POINT('',#2327);
#2329=CARTESIAN_POINT('',(19.0755418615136,68.58,-16.8379802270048));
#2330=VERTEX_POINT('',#2329);
#2331=EDGE_CURVE('E526',#2328,#2330,#2326,.T.);
#2332=ORIENTED_EDGE('',*,*,#2331,.F.);
#2333=DIRECTION('',(1.,0.,0.));
#2334=VECTOR('',#2333,1.);
#2335=CARTESIAN_POINT('',(15.71919940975,68.58,-14.9001950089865));
#2336=LINE('',#2335,#2334);
#2337=CARTESIAN_POINT('',(15.71919940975,68.58,-14.9001950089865));
#2338=VERTEX_POINT('',#2337);
#2339=EDGE_CURVE('E541',#2338,#2328,#2336,.T.);
#2340=ORIENTED_EDGE('',*,*,#2339,.F.);
#2341=DIRECTION('',(0.500000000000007,0.,0.866025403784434));
#2342=VECTOR('',#2341,1.);
#2343=CARTESIAN_POINT('',(14.6004185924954,68.58,-16.8379802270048));
#2344=LINE('',#2343,#2342);
#2345=CARTESIAN_POINT('',(14.6004185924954,68.58,-16.8379802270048));
#2346=VERTEX_POINT('',#2345);
#2347=EDGE_CURVE('E567',#2346,#2338,#2344,.T.);
#2348=ORIENTED_EDGE('',*,*,#2347,.F.);
#2349=DIRECTION('',(-0.499999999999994,0.,0.866025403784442));
#2350=VECTOR('',#2349,1.);
#2351=CARTESIAN_POINT('',(15.71919940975,68.58,-18.7757654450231));
#2352=LINE('',#2351,#2350);
#2353=CARTESIAN_POINT('',(15.71919940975,68.58,-18.7757654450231));
#2354=VERTEX_POINT('',#2353);
#2355=EDGE_CURVE('E564',#2354,#2346,#2352,.T.);
#2356=ORIENTED_EDGE('',*,*,#2355,.F.);
#2357=DIRECTION('',(-1.,0.,0.));
#2358=VECTOR('',#2357,1.);
#2359=CARTESIAN_POINT('',(17.956761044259,68.58,-18.7757654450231));
#2360=LINE('',#2359,#2358);
#2361=CARTESIAN_POINT('',(17.956761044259,68.58,-18.7757654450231));
#2362=VERTEX_POINT('',#2361);
#2363=EDGE_CURVE('E561',#2362,#2354,#2360,.T.);
#2364=ORIENTED_EDGE('',*,*,#2363,.F.);
#2365=DIRECTION('',(-0.500000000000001,0.,-0.866025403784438));
#2366=VECTOR('',#2365,1.);
#2367=CARTESIAN_POINT('',(19.0755418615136,68.58,-16.8379802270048));
#2368=LINE('',#2367,#2366);
#2369=EDGE_CURVE('E558',#2330,#2362,#2368,.T.);
#2370=ORIENTED_EDGE('',*,*,#2369,.F.);
#2371=EDGE_LOOP('',(#2332,#2340,#2348,#2356,#2364,#2370));
#2372=FACE_BOUND('',#2371,.T.);
#2373=ADVANCED_FACE('F1191',(#2322,#2372),#2311,.T.);
#2374=CARTESIAN_POINT('',(17.9567610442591,65.405,-14.9001950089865));
#2375=DIRECTION('',(0.866025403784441,0.,0.499999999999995));
#2376=DIRECTION('',(0.499999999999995,0.,-0.866025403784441));
#2377=AXIS2_PLACEMENT_3D('',#2374,#2375,#2376);
#2378=PLANE('',#2377);
#2379=ORIENTED_EDGE('',*,*,#2331,.T.);
#2380=DIRECTION('',(0.,1.,0.));
#2381=VECTOR('',#2380,1.);
#2382=CARTESIAN_POINT('',(19.0755418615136,65.405,-16.8379802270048));
#2383=LINE('',#2382,#2381);
#2384=CARTESIAN_POINT('',(19.0755418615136,65.405,-16.8379802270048));
#2385=VERTEX_POINT('',#2384);
#2386=EDGE_CURVE('E556',#2385,#2330,#2383,.T.);
#2387=ORIENTED_EDGE('',*,*,#2386,.F.);
#2388=DIRECTION('',(0.499999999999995,0.,-0.866025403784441));
#2389=VECTOR('',#2388,1.);
#2390=CARTESIAN_POINT('',(17.9567610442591,65.405,-14.9001950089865));
#2391=LINE('',#2390,#2389);
#2392=CARTESIAN_POINT('',(17.9567610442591,65.405,-14.9001950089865));
#2393=VERTEX_POINT('',#2392);
#2394=EDGE_CURVE('E537',#2393,#2385,#2391,.T.);
#2395=ORIENTED_EDGE('',*,*,#2394,.F.);
#2396=DIRECTION('',(0.,1.,0.));
#2397=VECTOR('',#2396,1.);
#2398=CARTESIAN_POINT('',(17.9567610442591,65.405,-14.9001950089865));
#2399=LINE('',#2398,#2397);
#2400=EDGE_CURVE('E572',#2393,#2328,#2399,.T.);
#2401=ORIENTED_EDGE('',*,*,#2400,.T.);
#2402=EDGE_LOOP('',(#2379,#2387,#2395,#2401));
#2403=FACE_BOUND('',#2402,.T.);
#2404=ADVANCED_FACE('F1173',(#2403),#2378,.F.);
#2405=CARTESIAN_POINT('',(15.71919940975,65.405,-14.9001950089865));
#2406=DIRECTION('',(0.,0.,1.));
#2407=DIRECTION('',(1.,0.,0.));
#2408=AXIS2_PLACEMENT_3D('',#2405,#2406,#2407);
#2409=PLANE('',#2408);
#2410=ORIENTED_EDGE('',*,*,#2339,.T.);
#2411=ORIENTED_EDGE('',*,*,#2400,.F.);
#2412=DIRECTION('',(1.,0.,0.));
#2413=VECTOR('',#2412,1.);
#2414=CARTESIAN_POINT('',(15.71919940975,65.405,-14.9001950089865));
#2415=LINE('',#2414,#2413);
#2416=CARTESIAN_POINT('',(15.71919940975,65.405,-14.9001950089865));
#2417=VERTEX_POINT('',#2416);
#2418=EDGE_CURVE('E553',#2417,#2393,#2415,.T.);
#2419=ORIENTED_EDGE('',*,*,#2418,.F.);
#2420=DIRECTION('',(0.,1.,0.));
#2421=VECTOR('',#2420,1.);
#2422=CARTESIAN_POINT('',(15.71919940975,65.405,-14.9001950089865));
#2423=LINE('',#2422,#2421);
#2424=EDGE_CURVE('E575',#2417,#2338,#2423,.T.);
#2425=ORIENTED_EDGE('',*,*,#2424,.T.);
#2426=EDGE_LOOP('',(#2410,#2411,#2419,#2425));
#2427=FACE_BOUND('',#2426,.T.);
#2428=ADVANCED_FACE('F1169',(#2427),#2409,.F.);
#2429=CARTESIAN_POINT('',(14.6004185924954,65.405,-16.8379802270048));
#2430=DIRECTION('',(-0.866025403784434,0.,0.500000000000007));
#2431=DIRECTION('',(0.500000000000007,0.,0.866025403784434));
#2432=AXIS2_PLACEMENT_3D('',#2429,#2430,#2431);
#2433=PLANE('',#2432);
#2434=ORIENTED_EDGE('',*,*,#2347,.T.);
#2435=ORIENTED_EDGE('',*,*,#2424,.F.);
#2436=DIRECTION('',(0.500000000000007,0.,0.866025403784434));
#2437=VECTOR('',#2436,1.);
#2438=CARTESIAN_POINT('',(14.6004185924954,65.405,-16.8379802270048));
#2439=LINE('',#2438,#2437);
#2440=CARTESIAN_POINT('',(14.6004185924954,65.405,-16.8379802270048));
#2441=VERTEX_POINT('',#2440);
#2442=EDGE_CURVE('E550',#2441,#2417,#2439,.T.);
#2443=ORIENTED_EDGE('',*,*,#2442,.F.);
#2444=DIRECTION('',(0.,1.,0.));
#2445=VECTOR('',#2444,1.);
#2446=CARTESIAN_POINT('',(14.6004185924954,65.405,-16.8379802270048));
#2447=LINE('',#2446,#2445);
#2448=EDGE_CURVE('E577',#2441,#2346,#2447,.T.);
#2449=ORIENTED_EDGE('',*,*,#2448,.T.);
#2450=EDGE_LOOP('',(#2434,#2435,#2443,#2449));
#2451=FACE_BOUND('',#2450,.T.);
#2452=ADVANCED_FACE('F1172',(#2451),#2433,.F.);
#2453=CARTESIAN_POINT('',(15.71919940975,65.405,-18.7757654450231));
#2454=DIRECTION('',(-0.866025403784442,0.,-0.499999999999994));
#2455=DIRECTION('',(-0.499999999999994,0.,0.866025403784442));
#2456=AXIS2_PLACEMENT_3D('',#2453,#2454,#2455);
#2457=PLANE('',#2456);
#2458=ORIENTED_EDGE('',*,*,#2355,.T.);
#2459=ORIENTED_EDGE('',*,*,#2448,.F.);
#2460=DIRECTION('',(-0.499999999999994,0.,0.866025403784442));
#2461=VECTOR('',#2460,1.);
#2462=CARTESIAN_POINT('',(15.71919940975,65.405,-18.7757654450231));
#2463=LINE('',#2462,#2461);
#2464=CARTESIAN_POINT('',(15.71919940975,65.405,-18.7757654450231));
#2465=VERTEX_POINT('',#2464);
#2466=EDGE_CURVE('E547',#2465,#2441,#2463,.T.);
#2467=ORIENTED_EDGE('',*,*,#2466,.F.);
#2468=DIRECTION('',(0.,1.,0.));
#2469=VECTOR('',#2468,1.);
#2470=CARTESIAN_POINT('',(15.71919940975,65.405,-18.7757654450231));
#2471=LINE('',#2470,#2469);
#2472=EDGE_CURVE('E579',#2465,#2354,#2471,.T.);
#2473=ORIENTED_EDGE('',*,*,#2472,.T.);
#2474=EDGE_LOOP('',(#2458,#2459,#2467,#2473));
#2475=FACE_BOUND('',#2474,.T.);
#2476=ADVANCED_FACE('F1177',(#2475),#2457,.F.);
#2477=CARTESIAN_POINT('',(17.956761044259,65.405,-18.7757654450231));
#2478=DIRECTION('',(0.,0.,-1.));
#2479=DIRECTION('',(-1.,0.,0.));
#2480=AXIS2_PLACEMENT_3D('',#2477,#2478,#2479);
#2481=PLANE('',#2480);
#2482=ORIENTED_EDGE('',*,*,#2363,.T.);
#2483=ORIENTED_EDGE('',*,*,#2472,.F.);
#2484=DIRECTION('',(-1.,0.,0.));
#2485=VECTOR('',#2484,1.);
#2486=CARTESIAN_POINT('',(17.956761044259,65.405,-18.7757654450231));
#2487=LINE('',#2486,#2485);
#2488=CARTESIAN_POINT('',(17.956761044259,65.405,-18.7757654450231));
#2489=VERTEX_POINT('',#2488);
#2490=EDGE_CURVE('E544',#2489,#2465,#2487,.T.);
#2491=ORIENTED_EDGE('',*,*,#2490,.F.);
#2492=DIRECTION('',(0.,1.,0.));
#2493=VECTOR('',#2492,1.);
#2494=CARTESIAN_POINT('',(17.956761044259,65.405,-18.7757654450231));
#2495=LINE('',#2494,#2493);
#2496=EDGE_CURVE('E581',#2489,#2362,#2495,.T.);
#2497=ORIENTED_EDGE('',*,*,#2496,.T.);
#2498=EDGE_LOOP('',(#2482,#2483,#2491,#2497));
#2499=FACE_BOUND('',#2498,.T.);
#2500=ADVANCED_FACE('F1181',(#2499),#2481,.F.);
#2501=CARTESIAN_POINT('',(19.0755418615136,65.405,-16.8379802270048));
#2502=DIRECTION('',(0.866025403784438,0.,-0.500000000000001));
#2503=DIRECTION('',(-0.500000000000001,0.,-0.866025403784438));
#2504=AXIS2_PLACEMENT_3D('',#2501,#2502,#2503);
#2505=PLANE('',#2504);
#2506=ORIENTED_EDGE('',*,*,#2369,.T.);
#2507=ORIENTED_EDGE('',*,*,#2496,.F.);
#2508=DIRECTION('',(-0.500000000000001,0.,-0.866025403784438));
#2509=VECTOR('',#2508,1.);
#2510=CARTESIAN_POINT('',(19.0755418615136,65.405,-16.8379802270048));
#2511=LINE('',#2510,#2509);
#2512=EDGE_CURVE('E540',#2385,#2489,#2511,.T.);
#2513=ORIENTED_EDGE('',*,*,#2512,.F.);
#2514=ORIENTED_EDGE('',*,*,#2386,.T.);
#2515=EDGE_LOOP('',(#2506,#2507,#2513,#2514));
#2516=FACE_BOUND('',#2515,.T.);
#2517=ADVANCED_FACE('F1167',(#2516),#2505,.F.);
#2518=CARTESIAN_POINT('',(19.0755418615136,65.405,-16.8379802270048));
#2519=DIRECTION('',(0.,1.,0.));
#2520=DIRECTION('',(0.,0.,1.));
#2521=AXIS2_PLACEMENT_3D('',#2518,#2519,#2520);
#2522=PLANE('',#2521);
#2523=ORIENTED_EDGE('',*,*,#2394,.T.);
#2524=ORIENTED_EDGE('',*,*,#2512,.T.);
#2525=ORIENTED_EDGE('',*,*,#2490,.T.);
#2526=ORIENTED_EDGE('',*,*,#2466,.T.);
#2527=ORIENTED_EDGE('',*,*,#2442,.T.);
#2528=ORIENTED_EDGE('',*,*,#2418,.T.);
#2529=EDGE_LOOP('',(#2523,#2524,#2525,#2526,#2527,#2528));
#2530=FACE_BOUND('',#2529,.T.);
#2531=ADVANCED_FACE('F1163',(#2530),#2522,.T.);
#2532=CARTESIAN_POINT('',(16.8379802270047,51.0226403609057,16.8379802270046));
#2533=DIRECTION('',(0.,1.,0.));
#2534=DIRECTION('',(0.,0.,1.));
#2535=AXIS2_PLACEMENT_3D('',#2532,#2533,#2534);
#2536=CYLINDRICAL_SURFACE('',#2535,3.9624);
#2537=CARTESIAN_POINT('',(16.8379802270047,68.199,16.8379802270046));
#2538=DIRECTION('',(0.,1.,0.));
#2539=DIRECTION('',(0.,0.,1.));
#2540=AXIS2_PLACEMENT_3D('',#2537,#2538,#2539);
#2541=CIRCLE('',#2540,3.9624);
#2542=CARTESIAN_POINT('',(16.8379802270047,68.199,20.8003802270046));
#2543=VERTEX_POINT('',#2542);
#2544=EDGE_CURVE('E1030',#2543,#2543,#2541,.F.);
#2545=ORIENTED_EDGE('',*,*,#2544,.T.);
#2546=EDGE_LOOP('',(#2545));
#2547=FACE_BOUND('',#2546,.T.);
#2548=ORIENTED_EDGE('',*,*,#1885,.T.);
#2549=EDGE_LOOP('',(#2548));
#2550=FACE_BOUND('',#2549,.T.);
#2551=ADVANCED_FACE('F1159',(#2547,#2550),#2536,.T.);
#2552=CARTESIAN_POINT('',(16.8379802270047,68.58,16.8379802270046));
#2553=DIRECTION('',(0.,1.,0.));
#2554=DIRECTION('',(-1.,0.,0.));
#2555=AXIS2_PLACEMENT_3D('',#2552,#2553,#2554);
#2556=PLANE('',#2555);
#2557=CARTESIAN_POINT('',(16.8379802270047,68.58,16.8379802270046));
#2558=DIRECTION('',(0.,1.,0.));
#2559=DIRECTION('',(0.,0.,1.));
#2560=AXIS2_PLACEMENT_3D('',#2557,#2558,#2559);
#2561=CIRCLE('',#2560,3.58139999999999);
#2562=CARTESIAN_POINT('',(16.8379802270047,68.58,20.4193802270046));
#2563=VERTEX_POINT('',#2562);
#2564=EDGE_CURVE('E1027',#2563,#2563,#2561,.T.);
#2565=ORIENTED_EDGE('',*,*,#2564,.T.);
#2566=EDGE_LOOP('',(#2565));
#2567=FACE_BOUND('',#2566,.T.);
#2568=DIRECTION('',(0.866025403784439,0.,0.499999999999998));
#2569=VECTOR('',#2568,1.);
#2570=CARTESIAN_POINT('',(14.9001950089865,68.58,17.9567610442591));
#2571=LINE('',#2570,#2569);
#2572=CARTESIAN_POINT('',(14.9001950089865,68.58,17.9567610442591));
#2573=VERTEX_POINT('',#2572);
#2574=CARTESIAN_POINT('',(16.8379802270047,68.58,19.0755418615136));
#2575=VERTEX_POINT('',#2574);
#2576=EDGE_CURVE('E479',#2573,#2575,#2571,.T.);
#2577=ORIENTED_EDGE('',*,*,#2576,.F.);
#2578=DIRECTION('',(0.,0.,1.));
#2579=VECTOR('',#2578,1.);
#2580=CARTESIAN_POINT('',(14.9001950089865,68.58,15.71919940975));
#2581=LINE('',#2580,#2579);
#2582=CARTESIAN_POINT('',(14.9001950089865,68.58,15.71919940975));
#2583=VERTEX_POINT('',#2582);
#2584=EDGE_CURVE('E493',#2583,#2573,#2581,.T.);
#2585=ORIENTED_EDGE('',*,*,#2584,.F.);
#2586=DIRECTION('',(-0.866025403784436,0.,0.500000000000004));
#2587=VECTOR('',#2586,1.);
#2588=CARTESIAN_POINT('',(16.8379802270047,68.58,14.6004185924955));
#2589=LINE('',#2588,#2587);
#2590=CARTESIAN_POINT('',(16.8379802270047,68.58,14.6004185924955));
#2591=VERTEX_POINT('',#2590);
#2592=EDGE_CURVE('E519',#2591,#2583,#2589,.T.);
#2593=ORIENTED_EDGE('',*,*,#2592,.F.);
#2594=DIRECTION('',(-0.86602540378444,0.,-0.499999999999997));
#2595=VECTOR('',#2594,1.);
#2596=CARTESIAN_POINT('',(18.775765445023,68.58,15.71919940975));
#2597=LINE('',#2596,#2595);
#2598=CARTESIAN_POINT('',(18.775765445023,68.58,15.71919940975));
#2599=VERTEX_POINT('',#2598);
#2600=EDGE_CURVE('E516',#2599,#2591,#2597,.T.);
#2601=ORIENTED_EDGE('',*,*,#2600,.F.);
#2602=DIRECTION('',(0.,0.,-1.));
#2603=VECTOR('',#2602,1.);
#2604=CARTESIAN_POINT('',(18.775765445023,68.58,17.9567610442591));
#2605=LINE('',#2604,#2603);
#2606=CARTESIAN_POINT('',(18.775765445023,68.58,17.9567610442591));
#2607=VERTEX_POINT('',#2606);
#2608=EDGE_CURVE('E513',#2607,#2599,#2605,.T.);
#2609=ORIENTED_EDGE('',*,*,#2608,.F.);
#2610=DIRECTION('',(0.86602540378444,0.,-0.499999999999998));
#2611=VECTOR('',#2610,1.);
#2612=CARTESIAN_POINT('',(16.8379802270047,68.58,19.0755418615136));
#2613=LINE('',#2612,#2611);
#2614=EDGE_CURVE('E510',#2575,#2607,#2613,.T.);
#2615=ORIENTED_EDGE('',*,*,#2614,.F.);
#2616=EDGE_LOOP('',(#2577,#2585,#2593,#2601,#2609,#2615));
#2617=FACE_BOUND('',#2616,.T.);
#2618=ADVANCED_FACE('F1155',(#2567,#2617),#2556,.T.);
#2619=CARTESIAN_POINT('',(-16.8379802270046,51.0226403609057,16.8379802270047));
#2620=DIRECTION('',(0.,1.,0.));
#2621=DIRECTION('',(0.,0.,1.));
#2622=AXIS2_PLACEMENT_3D('',#2619,#2620,#2621);
#2623=CYLINDRICAL_SURFACE('',#2622,3.9624);
#2624=CARTESIAN_POINT('',(-16.8379802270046,68.199,16.8379802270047));
#2625=DIRECTION('',(0.,1.,0.));
#2626=DIRECTION('',(0.,0.,1.));
#2627=AXIS2_PLACEMENT_3D('',#2624,#2625,#2626);
#2628=CIRCLE('',#2627,3.9624);
#2629=CARTESIAN_POINT('',(-16.8379802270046,68.199,20.8003802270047));
#2630=VERTEX_POINT('',#2629);
#2631=EDGE_CURVE('E1036',#2630,#2630,#2628,.F.);
#2632=ORIENTED_EDGE('',*,*,#2631,.T.);
#2633=EDGE_LOOP('',(#2632));
#2634=FACE_BOUND('',#2633,.T.);
#2635=ORIENTED_EDGE('',*,*,#2023,.T.);
#2636=EDGE_LOOP('',(#2635));
#2637=FACE_BOUND('',#2636,.T.);
#2638=ADVANCED_FACE('F1151',(#2634,#2637),#2623,.T.);
#2639=CARTESIAN_POINT('',(-16.8379802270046,68.58,16.8379802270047));
#2640=DIRECTION('',(0.,1.,0.));
#2641=DIRECTION('',(0.,0.,-1.));
#2642=AXIS2_PLACEMENT_3D('',#2639,#2640,#2641);
#2643=PLANE('',#2642);
#2644=CARTESIAN_POINT('',(-16.8379802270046,68.58,16.8379802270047));
#2645=DIRECTION('',(0.,1.,0.));
#2646=DIRECTION('',(0.,0.,1.));
#2647=AXIS2_PLACEMENT_3D('',#2644,#2645,#2646);
#2648=CIRCLE('',#2647,3.58139999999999);
#2649=CARTESIAN_POINT('',(-16.8379802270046,68.58,20.4193802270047));
#2650=VERTEX_POINT('',#2649);
#2651=EDGE_CURVE('E1033',#2650,#2650,#2648,.T.);
#2652=ORIENTED_EDGE('',*,*,#2651,.T.);
#2653=EDGE_LOOP('',(#2652));
#2654=FACE_BOUND('',#2653,.T.);
#2655=DIRECTION('',(-0.500000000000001,0.,0.866025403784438));
#2656=VECTOR('',#2655,1.);
#2657=CARTESIAN_POINT('',(-17.9567610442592,68.58,14.9001950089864));
#2658=LINE('',#2657,#2656);
#2659=CARTESIAN_POINT('',(-17.9567610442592,68.58,14.9001950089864));
#2660=VERTEX_POINT('',#2659);
#2661=CARTESIAN_POINT('',(-19.0755418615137,68.58,16.8379802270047));
#2662=VERTEX_POINT('',#2661);
#2663=EDGE_CURVE('E55',#2660,#2662,#2658,.T.);
#2664=ORIENTED_EDGE('',*,*,#2663,.F.);
#2665=DIRECTION('',(-1.,0.,0.));
#2666=VECTOR('',#2665,1.);
#2667=CARTESIAN_POINT('',(-15.7191994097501,68.58,14.9001950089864));
#2668=LINE('',#2667,#2666);
#2669=CARTESIAN_POINT('',(-15.7191994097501,68.58,14.9001950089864));
#2670=VERTEX_POINT('',#2669);
#2671=EDGE_CURVE('E446',#2670,#2660,#2668,.T.);
#2672=ORIENTED_EDGE('',*,*,#2671,.F.);
#2673=DIRECTION('',(-0.500000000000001,0.,-0.866025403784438));
#2674=VECTOR('',#2673,1.);
#2675=CARTESIAN_POINT('',(-14.6004185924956,68.58,16.8379802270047));
#2676=LINE('',#2675,#2674);
#2677=CARTESIAN_POINT('',(-14.6004185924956,68.58,16.8379802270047));
#2678=VERTEX_POINT('',#2677);
#2679=EDGE_CURVE('E472',#2678,#2670,#2676,.T.);
#2680=ORIENTED_EDGE('',*,*,#2679,.F.);
#2681=DIRECTION('',(0.5,0.,-0.866025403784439));
#2682=VECTOR('',#2681,1.);
#2683=CARTESIAN_POINT('',(-15.7191994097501,68.58,18.775765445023));
#2684=LINE('',#2683,#2682);
#2685=CARTESIAN_POINT('',(-15.7191994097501,68.58,18.775765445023));
#2686=VERTEX_POINT('',#2685);
#2687=EDGE_CURVE('E469',#2686,#2678,#2684,.T.);
#2688=ORIENTED_EDGE('',*,*,#2687,.F.);
#2689=DIRECTION('',(1.,0.,0.));
#2690=VECTOR('',#2689,1.);
#2691=CARTESIAN_POINT('',(-17.9567610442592,68.58,18.775765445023));
#2692=LINE('',#2691,#2690);
#2693=CARTESIAN_POINT('',(-17.9567610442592,68.58,18.775765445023));
#2694=VERTEX_POINT('',#2693);
#2695=EDGE_CURVE('E466',#2694,#2686,#2692,.T.);
#2696=ORIENTED_EDGE('',*,*,#2695,.F.);
#2697=DIRECTION('',(0.499999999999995,0.,0.866025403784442));
#2698=VECTOR('',#2697,1.);
#2699=CARTESIAN_POINT('',(-19.0755418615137,68.58,16.8379802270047));
#2700=LINE('',#2699,#2698);
#2701=EDGE_CURVE('E463',#2662,#2694,#2700,.T.);
#2702=ORIENTED_EDGE('',*,*,#2701,.F.);
#2703=EDGE_LOOP('',(#2664,#2672,#2680,#2688,#2696,#2702));
#2704=FACE_BOUND('',#2703,.T.);
#2705=ADVANCED_FACE('F1147',(#2654,#2704),#2643,.T.);
#2706=CARTESIAN_POINT('',(-16.8379802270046,51.0226403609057,-16.8379802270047));
#2707=DIRECTION('',(0.,1.,0.));
#2708=DIRECTION('',(0.,0.,1.));
#2709=AXIS2_PLACEMENT_3D('',#2706,#2707,#2708);
#2710=CYLINDRICAL_SURFACE('',#2709,3.9624);
#2711=CARTESIAN_POINT('',(-16.8379802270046,68.199,-16.8379802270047));
#2712=DIRECTION('',(0.,1.,0.));
#2713=DIRECTION('',(0.,0.,1.));
#2714=AXIS2_PLACEMENT_3D('',#2711,#2712,#2713);
#2715=CIRCLE('',#2714,3.9624);
#2716=CARTESIAN_POINT('',(-16.8379802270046,68.199,-12.8755802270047));
#2717=VERTEX_POINT('',#2716);
#2718=EDGE_CURVE('E1042',#2717,#2717,#2715,.F.);
#2719=ORIENTED_EDGE('',*,*,#2718,.T.);
#2720=EDGE_LOOP('',(#2719));
#2721=FACE_BOUND('',#2720,.T.);
#2722=ORIENTED_EDGE('',*,*,#2161,.T.);
#2723=EDGE_LOOP('',(#2722));
#2724=FACE_BOUND('',#2723,.T.);
#2725=ADVANCED_FACE('F1143',(#2721,#2724),#2710,.T.);
#2726=CARTESIAN_POINT('',(-16.8379802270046,68.58,-16.8379802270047));
#2727=DIRECTION('',(0.,1.,0.));
#2728=DIRECTION('',(1.,0.,0.));
#2729=AXIS2_PLACEMENT_3D('',#2726,#2727,#2728);
#2730=PLANE('',#2729);
#2731=CARTESIAN_POINT('',(-16.8379802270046,68.58,-16.8379802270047));
#2732=DIRECTION('',(0.,1.,0.));
#2733=DIRECTION('',(0.,0.,1.));
#2734=AXIS2_PLACEMENT_3D('',#2731,#2732,#2733);
#2735=CIRCLE('',#2734,3.58139999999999);
#2736=CARTESIAN_POINT('',(-16.8379802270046,68.58,-13.2565802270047));
#2737=VERTEX_POINT('',#2736);
#2738=EDGE_CURVE('E1039',#2737,#2737,#2735,.T.);
#2739=ORIENTED_EDGE('',*,*,#2738,.T.);
#2740=EDGE_LOOP('',(#2739));
#2741=FACE_BOUND('',#2740,.T.);
#2742=DIRECTION('',(-0.866025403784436,0.,-0.500000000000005));
#2743=VECTOR('',#2742,1.);
#2744=CARTESIAN_POINT('',(-14.9001950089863,68.58,-17.9567610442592));
#2745=LINE('',#2744,#2743);
#2746=CARTESIAN_POINT('',(-14.9001950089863,68.58,-17.9567610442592));
#2747=VERTEX_POINT('',#2746);
#2748=CARTESIAN_POINT('',(-16.8379802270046,68.58,-19.0755418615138));
#2749=VERTEX_POINT('',#2748);
#2750=EDGE_CURVE('E47',#2747,#2749,#2745,.T.);
#2751=ORIENTED_EDGE('',*,*,#2750,.F.);
#2752=DIRECTION('',(0.,0.,-1.));
#2753=VECTOR('',#2752,1.);
#2754=CARTESIAN_POINT('',(-14.9001950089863,68.58,-15.7191994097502));
#2755=LINE('',#2754,#2753);
#2756=CARTESIAN_POINT('',(-14.9001950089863,68.58,-15.7191994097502));
#2757=VERTEX_POINT('',#2756);
#2758=EDGE_CURVE('E406',#2757,#2747,#2755,.T.);
#2759=ORIENTED_EDGE('',*,*,#2758,.F.);
#2760=DIRECTION('',(0.86602540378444,0.,-0.499999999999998));
#2761=VECTOR('',#2760,1.);
#2762=CARTESIAN_POINT('',(-16.8379802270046,68.58,-14.6004185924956));
#2763=LINE('',#2762,#2761);
#2764=CARTESIAN_POINT('',(-16.8379802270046,68.58,-14.6004185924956));
#2765=VERTEX_POINT('',#2764);
#2766=EDGE_CURVE('E409',#2765,#2757,#2763,.T.);
#2767=ORIENTED_EDGE('',*,*,#2766,.F.);
#2768=DIRECTION('',(0.866025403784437,0.,0.500000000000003));
#2769=VECTOR('',#2768,1.);
#2770=CARTESIAN_POINT('',(-18.7757654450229,68.58,-15.7191994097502));
#2771=LINE('',#2770,#2769);
#2772=CARTESIAN_POINT('',(-18.7757654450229,68.58,-15.7191994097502));
#2773=VERTEX_POINT('',#2772);
#2774=EDGE_CURVE('E428',#2773,#2765,#2771,.T.);
#2775=ORIENTED_EDGE('',*,*,#2774,.F.);
#2776=DIRECTION('',(0.,0.,1.));
#2777=VECTOR('',#2776,1.);
#2778=CARTESIAN_POINT('',(-18.7757654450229,68.58,-17.9567610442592));
#2779=LINE('',#2778,#2777);
#2780=CARTESIAN_POINT('',(-18.7757654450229,68.58,-17.9567610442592));
#2781=VERTEX_POINT('',#2780);
#2782=EDGE_CURVE('E425',#2781,#2773,#2779,.T.);
#2783=ORIENTED_EDGE('',*,*,#2782,.F.);
#2784=DIRECTION('',(-0.866025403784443,0.,0.499999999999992));
#2785=VECTOR('',#2784,1.);
#2786=CARTESIAN_POINT('',(-16.8379802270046,68.58,-19.0755418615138));
#2787=LINE('',#2786,#2785);
#2788=EDGE_CURVE('E423',#2749,#2781,#2787,.T.);
#2789=ORIENTED_EDGE('',*,*,#2788,.F.);
#2790=EDGE_LOOP('',(#2751,#2759,#2767,#2775,#2783,#2789));
#2791=FACE_BOUND('',#2790,.T.);
#2792=ADVANCED_FACE('F1139',(#2741,#2791),#2730,.T.);
#2793=CARTESIAN_POINT('',(14.9001950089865,65.405,17.9567610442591));
#2794=DIRECTION('',(-0.499999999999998,0.,0.866025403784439));
#2795=DIRECTION('',(0.86602540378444,0.,0.499999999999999));
#2796=AXIS2_PLACEMENT_3D('',#2793,#2794,#2795);
#2797=PLANE('',#2796);
#2798=ORIENTED_EDGE('',*,*,#2576,.T.);
#2799=DIRECTION('',(0.,1.,0.));
#2800=VECTOR('',#2799,1.);
#2801=CARTESIAN_POINT('',(16.8379802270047,65.405,19.0755418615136));
#2802=LINE('',#2801,#2800);
#2803=CARTESIAN_POINT('',(16.8379802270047,65.405,19.0755418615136));
#2804=VERTEX_POINT('',#2803);
#2805=EDGE_CURVE('E508',#2804,#2575,#2802,.T.);
#2806=ORIENTED_EDGE('',*,*,#2805,.F.);
#2807=DIRECTION('',(0.866025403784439,0.,0.499999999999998));
#2808=VECTOR('',#2807,1.);
#2809=CARTESIAN_POINT('',(14.9001950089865,65.405,17.9567610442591));
#2810=LINE('',#2809,#2808);
#2811=CARTESIAN_POINT('',(14.9001950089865,65.405,17.9567610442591));
#2812=VERTEX_POINT('',#2811);
#2813=EDGE_CURVE('E489',#2812,#2804,#2810,.T.);
#2814=ORIENTED_EDGE('',*,*,#2813,.F.);
#2815=DIRECTION('',(0.,1.,0.));
#2816=VECTOR('',#2815,1.);
#2817=CARTESIAN_POINT('',(14.9001950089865,65.405,17.9567610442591));
#2818=LINE('',#2817,#2816);
#2819=EDGE_CURVE('E524',#2812,#2573,#2818,.T.);
#2820=ORIENTED_EDGE('',*,*,#2819,.T.);
#2821=EDGE_LOOP('',(#2798,#2806,#2814,#2820));
#2822=FACE_BOUND('',#2821,.T.);
#2823=ADVANCED_FACE('F1121',(#2822),#2797,.F.);
#2824=CARTESIAN_POINT('',(14.9001950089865,65.405,15.71919940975));
#2825=DIRECTION('',(-1.,0.,0.));
#2826=DIRECTION('',(0.,0.,1.));
#2827=AXIS2_PLACEMENT_3D('',#2824,#2825,#2826);
#2828=PLANE('',#2827);
#2829=ORIENTED_EDGE('',*,*,#2584,.T.);
#2830=ORIENTED_EDGE('',*,*,#2819,.F.);
#2831=DIRECTION('',(0.,0.,1.));
#2832=VECTOR('',#2831,1.);
#2833=CARTESIAN_POINT('',(14.9001950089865,65.405,15.71919940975));
#2834=LINE('',#2833,#2832);
#2835=CARTESIAN_POINT('',(14.9001950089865,65.405,15.71919940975));
#2836=VERTEX_POINT('',#2835);
#2837=EDGE_CURVE('E505',#2836,#2812,#2834,.T.);
#2838=ORIENTED_EDGE('',*,*,#2837,.F.);
#2839=DIRECTION('',(0.,1.,0.));
#2840=VECTOR('',#2839,1.);
#2841=CARTESIAN_POINT('',(14.9001950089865,65.405,15.71919940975));
#2842=LINE('',#2841,#2840);
#2843=EDGE_CURVE('E527',#2836,#2583,#2842,.T.);
#2844=ORIENTED_EDGE('',*,*,#2843,.T.);
#2845=EDGE_LOOP('',(#2829,#2830,#2838,#2844));
#2846=FACE_BOUND('',#2845,.T.);
#2847=ADVANCED_FACE('F1117',(#2846),#2828,.F.);
#2848=CARTESIAN_POINT('',(16.8379802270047,65.405,14.6004185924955));
#2849=DIRECTION('',(-0.500000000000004,0.,-0.866025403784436));
#2850=DIRECTION('',(-0.866025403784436,0.,0.500000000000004));
#2851=AXIS2_PLACEMENT_3D('',#2848,#2849,#2850);
#2852=PLANE('',#2851);
#2853=ORIENTED_EDGE('',*,*,#2592,.T.);
#2854=ORIENTED_EDGE('',*,*,#2843,.F.);
#2855=DIRECTION('',(-0.866025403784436,0.,0.500000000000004));
#2856=VECTOR('',#2855,1.);
#2857=CARTESIAN_POINT('',(16.8379802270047,65.405,14.6004185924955));
#2858=LINE('',#2857,#2856);
#2859=CARTESIAN_POINT('',(16.8379802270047,65.405,14.6004185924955));
#2860=VERTEX_POINT('',#2859);
#2861=EDGE_CURVE('E502',#2860,#2836,#2858,.T.);
#2862=ORIENTED_EDGE('',*,*,#2861,.F.);
#2863=DIRECTION('',(0.,1.,0.));
#2864=VECTOR('',#2863,1.);
#2865=CARTESIAN_POINT('',(16.8379802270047,65.405,14.6004185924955));
#2866=LINE('',#2865,#2864);
#2867=EDGE_CURVE('E529',#2860,#2591,#2866,.T.);
#2868=ORIENTED_EDGE('',*,*,#2867,.T.);
#2869=EDGE_LOOP('',(#2853,#2854,#2862,#2868));
#2870=FACE_BOUND('',#2869,.T.);
#2871=ADVANCED_FACE('F1120',(#2870),#2852,.F.);
#2872=CARTESIAN_POINT('',(18.775765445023,65.405,15.71919940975));
#2873=DIRECTION('',(0.499999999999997,0.,-0.86602540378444));
#2874=DIRECTION('',(-0.866025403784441,0.,-0.499999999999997));
#2875=AXIS2_PLACEMENT_3D('',#2872,#2873,#2874);
#2876=PLANE('',#2875);
#2877=ORIENTED_EDGE('',*,*,#2600,.T.);
#2878=ORIENTED_EDGE('',*,*,#2867,.F.);
#2879=DIRECTION('',(-0.86602540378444,0.,-0.499999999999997));
#2880=VECTOR('',#2879,1.);
#2881=CARTESIAN_POINT('',(18.775765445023,65.405,15.71919940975));
#2882=LINE('',#2881,#2880);
#2883=CARTESIAN_POINT('',(18.775765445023,65.405,15.71919940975));
#2884=VERTEX_POINT('',#2883);
#2885=EDGE_CURVE('E499',#2884,#2860,#2882,.T.);
#2886=ORIENTED_EDGE('',*,*,#2885,.F.);
#2887=DIRECTION('',(0.,1.,0.));
#2888=VECTOR('',#2887,1.);
#2889=CARTESIAN_POINT('',(18.775765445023,65.405,15.71919940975));
#2890=LINE('',#2889,#2888);
#2891=EDGE_CURVE('E531',#2884,#2599,#2890,.T.);
#2892=ORIENTED_EDGE('',*,*,#2891,.T.);
#2893=EDGE_LOOP('',(#2877,#2878,#2886,#2892));
#2894=FACE_BOUND('',#2893,.T.);
#2895=ADVANCED_FACE('F1125',(#2894),#2876,.F.);
#2896=CARTESIAN_POINT('',(18.775765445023,65.405,17.9567610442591));
#2897=DIRECTION('',(1.,0.,0.));
#2898=DIRECTION('',(0.,0.,-1.));
#2899=AXIS2_PLACEMENT_3D('',#2896,#2897,#2898);
#2900=PLANE('',#2899);
#2901=ORIENTED_EDGE('',*,*,#2608,.T.);
#2902=ORIENTED_EDGE('',*,*,#2891,.F.);
#2903=DIRECTION('',(0.,0.,-1.));
#2904=VECTOR('',#2903,1.);
#2905=CARTESIAN_POINT('',(18.775765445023,65.405,17.9567610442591));
#2906=LINE('',#2905,#2904);
#2907=CARTESIAN_POINT('',(18.775765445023,65.405,17.9567610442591));
#2908=VERTEX_POINT('',#2907);
#2909=EDGE_CURVE('E496',#2908,#2884,#2906,.T.);
#2910=ORIENTED_EDGE('',*,*,#2909,.F.);
#2911=DIRECTION('',(0.,1.,0.));
#2912=VECTOR('',#2911,1.);
#2913=CARTESIAN_POINT('',(18.775765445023,65.405,17.9567610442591));
#2914=LINE('',#2913,#2912);
#2915=EDGE_CURVE('E533',#2908,#2607,#2914,.T.);
#2916=ORIENTED_EDGE('',*,*,#2915,.T.);
#2917=EDGE_LOOP('',(#2901,#2902,#2910,#2916));
#2918=FACE_BOUND('',#2917,.T.);
#2919=ADVANCED_FACE('F1129',(#2918),#2900,.F.);
#2920=CARTESIAN_POINT('',(16.8379802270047,65.405,19.0755418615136));
#2921=DIRECTION('',(0.499999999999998,0.,0.86602540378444));
#2922=DIRECTION('',(0.86602540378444,0.,-0.499999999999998));
#2923=AXIS2_PLACEMENT_3D('',#2920,#2921,#2922);
#2924=PLANE('',#2923);
#2925=ORIENTED_EDGE('',*,*,#2614,.T.);
#2926=ORIENTED_EDGE('',*,*,#2915,.F.);
#2927=DIRECTION('',(0.86602540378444,0.,-0.499999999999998));
#2928=VECTOR('',#2927,1.);
#2929=CARTESIAN_POINT('',(16.8379802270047,65.405,19.0755418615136));
#2930=LINE('',#2929,#2928);
#2931=EDGE_CURVE('E492',#2804,#2908,#2930,.T.);
#2932=ORIENTED_EDGE('',*,*,#2931,.F.);
#2933=ORIENTED_EDGE('',*,*,#2805,.T.);
#2934=EDGE_LOOP('',(#2925,#2926,#2932,#2933));
#2935=FACE_BOUND('',#2934,.T.);
#2936=ADVANCED_FACE('F1115',(#2935),#2924,.F.);
#2937=CARTESIAN_POINT('',(16.8379802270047,65.405,19.0755418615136));
#2938=DIRECTION('',(0.,1.,0.));
#2939=DIRECTION('',(-1.,0.,0.));
#2940=AXIS2_PLACEMENT_3D('',#2937,#2938,#2939);
#2941=PLANE('',#2940);
#2942=ORIENTED_EDGE('',*,*,#2813,.T.);
#2943=ORIENTED_EDGE('',*,*,#2931,.T.);
#2944=ORIENTED_EDGE('',*,*,#2909,.T.);
#2945=ORIENTED_EDGE('',*,*,#2885,.T.);
#2946=ORIENTED_EDGE('',*,*,#2861,.T.);
#2947=ORIENTED_EDGE('',*,*,#2837,.T.);
#2948=EDGE_LOOP('',(#2942,#2943,#2944,#2945,#2946,#2947));
#2949=FACE_BOUND('',#2948,.T.);
#2950=ADVANCED_FACE('F1112',(#2949),#2941,.T.);
#2951=CARTESIAN_POINT('',(-17.9567610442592,65.405,14.9001950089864));
#2952=DIRECTION('',(-0.866025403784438,0.,-0.500000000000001));
#2953=DIRECTION('',(-0.500000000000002,0.,0.866025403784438));
#2954=AXIS2_PLACEMENT_3D('',#2951,#2952,#2953);
#2955=PLANE('',#2954);
#2956=ORIENTED_EDGE('',*,*,#2663,.T.);
#2957=DIRECTION('',(0.,1.,0.));
#2958=VECTOR('',#2957,1.);
#2959=CARTESIAN_POINT('',(-19.0755418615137,65.405,16.8379802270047));
#2960=LINE('',#2959,#2958);
#2961=CARTESIAN_POINT('',(-19.0755418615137,65.405,16.8379802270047));
#2962=VERTEX_POINT('',#2961);
#2963=EDGE_CURVE('E461',#2962,#2662,#2960,.T.);
#2964=ORIENTED_EDGE('',*,*,#2963,.F.);
#2965=DIRECTION('',(-0.500000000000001,0.,0.866025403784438));
#2966=VECTOR('',#2965,1.);
#2967=CARTESIAN_POINT('',(-17.9567610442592,65.405,14.9001950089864));
#2968=LINE('',#2967,#2966);
#2969=CARTESIAN_POINT('',(-17.9567610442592,65.405,14.9001950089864));
#2970=VERTEX_POINT('',#2969);
#2971=EDGE_CURVE('E442',#2970,#2962,#2968,.T.);
#2972=ORIENTED_EDGE('',*,*,#2971,.F.);
#2973=DIRECTION('',(0.,1.,0.));
#2974=VECTOR('',#2973,1.);
#2975=CARTESIAN_POINT('',(-17.9567610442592,65.405,14.9001950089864));
#2976=LINE('',#2975,#2974);
#2977=EDGE_CURVE('E477',#2970,#2660,#2976,.T.);
#2978=ORIENTED_EDGE('',*,*,#2977,.T.);
#2979=EDGE_LOOP('',(#2956,#2964,#2972,#2978));
#2980=FACE_BOUND('',#2979,.T.);
#2981=ADVANCED_FACE('F1094',(#2980),#2955,.F.);
#2982=CARTESIAN_POINT('',(-15.7191994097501,65.405,14.9001950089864));
#2983=DIRECTION('',(0.,0.,-1.));
#2984=DIRECTION('',(-1.,0.,0.));
#2985=AXIS2_PLACEMENT_3D('',#2982,#2983,#2984);
#2986=PLANE('',#2985);
#2987=ORIENTED_EDGE('',*,*,#2671,.T.);
#2988=ORIENTED_EDGE('',*,*,#2977,.F.);
#2989=DIRECTION('',(-1.,0.,0.));
#2990=VECTOR('',#2989,1.);
#2991=CARTESIAN_POINT('',(-15.7191994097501,65.405,14.9001950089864));
#2992=LINE('',#2991,#2990);
#2993=CARTESIAN_POINT('',(-15.7191994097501,65.405,14.9001950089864));
#2994=VERTEX_POINT('',#2993);
#2995=EDGE_CURVE('E458',#2994,#2970,#2992,.T.);
#2996=ORIENTED_EDGE('',*,*,#2995,.F.);
#2997=DIRECTION('',(0.,1.,0.));
#2998=VECTOR('',#2997,1.);
#2999=CARTESIAN_POINT('',(-15.7191994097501,65.405,14.9001950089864));
#3000=LINE('',#2999,#2998);
#3001=EDGE_CURVE('E480',#2994,#2670,#3000,.T.);
#3002=ORIENTED_EDGE('',*,*,#3001,.T.);
#3003=EDGE_LOOP('',(#2987,#2988,#2996,#3002));
#3004=FACE_BOUND('',#3003,.T.);
#3005=ADVANCED_FACE('F1090',(#3004),#2986,.F.);
#3006=CARTESIAN_POINT('',(-14.6004185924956,65.405,16.8379802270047));
#3007=DIRECTION('',(0.866025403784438,0.,-0.500000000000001));
#3008=DIRECTION('',(-0.500000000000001,0.,-0.866025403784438));
#3009=AXIS2_PLACEMENT_3D('',#3006,#3007,#3008);
#3010=PLANE('',#3009);
#3011=ORIENTED_EDGE('',*,*,#2679,.T.);
#3012=ORIENTED_EDGE('',*,*,#3001,.F.);
#3013=DIRECTION('',(-0.500000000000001,0.,-0.866025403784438));
#3014=VECTOR('',#3013,1.);
#3015=CARTESIAN_POINT('',(-14.6004185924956,65.405,16.8379802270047));
#3016=LINE('',#3015,#3014);
#3017=CARTESIAN_POINT('',(-14.6004185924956,65.405,16.8379802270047));
#3018=VERTEX_POINT('',#3017);
#3019=EDGE_CURVE('E455',#3018,#2994,#3016,.T.);
#3020=ORIENTED_EDGE('',*,*,#3019,.F.);
#3021=DIRECTION('',(0.,1.,0.));
#3022=VECTOR('',#3021,1.);
#3023=CARTESIAN_POINT('',(-14.6004185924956,65.405,16.8379802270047));
#3024=LINE('',#3023,#3022);
#3025=EDGE_CURVE('E482',#3018,#2678,#3024,.T.);
#3026=ORIENTED_EDGE('',*,*,#3025,.T.);
#3027=EDGE_LOOP('',(#3011,#3012,#3020,#3026));
#3028=FACE_BOUND('',#3027,.T.);
#3029=ADVANCED_FACE('F1093',(#3028),#3010,.F.);
#3030=CARTESIAN_POINT('',(-15.7191994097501,65.405,18.775765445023));
#3031=DIRECTION('',(0.866025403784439,0.,0.5));
#3032=DIRECTION('',(0.5,0.,-0.866025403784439));
#3033=AXIS2_PLACEMENT_3D('',#3030,#3031,#3032);
#3034=PLANE('',#3033);
#3035=ORIENTED_EDGE('',*,*,#2687,.T.);
#3036=ORIENTED_EDGE('',*,*,#3025,.F.);
#3037=DIRECTION('',(0.5,0.,-0.866025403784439));
#3038=VECTOR('',#3037,1.);
#3039=CARTESIAN_POINT('',(-15.7191994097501,65.405,18.775765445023));
#3040=LINE('',#3039,#3038);
#3041=CARTESIAN_POINT('',(-15.7191994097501,65.405,18.775765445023));
#3042=VERTEX_POINT('',#3041);
#3043=EDGE_CURVE('E452',#3042,#3018,#3040,.T.);
#3044=ORIENTED_EDGE('',*,*,#3043,.F.);
#3045=DIRECTION('',(0.,1.,0.));
#3046=VECTOR('',#3045,1.);
#3047=CARTESIAN_POINT('',(-15.7191994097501,65.405,18.775765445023));
#3048=LINE('',#3047,#3046);
#3049=EDGE_CURVE('E484',#3042,#2686,#3048,.T.);
#3050=ORIENTED_EDGE('',*,*,#3049,.T.);
#3051=EDGE_LOOP('',(#3035,#3036,#3044,#3050));
#3052=FACE_BOUND('',#3051,.T.);
#3053=ADVANCED_FACE('F1098',(#3052),#3034,.F.);
#3054=CARTESIAN_POINT('',(-17.9567610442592,65.405,18.775765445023));
#3055=DIRECTION('',(0.,0.,1.));
#3056=DIRECTION('',(1.,0.,0.));
#3057=AXIS2_PLACEMENT_3D('',#3054,#3055,#3056);
#3058=PLANE('',#3057);
#3059=ORIENTED_EDGE('',*,*,#2695,.T.);
#3060=ORIENTED_EDGE('',*,*,#3049,.F.);
#3061=DIRECTION('',(1.,0.,0.));
#3062=VECTOR('',#3061,1.);
#3063=CARTESIAN_POINT('',(-17.9567610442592,65.405,18.775765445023));
#3064=LINE('',#3063,#3062);
#3065=CARTESIAN_POINT('',(-17.9567610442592,65.405,18.775765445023));
#3066=VERTEX_POINT('',#3065);
#3067=EDGE_CURVE('E449',#3066,#3042,#3064,.T.);
#3068=ORIENTED_EDGE('',*,*,#3067,.F.);
#3069=DIRECTION('',(0.,1.,0.));
#3070=VECTOR('',#3069,1.);
#3071=CARTESIAN_POINT('',(-17.9567610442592,65.405,18.775765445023));
#3072=LINE('',#3071,#3070);
#3073=EDGE_CURVE('E486',#3066,#2694,#3072,.T.);
#3074=ORIENTED_EDGE('',*,*,#3073,.T.);
#3075=EDGE_LOOP('',(#3059,#3060,#3068,#3074));
#3076=FACE_BOUND('',#3075,.T.);
#3077=ADVANCED_FACE('F1102',(#3076),#3058,.F.);
#3078=CARTESIAN_POINT('',(-19.0755418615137,65.405,16.8379802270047));
#3079=DIRECTION('',(-0.866025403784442,0.,0.499999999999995));
#3080=DIRECTION('',(0.499999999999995,0.,0.866025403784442));
#3081=AXIS2_PLACEMENT_3D('',#3078,#3079,#3080);
#3082=PLANE('',#3081);
#3083=ORIENTED_EDGE('',*,*,#2701,.T.);
#3084=ORIENTED_EDGE('',*,*,#3073,.F.);
#3085=DIRECTION('',(0.499999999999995,0.,0.866025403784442));
#3086=VECTOR('',#3085,1.);
#3087=CARTESIAN_POINT('',(-19.0755418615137,65.405,16.8379802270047));
#3088=LINE('',#3087,#3086);
#3089=EDGE_CURVE('E445',#2962,#3066,#3088,.T.);
#3090=ORIENTED_EDGE('',*,*,#3089,.F.);
#3091=ORIENTED_EDGE('',*,*,#2963,.T.);
#3092=EDGE_LOOP('',(#3083,#3084,#3090,#3091));
#3093=FACE_BOUND('',#3092,.T.);
#3094=ADVANCED_FACE('F1088',(#3093),#3082,.F.);
#3095=CARTESIAN_POINT('',(-19.0755418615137,65.405,16.8379802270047));
#3096=DIRECTION('',(0.,1.,0.));
#3097=DIRECTION('',(0.,0.,-1.));
#3098=AXIS2_PLACEMENT_3D('',#3095,#3096,#3097);
#3099=PLANE('',#3098);
#3100=ORIENTED_EDGE('',*,*,#2971,.T.);
#3101=ORIENTED_EDGE('',*,*,#3089,.T.);
#3102=ORIENTED_EDGE('',*,*,#3067,.T.);
#3103=ORIENTED_EDGE('',*,*,#3043,.T.);
#3104=ORIENTED_EDGE('',*,*,#3019,.T.);
#3105=ORIENTED_EDGE('',*,*,#2995,.T.);
#3106=EDGE_LOOP('',(#3100,#3101,#3102,#3103,#3104,#3105));
#3107=FACE_BOUND('',#3106,.T.);
#3108=ADVANCED_FACE('F1085',(#3107),#3099,.T.);
#3109=CARTESIAN_POINT('',(-14.9001950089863,65.405,-17.9567610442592));
#3110=DIRECTION('',(0.500000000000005,0.,-0.866025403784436));
#3111=DIRECTION('',(-0.866025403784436,0.,-0.500000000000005));
#3112=AXIS2_PLACEMENT_3D('',#3109,#3110,#3111);
#3113=PLANE('',#3112);
#3114=ORIENTED_EDGE('',*,*,#2750,.T.);
#3115=DIRECTION('',(0.,1.,0.));
#3116=VECTOR('',#3115,1.);
#3117=CARTESIAN_POINT('',(-16.8379802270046,65.405,-19.0755418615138));
#3118=LINE('',#3117,#3116);
#3119=CARTESIAN_POINT('',(-16.8379802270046,65.405,-19.0755418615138));
#3120=VERTEX_POINT('',#3119);
#3121=EDGE_CURVE('E383',#3120,#2749,#3118,.T.);
#3122=ORIENTED_EDGE('',*,*,#3121,.F.);
#3123=DIRECTION('',(-0.866025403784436,0.,-0.500000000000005));
#3124=VECTOR('',#3123,1.);
#3125=CARTESIAN_POINT('',(-14.9001950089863,65.405,-17.9567610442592));
#3126=LINE('',#3125,#3124);
#3127=CARTESIAN_POINT('',(-14.9001950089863,65.405,-17.9567610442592));
#3128=VERTEX_POINT('',#3127);
#3129=EDGE_CURVE('E387',#3128,#3120,#3126,.T.);
#3130=ORIENTED_EDGE('',*,*,#3129,.F.);
#3131=DIRECTION('',(0.,1.,0.));
#3132=VECTOR('',#3131,1.);
#3133=CARTESIAN_POINT('',(-14.9001950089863,65.405,-17.9567610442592));
#3134=LINE('',#3133,#3132);
#3135=EDGE_CURVE('E433',#3128,#2747,#3134,.T.);
#3136=ORIENTED_EDGE('',*,*,#3135,.T.);
#3137=EDGE_LOOP('',(#3114,#3122,#3130,#3136));
#3138=FACE_BOUND('',#3137,.T.);
#3139=ADVANCED_FACE('F385',(#3138),#3113,.F.);
#3140=CARTESIAN_POINT('',(-14.9001950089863,65.405,-15.7191994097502));
#3141=DIRECTION('',(1.,0.,0.));
#3142=DIRECTION('',(0.,0.,-1.));
#3143=AXIS2_PLACEMENT_3D('',#3140,#3141,#3142);
#3144=PLANE('',#3143);
#3145=ORIENTED_EDGE('',*,*,#2758,.T.);
#3146=ORIENTED_EDGE('',*,*,#3135,.F.);
#3147=DIRECTION('',(0.,0.,-1.));
#3148=VECTOR('',#3147,1.);
#3149=CARTESIAN_POINT('',(-14.9001950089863,65.405,-15.7191994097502));
#3150=LINE('',#3149,#3148);
#3151=CARTESIAN_POINT('',(-14.9001950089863,65.405,-15.7191994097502));
#3152=VERTEX_POINT('',#3151);
#3153=EDGE_CURVE('E393',#3152,#3128,#3150,.T.);
#3154=ORIENTED_EDGE('',*,*,#3153,.F.);
#3155=DIRECTION('',(0.,1.,0.));
#3156=VECTOR('',#3155,1.);
#3157=CARTESIAN_POINT('',(-14.9001950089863,65.405,-15.7191994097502));
#3158=LINE('',#3157,#3156);
#3159=EDGE_CURVE('E435',#3152,#2757,#3158,.T.);
#3160=ORIENTED_EDGE('',*,*,#3159,.T.);
#3161=EDGE_LOOP('',(#3145,#3146,#3154,#3160));
#3162=FACE_BOUND('',#3161,.T.);
#3163=ADVANCED_FACE('F1065',(#3162),#3144,.F.);
#3164=CARTESIAN_POINT('',(-16.8379802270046,65.405,-14.6004185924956));
#3165=DIRECTION('',(0.499999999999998,0.,0.86602540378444));
#3166=DIRECTION('',(0.86602540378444,0.,-0.499999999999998));
#3167=AXIS2_PLACEMENT_3D('',#3164,#3165,#3166);
#3168=PLANE('',#3167);
#3169=ORIENTED_EDGE('',*,*,#2766,.T.);
#3170=ORIENTED_EDGE('',*,*,#3159,.F.);
#3171=DIRECTION('',(0.86602540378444,0.,-0.499999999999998));
#3172=VECTOR('',#3171,1.);
#3173=CARTESIAN_POINT('',(-16.8379802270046,65.405,-14.6004185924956));
#3174=LINE('',#3173,#3172);
#3175=CARTESIAN_POINT('',(-16.8379802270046,65.405,-14.6004185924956));
#3176=VERTEX_POINT('',#3175);
#3177=EDGE_CURVE('E419',#3176,#3152,#3174,.T.);
#3178=ORIENTED_EDGE('',*,*,#3177,.F.);
#3179=DIRECTION('',(0.,1.,0.));
#3180=VECTOR('',#3179,1.);
#3181=CARTESIAN_POINT('',(-16.8379802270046,65.405,-14.6004185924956));
#3182=LINE('',#3181,#3180);
#3183=EDGE_CURVE('E437',#3176,#2765,#3182,.T.);
#3184=ORIENTED_EDGE('',*,*,#3183,.T.);
#3185=EDGE_LOOP('',(#3169,#3170,#3178,#3184));
#3186=FACE_BOUND('',#3185,.T.);
#3187=ADVANCED_FACE('F1068',(#3186),#3168,.F.);
#3188=CARTESIAN_POINT('',(-18.7757654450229,65.405,-15.7191994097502));
#3189=DIRECTION('',(-0.500000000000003,0.,0.866025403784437));
#3190=DIRECTION('',(0.866025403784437,0.,0.500000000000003));
#3191=AXIS2_PLACEMENT_3D('',#3188,#3189,#3190);
#3192=PLANE('',#3191);
#3193=ORIENTED_EDGE('',*,*,#2774,.T.);
#3194=ORIENTED_EDGE('',*,*,#3183,.F.);
#3195=DIRECTION('',(0.866025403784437,0.,0.500000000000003));
#3196=VECTOR('',#3195,1.);
#3197=CARTESIAN_POINT('',(-18.7757654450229,65.405,-15.7191994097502));
#3198=LINE('',#3197,#3196);
#3199=CARTESIAN_POINT('',(-18.7757654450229,65.405,-15.7191994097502));
#3200=VERTEX_POINT('',#3199);
#3201=EDGE_CURVE('E416',#3200,#3176,#3198,.T.);
#3202=ORIENTED_EDGE('',*,*,#3201,.F.);
#3203=DIRECTION('',(0.,1.,0.));
#3204=VECTOR('',#3203,1.);
#3205=CARTESIAN_POINT('',(-18.7757654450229,65.405,-15.7191994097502));
#3206=LINE('',#3205,#3204);
#3207=EDGE_CURVE('E439',#3200,#2773,#3206,.T.);
#3208=ORIENTED_EDGE('',*,*,#3207,.T.);
#3209=EDGE_LOOP('',(#3193,#3194,#3202,#3208));
#3210=FACE_BOUND('',#3209,.T.);
#3211=ADVANCED_FACE('F1072',(#3210),#3192,.F.);
#3212=CARTESIAN_POINT('',(-18.7757654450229,65.405,-17.9567610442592));
#3213=DIRECTION('',(-1.,0.,0.));
#3214=DIRECTION('',(0.,0.,1.));
#3215=AXIS2_PLACEMENT_3D('',#3212,#3213,#3214);
#3216=PLANE('',#3215);
#3217=ORIENTED_EDGE('',*,*,#2782,.T.);
#3218=ORIENTED_EDGE('',*,*,#3207,.F.);
#3219=DIRECTION('',(0.,0.,1.));
#3220=VECTOR('',#3219,1.);
#3221=CARTESIAN_POINT('',(-18.7757654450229,65.405,-17.9567610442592));
#3222=LINE('',#3221,#3220);
#3223=CARTESIAN_POINT('',(-18.7757654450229,65.405,-17.9567610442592));
#3224=VERTEX_POINT('',#3223);
#3225=EDGE_CURVE('E401',#3224,#3200,#3222,.T.);
#3226=ORIENTED_EDGE('',*,*,#3225,.F.);
#3227=DIRECTION('',(0.,1.,0.));
#3228=VECTOR('',#3227,1.);
#3229=CARTESIAN_POINT('',(-18.7757654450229,65.405,-17.9567610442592));
#3230=LINE('',#3229,#3228);
#3231=EDGE_CURVE('E392',#3224,#2781,#3230,.T.);
#3232=ORIENTED_EDGE('',*,*,#3231,.T.);
#3233=EDGE_LOOP('',(#3217,#3218,#3226,#3232));
#3234=FACE_BOUND('',#3233,.T.);
#3235=ADVANCED_FACE('F1076',(#3234),#3216,.F.);
#3236=CARTESIAN_POINT('',(-16.8379802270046,65.405,-19.0755418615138));
#3237=DIRECTION('',(-0.499999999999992,0.,-0.866025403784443));
#3238=DIRECTION('',(-0.866025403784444,0.,0.499999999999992));
#3239=AXIS2_PLACEMENT_3D('',#3236,#3237,#3238);
#3240=PLANE('',#3239);
#3241=ORIENTED_EDGE('',*,*,#2788,.T.);
#3242=ORIENTED_EDGE('',*,*,#3231,.F.);
#3243=DIRECTION('',(-0.866025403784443,0.,0.499999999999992));
#3244=VECTOR('',#3243,1.);
#3245=CARTESIAN_POINT('',(-16.8379802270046,65.405,-19.0755418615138));
#3246=LINE('',#3245,#3244);
#3247=EDGE_CURVE('E396',#3120,#3224,#3246,.T.);
#3248=ORIENTED_EDGE('',*,*,#3247,.F.);
#3249=ORIENTED_EDGE('',*,*,#3121,.T.);
#3250=EDGE_LOOP('',(#3241,#3242,#3248,#3249));
#3251=FACE_BOUND('',#3250,.T.);
#3252=ADVANCED_FACE('F397',(#3251),#3240,.F.);
#3253=CARTESIAN_POINT('',(-16.8379802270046,65.405,-19.0755418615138));
#3254=DIRECTION('',(0.,1.,0.));
#3255=DIRECTION('',(1.,0.,0.));
#3256=AXIS2_PLACEMENT_3D('',#3253,#3254,#3255);
#3257=PLANE('',#3256);
#3258=ORIENTED_EDGE('',*,*,#3129,.T.);
#3259=ORIENTED_EDGE('',*,*,#3247,.T.);
#3260=ORIENTED_EDGE('',*,*,#3225,.T.);
#3261=ORIENTED_EDGE('',*,*,#3201,.T.);
#3262=ORIENTED_EDGE('',*,*,#3177,.T.);
#3263=ORIENTED_EDGE('',*,*,#3153,.T.);
#3264=EDGE_LOOP('',(#3258,#3259,#3260,#3261,#3262,#3263));
#3265=FACE_BOUND('',#3264,.T.);
#3266=ADVANCED_FACE('F403',(#3265),#3257,.T.);
#3267=CARTESIAN_POINT('',(16.8379802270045,68.58,-16.8379802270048));
#3268=DIRECTION('',(0.,-1.,0.));
#3269=DIRECTION('',(0.,0.,-1.));
#3270=AXIS2_PLACEMENT_3D('',#3267,#3268,#3269);
#3271=CONICAL_SURFACE('',#3270,3.58139999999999,0.785398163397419);
#3272=ORIENTED_EDGE('',*,*,#2299,.F.);
#3273=EDGE_LOOP('',(#3272));
#3274=FACE_BOUND('',#3273,.T.);
#3275=ORIENTED_EDGE('',*,*,#2319,.F.);
#3276=EDGE_LOOP('',(#3275));
#3277=FACE_BOUND('',#3276,.T.);
#3278=ADVANCED_FACE('F1064',(#3274,#3277),#3271,.T.);
#3279=CARTESIAN_POINT('',(16.8379802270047,68.58,16.8379802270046));
#3280=DIRECTION('',(0.,-1.,0.));
#3281=DIRECTION('',(0.,0.,-1.));
#3282=AXIS2_PLACEMENT_3D('',#3279,#3280,#3281);
#3283=CONICAL_SURFACE('',#3282,3.58139999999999,0.785398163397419);
#3284=ORIENTED_EDGE('',*,*,#2544,.F.);
#3285=EDGE_LOOP('',(#3284));
#3286=FACE_BOUND('',#3285,.T.);
#3287=ORIENTED_EDGE('',*,*,#2564,.F.);
#3288=EDGE_LOOP('',(#3287));
#3289=FACE_BOUND('',#3288,.T.);
#3290=ADVANCED_FACE('F1810',(#3286,#3289),#3283,.T.);
#3291=CARTESIAN_POINT('',(-16.8379802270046,68.58,16.8379802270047));
#3292=DIRECTION('',(0.,-1.,0.));
#3293=DIRECTION('',(0.,0.,-1.));
#3294=AXIS2_PLACEMENT_3D('',#3291,#3292,#3293);
#3295=CONICAL_SURFACE('',#3294,3.58139999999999,0.785398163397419);
#3296=ORIENTED_EDGE('',*,*,#2631,.F.);
#3297=EDGE_LOOP('',(#3296));
#3298=FACE_BOUND('',#3297,.T.);
#3299=ORIENTED_EDGE('',*,*,#2651,.F.);
#3300=EDGE_LOOP('',(#3299));
#3301=FACE_BOUND('',#3300,.T.);
#3302=ADVANCED_FACE('F1803',(#3298,#3301),#3295,.T.);
#3303=CARTESIAN_POINT('',(-16.8379802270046,68.58,-16.8379802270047));
#3304=DIRECTION('',(0.,-1.,0.));
#3305=DIRECTION('',(0.,0.,-1.));
#3306=AXIS2_PLACEMENT_3D('',#3303,#3304,#3305);
#3307=CONICAL_SURFACE('',#3306,3.58139999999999,0.785398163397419);
#3308=ORIENTED_EDGE('',*,*,#2718,.F.);
#3309=EDGE_LOOP('',(#3308));
#3310=FACE_BOUND('',#3309,.T.);
#3311=ORIENTED_EDGE('',*,*,#2738,.F.);
#3312=EDGE_LOOP('',(#3311));
#3313=FACE_BOUND('',#3312,.T.);
#3314=ADVANCED_FACE('F33',(#3310,#3313),#3307,.T.);
#3315=CARTESIAN_POINT('',(0.,27.432,29.718));
#3316=DIRECTION('',(0.,0.,1.));
#3317=DIRECTION('',(1.,0.,0.));
#3318=AXIS2_PLACEMENT_3D('',#3315,#3316,#3317);
#3319=CONICAL_SURFACE('',#3318,10.7315,0.0174532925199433);
#3320=CARTESIAN_POINT('',(0.,27.432,17.018));
#3321=DIRECTION('',(0.,0.,1.));
#3322=DIRECTION('',(1.,0.,0.));
#3323=AXIS2_PLACEMENT_3D('',#3320,#3321,#3322);
#3324=CIRCLE('',#3323,10.5098206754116);
#3325=CARTESIAN_POINT('',(10.5098206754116,27.432,17.018));
#3326=VERTEX_POINT('',#3325);
#3327=EDGE_CURVE('E412',#3326,#3326,#3324,.T.);
#3328=ORIENTED_EDGE('',*,*,#3327,.F.);
#3329=EDGE_LOOP('',(#3328));
#3330=FACE_BOUND('',#3329,.T.);
#3331=ORIENTED_EDGE('',*,*,#998,.F.);
#3332=EDGE_LOOP('',(#3331));
#3333=FACE_BOUND('',#3332,.T.);
#3334=ADVANCED_FACE('F1054',(#3330,#3333),#3319,.F.);
#3335=CARTESIAN_POINT('',(0.,27.432,17.018));
#3336=DIRECTION('',(0.,0.,1.));
#3337=DIRECTION('',(1.,0.,0.));
#3338=AXIS2_PLACEMENT_3D('',#3335,#3336,#3337);
#3339=PLANE('',#3338);
#3340=CARTESIAN_POINT('',(0.,27.432,17.018));
#3341=DIRECTION('',(0.,0.,1.));
#3342=DIRECTION('',(1.,0.,0.));
#3343=AXIS2_PLACEMENT_3D('',#3340,#3341,#3342);
#3344=CIRCLE('',#3343,9.1186);
#3345=CARTESIAN_POINT('',(9.1186,27.432,17.018));
#3346=VERTEX_POINT('',#3345);
#3347=EDGE_CURVE('E1050',#3346,#3346,#3344,.T.);
#3348=ORIENTED_EDGE('',*,*,#3347,.F.);
#3349=EDGE_LOOP('',(#3348));
#3350=FACE_BOUND('',#3349,.T.);
#3351=ORIENTED_EDGE('',*,*,#3327,.T.);
#3352=EDGE_LOOP('',(#3351));
#3353=FACE_BOUND('',#3352,.T.);
#3354=ADVANCED_FACE('F1059',(#3350,#3353),#3339,.T.);
#3355=CARTESIAN_POINT('',(0.,27.432,13.843));
#3356=DIRECTION('',(0.,0.,1.));
#3357=DIRECTION('',(1.,0.,0.));
#3358=AXIS2_PLACEMENT_3D('',#3355,#3356,#3357);
#3359=CYLINDRICAL_SURFACE('',#3358,9.1186);
#3360=ORIENTED_EDGE('',*,*,#3347,.T.);
#3361=EDGE_LOOP('',(#3360));
#3362=FACE_BOUND('',#3361,.T.);
#3363=CARTESIAN_POINT('',(0.,27.432,13.843));
#3364=DIRECTION('',(0.,0.,1.));
#3365=DIRECTION('',(1.,0.,0.));
#3366=AXIS2_PLACEMENT_3D('',#3363,#3364,#3365);
#3367=CIRCLE('',#3366,9.1186);
#3368=CARTESIAN_POINT('',(9.1186,27.432,13.843));
#3369=VERTEX_POINT('',#3368);
#3370=EDGE_CURVE('E1765',#3369,#3369,#3367,.T.);
#3371=ORIENTED_EDGE('',*,*,#3370,.F.);
#3372=EDGE_LOOP('',(#3371));
#3373=FACE_BOUND('',#3372,.T.);
#3374=ADVANCED_FACE('F1753',(#3362,#3373),#3359,.F.);
#3375=CARTESIAN_POINT('',(0.,27.432,13.843));
#3376=DIRECTION('',(0.,0.,1.));
#3377=DIRECTION('',(1.,0.,0.));
#3378=AXIS2_PLACEMENT_3D('',#3375,#3376,#3377);
#3379=PLANE('',#3378);
#3380=ORIENTED_EDGE('',*,*,#3370,.T.);
#3381=EDGE_LOOP('',(#3380));
#3382=FACE_BOUND('',#3381,.T.);
#3383=ADVANCED_FACE('F1704',(#3382),#3379,.T.);
#3384=CARTESIAN_POINT('',(2.07519805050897E-13,27.432,-29.718));
#3385=DIRECTION('',(0.,0.,-1.));
#3386=DIRECTION('',(-1.,0.,0.));
#3387=AXIS2_PLACEMENT_3D('',#3384,#3385,#3386);
#3388=CONICAL_SURFACE('',#3387,10.7315,0.0174532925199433);
#3389=CARTESIAN_POINT('',(1.18836127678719E-13,27.432,-17.018));
#3390=DIRECTION('',(0.,0.,-1.));
#3391=DIRECTION('',(-1.,0.,0.));
#3392=AXIS2_PLACEMENT_3D('',#3389,#3390,#3391);
#3393=CIRCLE('',#3392,10.5098206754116);
#3394=CARTESIAN_POINT('',(-10.5098206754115,27.432,-17.0180000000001));
#3395=VERTEX_POINT('',#3394);
#3396=EDGE_CURVE('E1766',#3395,#3395,#3393,.T.);
#3397=ORIENTED_EDGE('',*,*,#3396,.F.);
#3398=EDGE_LOOP('',(#3397));
#3399=FACE_BOUND('',#3398,.T.);
#3400=ORIENTED_EDGE('',*,*,#837,.F.);
#3401=EDGE_LOOP('',(#3400));
#3402=FACE_BOUND('',#3401,.T.);
#3403=ADVANCED_FACE('F1709',(#3399,#3402),#3388,.F.);
#3404=CARTESIAN_POINT('',(1.18836127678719E-13,27.432,-17.018));
#3405=DIRECTION('',(0.,0.,-1.));
#3406=DIRECTION('',(-1.,0.,0.));
#3407=AXIS2_PLACEMENT_3D('',#3404,#3405,#3406);
#3408=PLANE('',#3407);
#3409=CARTESIAN_POINT('',(1.18836127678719E-13,27.432,-17.018));
#3410=DIRECTION('',(0.,0.,-1.));
#3411=DIRECTION('',(-1.,0.,0.));
#3412=AXIS2_PLACEMENT_3D('',#3409,#3410,#3411);
#3413=CIRCLE('',#3412,9.1186);
#3414=CARTESIAN_POINT('',(-9.11859999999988,27.432,-17.0180000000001));
#3415=VERTEX_POINT('',#3414);
#3416=EDGE_CURVE('E35',#3415,#3415,#3413,.T.);
#3417=ORIENTED_EDGE('',*,*,#3416,.F.);
#3418=EDGE_LOOP('',(#3417));
#3419=FACE_BOUND('',#3418,.T.);
#3420=ORIENTED_EDGE('',*,*,#3396,.T.);
#3421=EDGE_LOOP('',(#3420));
#3422=FACE_BOUND('',#3421,.T.);
#3423=ADVANCED_FACE('F1714',(#3419,#3422),#3408,.T.);
#3424=CARTESIAN_POINT('',(0.,27.432,-13.843));
#3425=DIRECTION('',(0.,0.,-1.));
#3426=DIRECTION('',(-1.,0.,0.));
#3427=AXIS2_PLACEMENT_3D('',#3424,#3425,#3426);
#3428=CYLINDRICAL_SURFACE('',#3427,9.1186);
#3429=ORIENTED_EDGE('',*,*,#3416,.T.);
#3430=EDGE_LOOP('',(#3429));
#3431=FACE_BOUND('',#3430,.T.);
#3432=CARTESIAN_POINT('',(0.,27.432,-13.843));
#3433=DIRECTION('',(0.,0.,-1.));
#3434=DIRECTION('',(-1.,0.,0.));
#3435=AXIS2_PLACEMENT_3D('',#3432,#3433,#3434);
#3436=CIRCLE('',#3435,9.1186);
#3437=CARTESIAN_POINT('',(-9.1185999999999,27.432,-13.8430000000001));
#3438=VERTEX_POINT('',#3437);
#3439=EDGE_CURVE('E1770',#3438,#3438,#3436,.T.);
#3440=ORIENTED_EDGE('',*,*,#3439,.F.);
#3441=EDGE_LOOP('',(#3440));
#3442=FACE_BOUND('',#3441,.T.);
#3443=ADVANCED_FACE('F1724',(#3431,#3442),#3428,.F.);
#3444=CARTESIAN_POINT('',(0.,27.432,-13.843));
#3445=DIRECTION('',(0.,0.,-1.));
#3446=DIRECTION('',(-1.,0.,0.));
#3447=AXIS2_PLACEMENT_3D('',#3444,#3445,#3446);
#3448=PLANE('',#3447);
#3449=ORIENTED_EDGE('',*,*,#3439,.T.);
#3450=EDGE_LOOP('',(#3449));
#3451=FACE_BOUND('',#3450,.T.);
#3452=ADVANCED_FACE('F1734',(#3451),#3448,.T.);
#3453=CLOSED_SHELL('',(#674,#1024,#1041,#1061,#1081,#1101,#1119,#1139,#1167,#1187,#1199,#1211,
#1231,#1284,#1364,#1396,#1420,#1445,#1462,#1474,#1490,#1539,#1555,#1604,#1620,#1669,#1685,#1734,
#1792,#1814,#1831,#1848,#1860,#1872,#1930,#1952,#1969,#1986,#1998,#2010,#2068,#2090,#2107,#2124,
#2136,#2148,#2206,#2228,#2245,#2262,#2274,#2286,#2306,#2373,#2404,#2428,#2452,#2476,#2500,#2517,
#2531,#2551,#2618,#2638,#2705,#2725,#2792,#2823,#2847,#2871,#2895,#2919,#2936,#2950,#2981,#3005,
#3029,#3053,#3077,#3094,#3108,#3139,#3163,#3187,#3211,#3235,#3252,#3266,#3278,#3290,#3302,#3314,
#3334,#3354,#3374,#3383,#3403,#3423,#3443,#3452));
#3454=MANIFOLD_SOLID_BREP('B2',#3453);
#3455=ADVANCED_BREP_SHAPE_REPRESENTATION('',(#18,#3454),#14);
#3456=SHAPE_DEFINITION_REPRESENTATION(#9,#3455);
ENDSEC;
END-ISO-10303-21;
